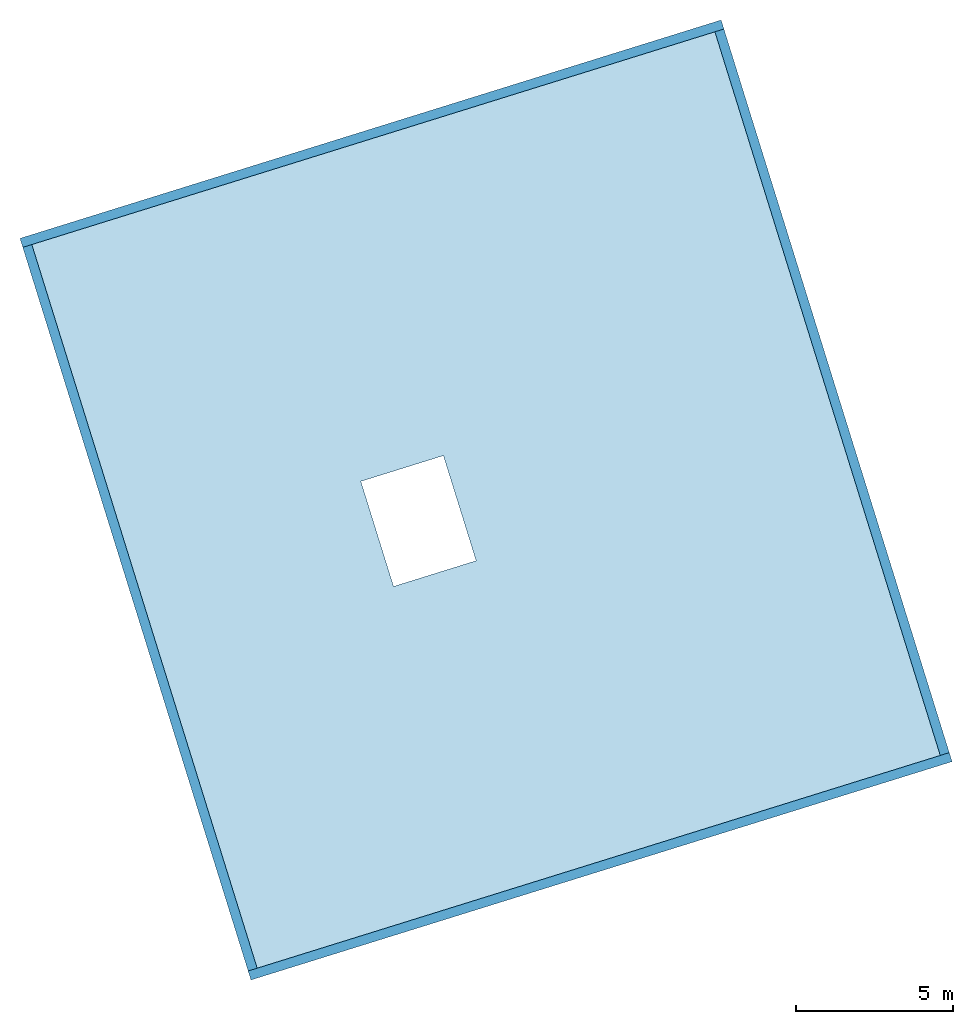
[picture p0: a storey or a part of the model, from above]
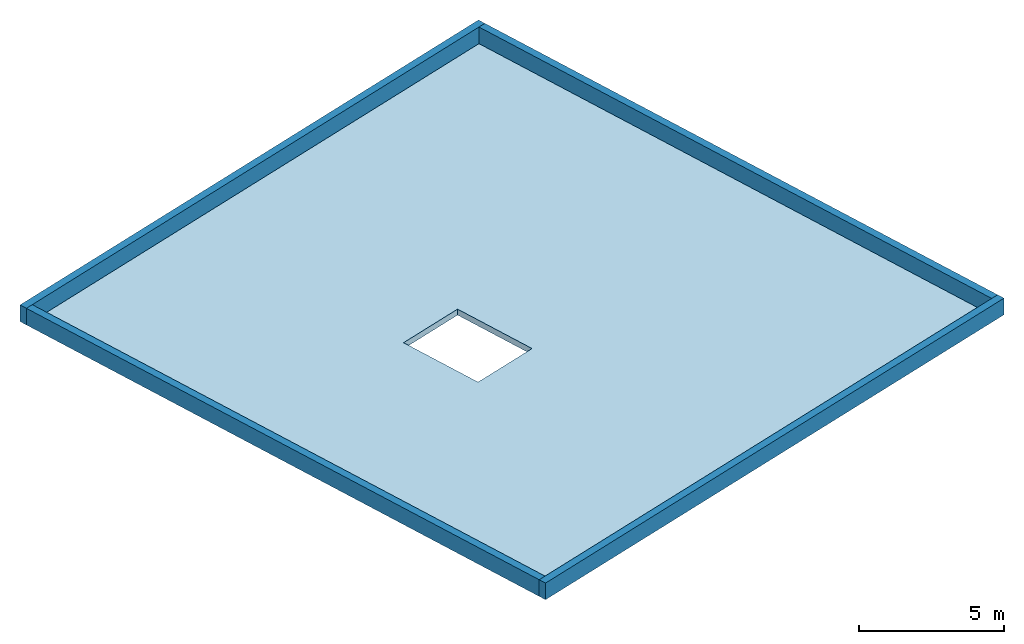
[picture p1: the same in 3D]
Properties of the parts of a building model (IFC4), part 1 of 3

# File
Description: ViewDefinition [ReferenceView_V1.2], RevitIdentifiers [ContentGUID: 7b0fba1c-e461-43e6-a004-74300536da52, VersionGUID: 268f83e5-9db5-464a-ad46-58d0016dc86d, NumberOfSaves: 303], Options [Excluded Entities: IfcGroup;], CoordinateReference [CoordinateBase: Survey Point, ProjectSite: Internal]
File name: MiniBIM 3.1 DO_01_VORM.ifc
Time: 2025-11-07T13:31:51+01:00
Organization: VORM Holding B.V.
Written by: IfcOpenShell 0.8.2
Made in: Bonsai 0.8.2

# IfcProject, 0000
LongName: Voorbeelmodel MiniBIM 3.1 DO-fase; Phase: PROJECTFASE

# IfcSite, Schiehaven
RefLatitude: 51, 54, 13, 78253; RefLongitude: 4, 27, 15, 99642; RefElevation: 3.5 m
Pset_SiteCommon - Reference: Project Information

# IfcBuilding, VORM huis
LongName: VORM huis
Pset_BuildingCommon - Reference: Project Information; NumberOfStoreys: 11; IsLandmarked: no
Pset_BuildingElementProxyCommon - Reference: Project Information; IsExternal: no
Pset_BuildingStoreyCommon - Reference: Project Information; AboveGround: no
Pset_BuildingSystemCommon - Reference: Project Information

# IfcBuildingStorey: Level:Level bouwniveau (PBP) (11)
In: VORM huis
Pset_BuildingStoreyCommon - Reference: Level bouwniveau (PBP)
Name | LongName | Elevation (m) | EntranceLevel | AboveGround
-1 kelder | -1 kelder | -3.2 | no | no
00 begane grond | begane grond | 0 | yes | yes
01 eerste verdieping | 01 eerste verdieping | 3.9 | no | yes
02 tweede verdieping | 02 tweede verdieping | 6.9 | no | yes
03 derde verdieping | 03 derde verdieping | 9.9 | no | yes
04 vierde verdieping | 04 vierde verdieping | 12.9 | no | yes
05 vijfde verdieping | 05 vijfde verdieping | 15.9 | no | yes
06 zesde verdieping | 06 zesde verdieping | 18.9 | no | yes
07 zevende verdieping | 07 zevende verdieping | 21.9 | no | yes
08 achtste verdieping | 08 achtste verdieping | 24.9 | no | yes
09 negende verdieping | 09 negende verdieping | 27.9 | no | yes

# IfcBoiler: NLRS_51_ME_WB_warmtepomp_gen:generiek (45)
Type - Classification: 51.51 (NL-SfB); Material: <Unnamed>
Pset_BoilerTypeCommon - Reference: generiek; sets with these values: 2
Name (NLRS_51_ME_WB_warmtepomp_gen:generiek:...)
1525490
1530097
1530123
1530149
1530175
1530331
1530383
1558899
1559981
1560007
1560033
1560059
1560215
1560267
1570773
1575072
1600094
1600120
1600146
1600172
1600328
1600380
1600641
1600830
1601019
1601208
1601397
1602758
1603185
1605235
1605260
1605285
1605310
1605460
1605510
1606281
1609021
1609049
1609077
1609105
1609273
1609329
1615438
1619511
1668635

# IfcBuildingElementProxy: VORM_coordinatiepunt:CRS-coordinatiepunt, CRS-coordinatiepunt
In: 00 begane grond
Type - Classification: 00.00 (NL-SfB); Material: Blauw, Wit
Pset_BuildingElementProxyCommon - IsExternal: no; Reference: CRS-coordinatiepunt
Pset_EnvironmentalImpactIndicators - Reference: CRS-coordinatiepunt
Qto_BuildingElementProxyQuantities - NetSurfaceArea: 6.92096 m2; NetVolume: 0.458368 m3

# IfcBuildingElementProxy: VORM_coordinatiepunt:Lokaal-coordinatiepunt, Lokaal-coordinatiepunt
In: 00 begane grond
Type - Classification: 00.00 (NL-SfB); Material: Blauw, Wit
Pset_BuildingElementProxyCommon - IsExternal: no; Reference: Lokaal-coordinatiepunt
Pset_EnvironmentalImpactIndicators - Reference: Lokaal-coordinatiepunt
Qto_BuildingElementProxyQuantities - NetSurfaceArea: 7.78088 m2; NetVolume: 1.00022 m3

# IfcDistributionChamberElement: NLRS_61_GM_UN_Jonka meterkast_gen:Jonka_kast (52)
Type - PredefinedType: METERCHAMBER; Classification: 61.51 centrale elektrotechnische voorzieningen; energiedistributie laagspanning ?1kV, voedingsleiding laagspanningshoofdverdeler (NL-SfB); Material: <Unnamed>
Type - Pset_ManufacturerTypeInformation - Manufacturer: Jonka o.g.
Pset_DistributionChamberElementCommon - Reference: Jonka_kast; sets with these values: 2
Qto_DistributionChamberElementBaseQuantities - GrossSurfaceArea: 0.130276 m2; NetSurfaceArea: 15.0923 m2; GrossVolume: 0.000819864 m3; NetVolume: 0.122447 m3
Name (NLRS_61_GM_UN_Jonka meterkast_gen:Jonka_kast:...)
1522652
1530094
1530120
1530146
1530172
1530328
1530380
1555103
1556118
1556176
1558414
1558432
1558450
1558896
1559978
1560004
1560030
1560056
1560212
1560264
1563814
1565700
1565724
1565748
1565772
1565916
1565964
1575132
1600095
1600121
1600147
1600173
1600329
1600381
1603042
1605222
1605247
1605272
1605297
1605447
1605497
1606282
1609022
1609050
1609078
1609106
1609274
1609330
1611610
1618740
1668613
1668718

# IfcDoor: 31_DO_buitendeur dubbel:buitendeur zelfsluitend 30min (2)
In: 00 begane grond
Type - PredefinedType: DOOR; Classification: 31.30 buitenwandopeningen; gevuld met deuren, algemeen (verzamelniveau) (NL-SfB); Material: PD_a_buitenwandopeningen, metaal_aluminium_ntb
Type - Pset_DoorCommon - IsExternal: no; FireRating: 30
OverallHeight: 2.35 m; OverallWidth: 1.965 m
Pset_DoorCommon - Reference: buitendeur zelfsluitend 30min
Pset_EnvironmentalImpactIndicators - Reference: buitendeur zelfsluitend 30min
MiniBIM ILS - BouwwerkNummer: 01
Qto_DoorBaseQuantities - Width: 1.965 m; Height: 2.35 m; Perimeter: 1.965 m; Area: 4.61775 m2
Name | Gebruiksbestemming | Orientatie
Vluchtdeur | Overige gebruiksfunctie | West
Vluchtdeur | Bijeenkomstfunctie | Oost

# IfcDoor: 31_DO_buitendeur enkel:buitendeur zelfsluitend 30min (2)
In: 00 begane grond
Type - PredefinedType: DOOR; Classification: 31.30 buitenwandopeningen; gevuld met deuren, algemeen (verzamelniveau) (NL-SfB); Material: PD_a_buitenwandopeningen, metaal_aluminium_ntb
Type - Pset_DoorCommon - IsExternal: no; FireRating: 30
OverallHeight: 2.35 m; OverallWidth: 1.05 m
Pset_DoorCommon - Reference: buitendeur zelfsluitend 30min
Pset_EnvironmentalImpactIndicators - Reference: buitendeur zelfsluitend 30min
MiniBIM ILS - BouwwerkNummer: 01; Gebruiksbestemming: Overige gebruiksfunctie
Qto_DoorBaseQuantities - Width: 1.05 m; Height: 2.35 m; Perimeter: 2 m; Area: 2.4675 m2
Name | Orientatie
Vluchtdeur | Oost
Vluchtdeur | West

# IfcDoor: 31_DO_buitendeur enkel:woningtoegangsdeur (6)
In: 00 begane grond
Type - PredefinedType: DOOR; OperationType: REVOLVING; Classification: 31.30 buitenwandopeningen; gevuld met deuren, algemeen (verzamelniveau) (NL-SfB); Material: PD_a_buitenwandopeningen, metaal_aluminium_ntb
Type - Woningtoegangsdeur:1 - PanelOperation: REVOLVING
Type - Pset_DoorCommon - IsExternal: no
OverallHeight: 2.35 m; OverallWidth: 1.05 m
Pset_DoorCommon - Reference: woningtoegangsdeur
Pset_EnvironmentalImpactIndicators - Reference: woningtoegangsdeur
MiniBIM ILS - BouwwerkNummer: 01; Gebruiksbestemming: Woonfunctie
Qto_DoorBaseQuantities - Width: 1.05 m; Height: 2.35 m; Perimeter: 2 m; Area: 2.4675 m2
Name | Orientatie
3 x Woningtoegangsdeur | Zuid
3 x Woningtoegangsdeur | Noord

# IfcDoor: 32_DO_binnendeur dubbel:binnendeur zelfsluitend 30min (3)
In: 00 begane grond
Type - PredefinedType: DOOR; Classification: 32.30 binnenwandopeningen; gevuld met deuren, algemeen (verzamelniveau) (NL-SfB); Material: PD_a_binnenwandopeningen, metaal_aluminium_ntb
Type - Pset_DoorCommon - IsExternal: no; FireRating: 30
OverallHeight: 2.35 m; OverallWidth: 1.95 m
Pset_DoorCommon - Reference: binnendeur zelfsluitend 30min
Pset_EnvironmentalImpactIndicators - Reference: binnendeur zelfsluitend 30min
Qto_DoorBaseQuantities - Width: 1.95 m; Height: 2.35 m; Perimeter: 1.95 m; Area: 4.5825 m2

# IfcDoor: 32_DO_binnendeur enkel:binnendeur (357)
Type - PredefinedType: DOOR; OperationType: REVOLVING; Classification: 32.30 binnenwandopeningen; gevuld met deuren, algemeen (verzamelniveau) (NL-SfB); Material: PD_a_binnenwandopeningen, metaal_aluminium_ntb
Type - Binnendeur:1 - PanelOperation: REVOLVING
Type - Pset_DoorCommon - IsExternal: no
OverallHeight: 2.35 m; OverallWidth: 1.05 m
Pset_DoorCommon - Reference: binnendeur
Pset_EnvironmentalImpactIndicators - Reference: binnendeur
Qto_DoorBaseQuantities - Width: 1.05 m; Height: 2.35 m; Perimeter: 2 m; Area: 2.4675 m2
Name | In
41 x Binnendeur | 02 tweede verdieping
41 x Binnendeur | 03 derde verdieping
41 x Binnendeur | 04 vierde verdieping
41 x Binnendeur | 05 vijfde verdieping
41 x Binnendeur | 06 zesde verdieping
41 x Binnendeur | 07 zevende verdieping
41 x Binnendeur | 08 achtste verdieping
52 x Binnendeur | 01 eerste verdieping
18 x Binnendeur | 00 begane grond

# IfcDoor: 32_DO_binnendeur enkel:binnendeur zelfsluitend 30min (45)
Type - PredefinedType: DOOR; Classification: 32.30 binnenwandopeningen; gevuld met deuren, algemeen (verzamelniveau) (NL-SfB); Material: PD_a_binnenwandopeningen, metaal_aluminium_ntb
Type - Pset_DoorCommon - IsExternal: no; FireRating: 30
OverallHeight: 2.35 m; OverallWidth: 1.05 m
Pset_DoorCommon - Reference: binnendeur zelfsluitend 30min
Pset_EnvironmentalImpactIndicators - Reference: binnendeur zelfsluitend 30min
Qto_DoorBaseQuantities - Width: 1.05 m; Height: 2.35 m; Perimeter: 2 m; Area: 2.4675 m2
Name | In | BouwwerkNummer
4 x Vluchtdeur | 01 eerste verdieping | 01
4 x Vluchtdeur | 02 tweede verdieping | 01
4 x Vluchtdeur | 03 derde verdieping | 01
4 x Vluchtdeur | 04 vierde verdieping | 01
4 x Vluchtdeur | 05 vijfde verdieping | 01
4 x Vluchtdeur | 06 zesde verdieping | 01
2 x Vluchtdeur | -1 kelder | 01
4 x Vluchtdeur | 00 begane grond | 01
4 x Vluchtdeur | 07 zevende verdieping | 01
4 x Vluchtdeur | 08 achtste verdieping | 01
4 x Vluchtdeur | -1 kelder
3 x Vluchtdeur | 00 begane grond

# IfcDoor: 32_DO_binnendeur enkel:kastdeur (6)
In: 00 begane grond
Type - PredefinedType: DOOR; OperationType: REVOLVING; Classification: 32.30 binnenwandopeningen; gevuld met deuren, algemeen (verzamelniveau) (NL-SfB); Material: PD_a_binnenwandopeningen, metaal_aluminium_ntb
Type - Binnendeur:1 - PanelOperation: REVOLVING
Type - Pset_DoorCommon - IsExternal: no
OverallHeight: 2.35 m; OverallWidth: 0.95 m
Pset_DoorCommon - Reference: kastdeur
Pset_EnvironmentalImpactIndicators - Reference: kastdeur
Qto_DoorBaseQuantities - Width: 0.95 m; Height: 2.35 m; Perimeter: 1.8 m; Area: 2.2325 m2

# IfcDoor: 32_DO_binnendeur enkel:woningtoegangsdeur (46)
Type - PredefinedType: DOOR; OperationType: REVOLVING; Classification: 32.30 binnenwandopeningen; gevuld met deuren, algemeen (verzamelniveau) (NL-SfB); Material: PD_a_binnenwandopeningen, metaal_aluminium_ntb
Type - Woningtoegangsdeur:1 - PanelOperation: REVOLVING
Type - Pset_DoorCommon - IsExternal: no
OverallHeight: 2.35 m; OverallWidth: 1.05 m
Pset_DoorCommon - Reference: woningtoegangsdeur
Pset_EnvironmentalImpactIndicators - Reference: woningtoegangsdeur
MiniBIM ILS - BouwwerkNummer: 01
Qto_DoorBaseQuantities - Width: 1.05 m; Height: 2.35 m; Perimeter: 2 m; Area: 2.4675 m2
Name | In
6 x Woningtoegangsdeur | 02 tweede verdieping
6 x Woningtoegangsdeur | 03 derde verdieping
6 x Woningtoegangsdeur | 04 vierde verdieping
6 x Woningtoegangsdeur | 05 vijfde verdieping
6 x Woningtoegangsdeur | 06 zesde verdieping
6 x Woningtoegangsdeur | 07 zevende verdieping
6 x Woningtoegangsdeur | 08 achtste verdieping
4 x Woningtoegangsdeur | 01 eerste verdieping

# IfcDoor: 66_WI_liftdeur:brandweerlift - eenzijdig toegankelijk (2)
In: -1 kelder
Type - PredefinedType: DOOR; Classification: 66.10 transport; liftinstallaties, algemeen (verzamelniveau) (NL-SfB); Material: metaal_aluminium_ntb
OverallHeight: 2.4 m; OverallWidth: 1 m
Pset_DoorCommon - IsExternal: no; Reference: brandweerlift - eenzijdig toegankelijk
Pset_EnvironmentalImpactIndicators - Reference: brandweerlift - eenzijdig toegankelijk
MiniBIM ILS - BouwwerkNummer: 01
Qto_DoorBaseQuantities - Width: 1 m; Height: 2.4 m; Perimeter: 1.1 m; Area: 2.4 m2

# IfcDoor: 66_WI_liftdeur:brandweerlift - tweezijdig toegankelijk (18)
Type - PredefinedType: DOOR; Classification: 66.10 transport; liftinstallaties, algemeen (verzamelniveau) (NL-SfB); Material: metaal_aluminium_ntb
OverallHeight: 2.4 m; OverallWidth: 1 m
Pset_DoorCommon - IsExternal: no; Reference: brandweerlift - tweezijdig toegankelijk
Pset_EnvironmentalImpactIndicators - Reference: brandweerlift - tweezijdig toegankelijk
MiniBIM ILS - BouwwerkNummer: 01
Qto_DoorBaseQuantities - Width: 1 m; Height: 2.4 m; Perimeter: 1.1 m; Area: 2.4 m2
Name | In
2 x Brandweerlift | 01 eerste verdieping
2 x Brandweerlift | 02 tweede verdieping
2 x Brandweerlift | 03 derde verdieping
2 x Brandweerlift | 04 vierde verdieping
2 x Brandweerlift | 05 vijfde verdieping
2 x Brandweerlift | 06 zesde verdieping
2 x Brandweerlift | 07 zevende verdieping
2 x Brandweerlift | 08 achtste verdieping
2 x Brandweerlift | 00 begane grond

# IfcElectricAppliance: NLRS_85_SE_UN_opstelplaats wasmachine_gen:wasdroger (46)
Type - PredefinedType: TUMBLEDRYER; Classification: 85.11 losse schoonmaakinventaris; standaard, schoonmaakapparatuur (NL-SfB); Material: <Unnamed>
Pset_ElectricApplianceTypeCommon - Reference: wasdroger; sets with these values: 2
Name (NLRS_85_SE_UN_opstelplaats wasmachine_gen:wasdroger:...)
1528874
1530101
1530127
1530153
1530179
1530335
1530387
1558902
1559984
1560010
1560036
1560062
1560218
1560270
1565124
1565705
1565729
1565753
1565777
1565921
1565969
1575067
1600093
1600119
1600145
1600171
1600327
1600379
1603184
1605234
1605259
1605284
1605309
1605459
1605509
1606280
1609020
1609048
1609076
1609104
1609272
1609328
1611609
1618739
1668612
1668717

# IfcFurniture: NLRS_73_CASE_LB_keukenblok L a_gen:keukenblok hoek 2700x2100 (25)
Type - Classification: 73.11 vaste keukenvoorzieningen; standaard, keukenmeubilering (NL-SfB); Material: <Unnamed>
Pset_EnvironmentalImpactIndicators - Reference: keukenblok hoek 2700x2100; sets with these values: 2
Name (NLRS_73_CASE_LB_keukenblok L a_gen:keukenblok hoek 2700x2100:...)
1528325
1530100
1530126
1530152
1530178
1530334
1530386
1558901
1559983
1560009
1560035
1560061
1560217
1560269
1578744
1600112
1600138
1600164
1600190
1600346
1600398
1616319
1668742
1731784
1731788

# IfcFurniture: NLRS_73_CASE_LB_keukenblok a_gen:keukenblok 3200 (27)
Type - Classification: 73.11 vaste keukenvoorzieningen; standaard, keukenmeubilering (NL-SfB); Material: <Unnamed>
Pset_EnvironmentalImpactIndicators - Reference: keukenblok 3200; sets with these values: 2
Name (NLRS_73_CASE_LB_keukenblok a_gen:keukenblok 3200:...)
1554877
1556104
1556162
1558400
1558418
1558436
1569815
1570051
1570056
1570061
1570066
1570096
1570106
1603050
1605228
1605253
1605278
1605303
1605453
1605503
1606299
1609034
1609062
1609090
1609118
1609286
1609342

# IfcOpeningElement (740)
PredefinedType: OPENING
Name | In | Depth (m) | Height (m) | Width (m)
4 x Constructieve wand | 01 eerste verdieping | 0.25 | 2.4 | 1.25 | Pset_EnvironmentalImpactIndicators - Reference: 28_WA_skelet_wand 250mm_gen; sets with these values: 2
4 x Constructieve wand | 01 eerste verdieping | 0.25 | 2.4 | 2.4 | Pset_EnvironmentalImpactIndicators - Reference: 28_WA_skelet_wand 250mm_gen; sets with these values: 2
Constructieve vloer | 01 eerste verdieping |  | 2.75 | 3.5 | Pset_EnvironmentalImpactIndicators - Reference: 28_FL_skelet_vloer 250mm; sets with these values: 2
Constructieve vloer | 01 eerste verdieping |  | 1.2 | 3.3 | Pset_EnvironmentalImpactIndicators - Reference: 28_FL_skelet_vloer 250mm; sets with these values: 2
3 x Constructieve vloer | 01 eerste verdieping |  | 0.25 | 0.8 | Pset_EnvironmentalImpactIndicators - Reference: 28_FL_skelet_vloer 250mm; sets with these values: 2
2 x Constructieve vloer | 01 eerste verdieping |  | 3.038 | 0.95 | Pset_EnvironmentalImpactIndicators - Reference: 28_FL_skelet_vloer 250mm; sets with these values: 2
3 x Constructieve vloer | 01 eerste verdieping |  | 0.8 | 0.25 | Pset_EnvironmentalImpactIndicators - Reference: 28_FL_skelet_vloer 250mm; sets with these values: 2
3 x Constructieve vloer | 01 eerste verdieping |  | 0.95 | 3.038 | Pset_EnvironmentalImpactIndicators - Reference: 28_FL_skelet_vloer 250mm; sets with these values: 2
3 x Constructieve wand | 02 tweede verdieping | 0.25 | 2.4 | 1.1 | Pset_EnvironmentalImpactIndicators - Reference: 28_WA_skelet_wand 250mm_gen; sets with these values: 2
3 x Constructieve wand | 02 tweede verdieping | 0.25 | 2.4 | 1.2 | Pset_EnvironmentalImpactIndicators - Reference: 28_WA_skelet_wand 250mm_gen; sets with these values: 2
Constructieve vloer | 02 tweede verdieping |  | 2.75 | 3.5 | Pset_EnvironmentalImpactIndicators - Reference: 28_FL_skelet_vloer 250mm; sets with these values: 2
Constructieve vloer | 02 tweede verdieping |  | 1.2 | 3.3 | Pset_EnvironmentalImpactIndicators - Reference: 28_FL_skelet_vloer 250mm; sets with these values: 2
2 x Constructieve vloer | 02 tweede verdieping |  | 0.85 | 0.3 | Pset_EnvironmentalImpactIndicators - Reference: 28_FL_skelet_vloer 250mm; sets with these values: 2
Constructieve vloer | 02 tweede verdieping |  | 1.25 | 0.3 | Pset_EnvironmentalImpactIndicators - Reference: 28_FL_skelet_vloer 250mm; sets with these values: 2
Constructieve vloer | 02 tweede verdieping |  | 0.3 | 1.40216 | Pset_EnvironmentalImpactIndicators - Reference: 28_FL_skelet_vloer 250mm; sets with these values: 2
Constructieve vloer | 02 tweede verdieping |  | 0.275 | 1.25 | Pset_EnvironmentalImpactIndicators - Reference: 28_FL_skelet_vloer 250mm; sets with these values: 2
Constructieve vloer | 02 tweede verdieping |  | 0.3 | 1.25 | Pset_EnvironmentalImpactIndicators - Reference: 28_FL_skelet_vloer 250mm; sets with these values: 2
3 x Constructieve wand | 03 derde verdieping | 0.25 | 2.4 | 1.1 | Pset_EnvironmentalImpactIndicators - Reference: 28_WA_skelet_wand 250mm_gen; sets with these values: 2
3 x Constructieve wand | 03 derde verdieping | 0.25 | 2.4 | 1.2 | Pset_EnvironmentalImpactIndicators - Reference: 28_WA_skelet_wand 250mm_gen; sets with these values: 2
Constructieve vloer | 03 derde verdieping |  | 2.75 | 3.5 | Pset_EnvironmentalImpactIndicators - Reference: 28_FL_skelet_vloer 250mm; sets with these values: 2
Constructieve vloer | 03 derde verdieping |  | 1.2 | 3.3 | Pset_EnvironmentalImpactIndicators - Reference: 28_FL_skelet_vloer 250mm; sets with these values: 2
2 x Constructieve vloer | 03 derde verdieping |  | 0.85 | 0.3 | Pset_EnvironmentalImpactIndicators - Reference: 28_FL_skelet_vloer 250mm; sets with these values: 2
Constructieve vloer | 03 derde verdieping |  | 1.25 | 0.3 | Pset_EnvironmentalImpactIndicators - Reference: 28_FL_skelet_vloer 250mm; sets with these values: 2
Constructieve vloer | 03 derde verdieping |  | 0.3 | 1.40216 | Pset_EnvironmentalImpactIndicators - Reference: 28_FL_skelet_vloer 250mm; sets with these values: 2
Constructieve vloer | 03 derde verdieping |  | 0.275 | 1.25 | Pset_EnvironmentalImpactIndicators - Reference: 28_FL_skelet_vloer 250mm; sets with these values: 2
Constructieve vloer | 03 derde verdieping |  | 0.3 | 1.25 | Pset_EnvironmentalImpactIndicators - Reference: 28_FL_skelet_vloer 250mm; sets with these values: 2
3 x Constructieve wand | 04 vierde verdieping | 0.25 | 2.4 | 1.1 | Pset_EnvironmentalImpactIndicators - Reference: 28_WA_skelet_wand 250mm_gen; sets with these values: 2
3 x Constructieve wand | 04 vierde verdieping | 0.25 | 2.4 | 1.2 | Pset_EnvironmentalImpactIndicators - Reference: 28_WA_skelet_wand 250mm_gen; sets with these values: 2
Constructieve vloer | 04 vierde verdieping |  | 2.75 | 3.5 | Pset_EnvironmentalImpactIndicators - Reference: 28_FL_skelet_vloer 250mm; sets with these values: 2
Constructieve vloer | 04 vierde verdieping |  | 1.2 | 3.3 | Pset_EnvironmentalImpactIndicators - Reference: 28_FL_skelet_vloer 250mm; sets with these values: 2
2 x Constructieve vloer | 04 vierde verdieping |  | 0.85 | 0.3 | Pset_EnvironmentalImpactIndicators - Reference: 28_FL_skelet_vloer 250mm; sets with these values: 2
Constructieve vloer | 04 vierde verdieping |  | 1.25 | 0.3 | Pset_EnvironmentalImpactIndicators - Reference: 28_FL_skelet_vloer 250mm; sets with these values: 2
Constructieve vloer | 04 vierde verdieping |  | 0.3 | 1.40216 | Pset_EnvironmentalImpactIndicators - Reference: 28_FL_skelet_vloer 250mm; sets with these values: 2
Constructieve vloer | 04 vierde verdieping |  | 0.275 | 1.25 | Pset_EnvironmentalImpactIndicators - Reference: 28_FL_skelet_vloer 250mm; sets with these values: 2
Constructieve vloer | 04 vierde verdieping |  | 0.3 | 1.25 | Pset_EnvironmentalImpactIndicators - Reference: 28_FL_skelet_vloer 250mm; sets with these values: 2
3 x Constructieve wand | 05 vijfde verdieping | 0.25 | 2.4 | 1.1 | Pset_EnvironmentalImpactIndicators - Reference: 28_WA_skelet_wand 250mm_gen; sets with these values: 2
3 x Constructieve wand | 05 vijfde verdieping | 0.25 | 2.4 | 1.2 | Pset_EnvironmentalImpactIndicators - Reference: 28_WA_skelet_wand 250mm_gen; sets with these values: 2
Constructieve vloer | 05 vijfde verdieping |  | 2.75 | 3.5 | Pset_EnvironmentalImpactIndicators - Reference: 28_FL_skelet_vloer 250mm; sets with these values: 2
Constructieve vloer | 05 vijfde verdieping |  | 1.2 | 3.3 | Pset_EnvironmentalImpactIndicators - Reference: 28_FL_skelet_vloer 250mm; sets with these values: 2
2 x Constructieve vloer | 05 vijfde verdieping |  | 0.85 | 0.3 | Pset_EnvironmentalImpactIndicators - Reference: 28_FL_skelet_vloer 250mm; sets with these values: 2
Constructieve vloer | 05 vijfde verdieping |  | 1.25 | 0.3 | Pset_EnvironmentalImpactIndicators - Reference: 28_FL_skelet_vloer 250mm; sets with these values: 2
Constructieve vloer | 05 vijfde verdieping |  | 0.3 | 1.40216 | Pset_EnvironmentalImpactIndicators - Reference: 28_FL_skelet_vloer 250mm; sets with these values: 2
Constructieve vloer | 05 vijfde verdieping |  | 0.275 | 1.25 | Pset_EnvironmentalImpactIndicators - Reference: 28_FL_skelet_vloer 250mm; sets with these values: 2
Constructieve vloer | 05 vijfde verdieping |  | 0.3 | 1.25 | Pset_EnvironmentalImpactIndicators - Reference: 28_FL_skelet_vloer 250mm; sets with these values: 2
3 x Constructieve wand | 06 zesde verdieping | 0.25 | 2.4 | 1.1 | Pset_EnvironmentalImpactIndicators - Reference: 28_WA_skelet_wand 250mm_gen; sets with these values: 2
3 x Constructieve wand | 06 zesde verdieping | 0.25 | 2.4 | 1.2 | Pset_EnvironmentalImpactIndicators - Reference: 28_WA_skelet_wand 250mm_gen; sets with these values: 2
Constructieve vloer | 06 zesde verdieping |  | 2.75 | 3.5 | Pset_EnvironmentalImpactIndicators - Reference: 28_FL_skelet_vloer 250mm; sets with these values: 2
Constructieve vloer | 06 zesde verdieping |  | 1.2 | 3.3 | Pset_EnvironmentalImpactIndicators - Reference: 28_FL_skelet_vloer 250mm; sets with these values: 2
2 x Constructieve vloer | 06 zesde verdieping |  | 0.85 | 0.3 | Pset_EnvironmentalImpactIndicators - Reference: 28_FL_skelet_vloer 250mm; sets with these values: 2
Constructieve vloer | 06 zesde verdieping |  | 1.25 | 0.3 | Pset_EnvironmentalImpactIndicators - Reference: 28_FL_skelet_vloer 250mm; sets with these values: 2
Constructieve vloer | 06 zesde verdieping |  | 0.3 | 1.40216 | Pset_EnvironmentalImpactIndicators - Reference: 28_FL_skelet_vloer 250mm; sets with these values: 2
Constructieve vloer | 06 zesde verdieping |  | 0.275 | 1.25 | Pset_EnvironmentalImpactIndicators - Reference: 28_FL_skelet_vloer 250mm; sets with these values: 2
Constructieve vloer | 06 zesde verdieping |  | 0.3 | 1.25 | Pset_EnvironmentalImpactIndicators - Reference: 28_FL_skelet_vloer 250mm; sets with these values: 2
2 x Vluchtdeur | -1 kelder | 1.05 | 2.35 | 0.1 | Pset_EnvironmentalImpactIndicators - Reference: binnendeur zelfsluitend 30min; sets with these values: 2; Classification: 32.30 binnenwandopeningen; gevuld met deuren, algemeen (verzamelniveau) (NL-SfB)
2 x Vluchtdeur | 00 begane grond | 3.048 | 2.35 | 1.05 | Pset_EnvironmentalImpactIndicators - Reference: buitendeur zelfsluitend 30min; sets with these values: 2; Classification: 31.30 buitenwandopeningen; gevuld met deuren, algemeen (verzamelniveau) (NL-SfB)
2 x Vluchtdeur | 00 begane grond | 3.048 | 2.35 | 1.965 | Pset_EnvironmentalImpactIndicators - Reference: buitendeur zelfsluitend 30min; sets with these values: 2; Classification: 31.30 buitenwandopeningen; gevuld met deuren, algemeen (verzamelniveau) (NL-SfB)
Constructieve vloer | 00 begane grond |  | 2.75 | 3.5 | Pset_EnvironmentalImpactIndicators - Reference: 28_FL_skelet_vloer 250mm; sets with these values: 2
Constructieve vloer | 00 begane grond |  | 4.5 | 18.073 | Pset_EnvironmentalImpactIndicators - Reference: 28_FL_skelet_vloer 250mm; sets with these values: 2
Constructieve vloer | 00 begane grond |  | 3.52 | 1.2 | Pset_EnvironmentalImpactIndicators - Reference: 28_FL_skelet_vloer 250mm; sets with these values: 2
2 x Constructieve wand | 00 begane grond | 0.25 | 2.4 | 2.1 | Pset_EnvironmentalImpactIndicators - Reference: 28_WA_skelet_wand 250mm_gen; sets with these values: 2
Constructieve wand | 00 begane grond | 0.25 | 2.2 | 4.625 | Pset_EnvironmentalImpactIndicators - Reference: 28_WA_skelet_wand 250mm_gen; sets with these values: 2
3 x Constructieve wand | 07 zevende verdieping | 0.25 | 2.4 | 1.1 | Pset_EnvironmentalImpactIndicators - Reference: 28_WA_skelet_wand 250mm_gen; sets with these values: 2
3 x Constructieve wand | 07 zevende verdieping | 0.25 | 2.4 | 1.2 | Pset_EnvironmentalImpactIndicators - Reference: 28_WA_skelet_wand 250mm_gen; sets with these values: 2
Constructieve vloer | 07 zevende verdieping |  | 2.75 | 3.5 | Pset_EnvironmentalImpactIndicators - Reference: 28_FL_skelet_vloer 250mm; sets with these values: 2
Constructieve vloer | 07 zevende verdieping |  | 1.2 | 3.3 | Pset_EnvironmentalImpactIndicators - Reference: 28_FL_skelet_vloer 250mm; sets with these values: 2
2 x Constructieve vloer | 07 zevende verdieping |  | 0.85 | 0.3 | Pset_EnvironmentalImpactIndicators - Reference: 28_FL_skelet_vloer 250mm; sets with these values: 2
Constructieve vloer | 07 zevende verdieping |  | 1.25 | 0.3 | Pset_EnvironmentalImpactIndicators - Reference: 28_FL_skelet_vloer 250mm; sets with these values: 2
Constructieve vloer | 07 zevende verdieping |  | 0.3 | 1.40216 | Pset_EnvironmentalImpactIndicators - Reference: 28_FL_skelet_vloer 250mm; sets with these values: 2
Constructieve vloer | 07 zevende verdieping |  | 0.275 | 1.25 | Pset_EnvironmentalImpactIndicators - Reference: 28_FL_skelet_vloer 250mm; sets with these values: 2
Constructieve vloer | 07 zevende verdieping |  | 0.3 | 1.25 | Pset_EnvironmentalImpactIndicators - Reference: 28_FL_skelet_vloer 250mm; sets with these values: 2
Dakvloer | 09 negende verdieping |  | 2.75 | 3.5 | Pset_EnvironmentalImpactIndicators - Reference: 28_FL_skelet_dakvloer 250mm; sets with these values: 2
3 x Constructieve wand | 08 achtste verdieping | 0.25 | 2.4 | 1.1 | Pset_EnvironmentalImpactIndicators - Reference: 28_WA_skelet_wand 250mm_gen; sets with these values: 2
3 x Constructieve wand | 08 achtste verdieping | 0.25 | 2.4 | 1.2 | Pset_EnvironmentalImpactIndicators - Reference: 28_WA_skelet_wand 250mm_gen; sets with these values: 2
Constructieve vloer | 08 achtste verdieping |  | 2.75 | 3.5 | Pset_EnvironmentalImpactIndicators - Reference: 28_FL_skelet_vloer 250mm; sets with these values: 2
Constructieve vloer | 08 achtste verdieping |  | 1.2 | 3.3 | Pset_EnvironmentalImpactIndicators - Reference: 28_FL_skelet_vloer 250mm; sets with these values: 2
2 x Constructieve vloer | 08 achtste verdieping |  | 0.85 | 0.3 | Pset_EnvironmentalImpactIndicators - Reference: 28_FL_skelet_vloer 250mm; sets with these values: 2
Constructieve vloer | 08 achtste verdieping |  | 1.25 | 0.3 | Pset_EnvironmentalImpactIndicators - Reference: 28_FL_skelet_vloer 250mm; sets with these values: 2
Constructieve vloer | 08 achtste verdieping |  | 0.3 | 1.40216 | Pset_EnvironmentalImpactIndicators - Reference: 28_FL_skelet_vloer 250mm; sets with these values: 2
Constructieve vloer | 08 achtste verdieping |  | 0.275 | 1.25 | Pset_EnvironmentalImpactIndicators - Reference: 28_FL_skelet_vloer 250mm; sets with these values: 2
Constructieve vloer | 08 achtste verdieping |  | 0.3 | 1.25 | Pset_EnvironmentalImpactIndicators - Reference: 28_FL_skelet_vloer 250mm; sets with these values: 2
Constructieve wand | 00 begane grond | 0.25 | 2.2 | 4.5 | Pset_EnvironmentalImpactIndicators - Reference: 28_WA_skelet_wand 250mm_gen; sets with these values: 2
Funderingvloer | -1 kelder |  | 2.75 | 3.5 | Pset_EnvironmentalImpactIndicators - Reference: 13_FL_funderingvloer 250mm; sets with these values: 2
6 x Binnendeur | 02 tweede verdieping | 1.05 | 2.35 | 0.1 | Pset_EnvironmentalImpactIndicators - Reference: binnendeur; sets with these values: 2; Classification: 32.30 binnenwandopeningen; gevuld met deuren, algemeen (verzamelniveau) (NL-SfB)
2 x Binnenwand:1 | 02 tweede verdieping |  |  | 0.1 | Pset_EnvironmentalImpactIndicators - Reference: 22_WA_afbouw_binnenwand 100mm_gen; sets with these values: 2; Classification: 22.10 binnenwanden; niet constructief, algemeen (verzamelniveau) (NL-SfB); Qto_OpeningElementBaseQuantities - Area: 6.0575 m2; Volume: 1.98737 m3
6 x Binnendeur | 03 derde verdieping | 1.05 | 2.35 | 0.1 | Pset_EnvironmentalImpactIndicators - Reference: binnendeur; sets with these values: 2; Classification: 32.30 binnenwandopeningen; gevuld met deuren, algemeen (verzamelniveau) (NL-SfB)
2 x Binnenwand:1 | 03 derde verdieping |  |  | 0.1 | Pset_EnvironmentalImpactIndicators - Reference: 22_WA_afbouw_binnenwand 100mm_gen; sets with these values: 2; Classification: 22.10 binnenwanden; niet constructief, algemeen (verzamelniveau) (NL-SfB); Qto_OpeningElementBaseQuantities - Area: 6.0575 m2; Volume: 1.98737 m3
6 x Binnendeur | 04 vierde verdieping | 1.05 | 2.35 | 0.1 | Pset_EnvironmentalImpactIndicators - Reference: binnendeur; sets with these values: 2; Classification: 32.30 binnenwandopeningen; gevuld met deuren, algemeen (verzamelniveau) (NL-SfB)
2 x Binnenwand:1 | 04 vierde verdieping |  |  | 0.1 | Pset_EnvironmentalImpactIndicators - Reference: 22_WA_afbouw_binnenwand 100mm_gen; sets with these values: 2; Classification: 22.10 binnenwanden; niet constructief, algemeen (verzamelniveau) (NL-SfB); Qto_OpeningElementBaseQuantities - Area: 6.0575 m2; Volume: 1.98737 m3
6 x Binnendeur | 05 vijfde verdieping | 1.05 | 2.35 | 0.1 | Pset_EnvironmentalImpactIndicators - Reference: binnendeur; sets with these values: 2; Classification: 32.30 binnenwandopeningen; gevuld met deuren, algemeen (verzamelniveau) (NL-SfB)
2 x Binnenwand:1 | 05 vijfde verdieping |  |  | 0.1 | Pset_EnvironmentalImpactIndicators - Reference: 22_WA_afbouw_binnenwand 100mm_gen; sets with these values: 2; Classification: 22.10 binnenwanden; niet constructief, algemeen (verzamelniveau) (NL-SfB); Qto_OpeningElementBaseQuantities - Area: 6.0575 m2; Volume: 1.98737 m3
6 x Binnendeur | 06 zesde verdieping | 1.05 | 2.35 | 0.1 | Pset_EnvironmentalImpactIndicators - Reference: binnendeur; sets with these values: 2; Classification: 32.30 binnenwandopeningen; gevuld met deuren, algemeen (verzamelniveau) (NL-SfB)
2 x Binnenwand:1 | 06 zesde verdieping |  |  | 0.1 | Pset_EnvironmentalImpactIndicators - Reference: 22_WA_afbouw_binnenwand 100mm_gen; sets with these values: 2; Classification: 22.10 binnenwanden; niet constructief, algemeen (verzamelniveau) (NL-SfB); Qto_OpeningElementBaseQuantities - Area: 6.0575 m2; Volume: 1.98737 m3
6 x Binnendeur | 07 zevende verdieping | 1.05 | 2.35 | 0.1 | Pset_EnvironmentalImpactIndicators - Reference: binnendeur; sets with these values: 2; Classification: 32.30 binnenwandopeningen; gevuld met deuren, algemeen (verzamelniveau) (NL-SfB)
2 x Binnenwand:1 | 07 zevende verdieping |  |  | 0.1 | Pset_EnvironmentalImpactIndicators - Reference: 22_WA_afbouw_binnenwand 100mm_gen; sets with these values: 2; Classification: 22.10 binnenwanden; niet constructief, algemeen (verzamelniveau) (NL-SfB); Qto_OpeningElementBaseQuantities - Area: 6.0575 m2; Volume: 1.98737 m3
6 x Binnendeur | 08 achtste verdieping | 1.05 | 2.35 | 0.1 | Pset_EnvironmentalImpactIndicators - Reference: binnendeur; sets with these values: 2; Classification: 32.30 binnenwandopeningen; gevuld met deuren, algemeen (verzamelniveau) (NL-SfB)
2 x Binnenwand:1 | 08 achtste verdieping |  |  | 0.1 | Pset_EnvironmentalImpactIndicators - Reference: 22_WA_afbouw_binnenwand 100mm_gen; sets with these values: 2; Classification: 22.10 binnenwanden; niet constructief, algemeen (verzamelniveau) (NL-SfB); Qto_OpeningElementBaseQuantities - Area: 6.0575 m2; Volume: 1.98737 m3
10 x Binnendeur | 01 eerste verdieping | 1.05 | 2.35 | 0.1 | Pset_EnvironmentalImpactIndicators - Reference: binnendeur; sets with these values: 2; Classification: 32.30 binnenwandopeningen; gevuld met deuren, algemeen (verzamelniveau) (NL-SfB)
6 x Woningtoegangsdeur | 00 begane grond | 3.048 | 2.35 | 1.05 | Pset_EnvironmentalImpactIndicators - Reference: woningtoegangsdeur; sets with these values: 2; Classification: 31.30 buitenwandopeningen; gevuld met deuren, algemeen (verzamelniveau) (NL-SfB)
6 x Woningtoegangsdeur | 00 begane grond | 1.05 | 2.35 | 0.3 | Pset_EnvironmentalImpactIndicators - Reference: woningtoegangsdeur; sets with these values: 2; Classification: 31.30 buitenwandopeningen; gevuld met deuren, algemeen (verzamelniveau) (NL-SfB)
2 x Brandweerlift | 01 eerste verdieping | 0.75631 | 2.4 | 1
4 x Woningtoegangsdeur | 01 eerste verdieping | 0.25 | 1.05 | 2.35
2 x Vluchtdeur | 01 eerste verdieping | 0.1 | 1.05 | 2.35
2 x Vluchtdeur | 01 eerste verdieping | 0.1 | 2.35 | 1.05
2 x Binnendeur | 02 tweede verdieping | 0.25 | 1.05 | 2.35
2 x Woningtoegangsdeur | 02 tweede verdieping | 0.25 | 2.35 | 1.05
2 x Brandweerlift | 02 tweede verdieping | 0.75631 | 2.4 | 1
4 x Woningtoegangsdeur | 02 tweede verdieping | 0.25 | 1.05 | 2.35
2 x Vluchtdeur | 02 tweede verdieping | 0.1 | 1.05 | 2.35
2 x Vluchtdeur | 02 tweede verdieping | 0.1 | 2.35 | 1.05
2 x Binnendeur | 03 derde verdieping | 0.25 | 1.05 | 2.35
2 x Woningtoegangsdeur | 03 derde verdieping | 0.25 | 2.35 | 1.05
2 x Brandweerlift | 03 derde verdieping | 0.75631 | 2.4 | 1
4 x Woningtoegangsdeur | 03 derde verdieping | 0.25 | 1.05 | 2.35
2 x Vluchtdeur | 03 derde verdieping | 0.1 | 1.05 | 2.35
2 x Vluchtdeur | 03 derde verdieping | 0.1 | 2.35 | 1.05
2 x Binnendeur | 04 vierde verdieping | 0.25 | 1.05 | 2.35
2 x Woningtoegangsdeur | 04 vierde verdieping | 0.25 | 2.35 | 1.05
2 x Brandweerlift | 04 vierde verdieping | 0.75631 | 2.4 | 1
4 x Woningtoegangsdeur | 04 vierde verdieping | 0.25 | 1.05 | 2.35
2 x Vluchtdeur | 04 vierde verdieping | 0.1 | 1.05 | 2.35
2 x Vluchtdeur | 04 vierde verdieping | 0.1 | 2.35 | 1.05
2 x Binnendeur | 05 vijfde verdieping | 0.25 | 1.05 | 2.35
2 x Woningtoegangsdeur | 05 vijfde verdieping | 0.25 | 2.35 | 1.05
2 x Brandweerlift | 05 vijfde verdieping | 0.75631 | 2.4 | 1
4 x Woningtoegangsdeur | 05 vijfde verdieping | 0.25 | 1.05 | 2.35
2 x Vluchtdeur | 05 vijfde verdieping | 0.1 | 1.05 | 2.35
2 x Vluchtdeur | 05 vijfde verdieping | 0.1 | 2.35 | 1.05
2 x Binnendeur | 06 zesde verdieping | 0.25 | 1.05 | 2.35
2 x Woningtoegangsdeur | 06 zesde verdieping | 0.25 | 2.35 | 1.05
2 x Brandweerlift | 06 zesde verdieping | 0.75631 | 2.4 | 1
4 x Woningtoegangsdeur | 06 zesde verdieping | 0.25 | 1.05 | 2.35
2 x Vluchtdeur | 06 zesde verdieping | 0.1 | 1.05 | 2.35
2 x Vluchtdeur | 06 zesde verdieping | 0.1 | 2.35 | 1.05
2 x Brandweerlift | -1 kelder | 0.75631 | 2.4 | 1
2 x Vluchtdeur | -1 kelder | 0.2 | 1.05 | 2.35
4 x Vluchtdeur | -1 kelder | 0.1 | 1.05 | 2.35
4 x Vluchtdeur | 00 begane grond | 0.1 | 2.35 | 1.05
4 x Vluchtdeur | 00 begane grond | 3.048 | 2.35 | 1.05
Vluchtdeur | 00 begane grond | 0.25 | 2.35 | 1.05
2 x Vluchtdeur | 00 begane grond | 0.25 | 1.05 | 2.35
2 x Vluchtdeur | 00 begane grond | 0.25 | 1.95 | 2.35
2 x Binnendeur | 07 zevende verdieping | 0.25 | 1.05 | 2.35
2 x Woningtoegangsdeur | 07 zevende verdieping | 0.25 | 2.35 | 1.05
2 x Brandweerlift | 07 zevende verdieping | 0.75631 | 2.4 | 1
4 x Woningtoegangsdeur | 07 zevende verdieping | 0.25 | 1.05 | 2.35
2 x Vluchtdeur | 07 zevende verdieping | 0.1 | 1.05 | 2.35
2 x Vluchtdeur | 07 zevende verdieping | 0.1 | 2.35 | 1.05
2 x Binnendeur | 08 achtste verdieping | 0.25 | 1.05 | 2.35
2 x Woningtoegangsdeur | 08 achtste verdieping | 0.25 | 2.35 | 1.05
2 x Brandweerlift | 08 achtste verdieping | 0.75631 | 2.4 | 1
4 x Woningtoegangsdeur | 08 achtste verdieping | 0.25 | 1.05 | 2.35
2 x Vluchtdeur | 08 achtste verdieping | 0.1 | 1.05 | 2.35
2 x Vluchtdeur | 08 achtste verdieping | 0.1 | 2.35 | 1.05
2 x Brandweerlift | 00 begane grond | 0.75631 | 2.4 | 1
6 x Woningtoegangsdeur | 00 begane grond | 0.3 | 2.35 | 1.05
2 x Woningtoegangsdeur | 00 begane grond | 3.048 | 2.35 | 1.05
Vluchtdeur | 00 begane grond | 0.1 | 2.35 | 1.95
2 x Vluchtdeur | 00 begane grond | 0.3 | 1.965 | 2.35
2 x Vluchtdeur | 00 begane grond | 0.3 | 1.05 | 2.35
Vluchtdeur | 00 begane grond | 3.048 | 2.35 | 1.965
23 x Binnendeur | 02 tweede verdieping | 0.1 | 2.35 | 1.05
16 x Binnendeur | 02 tweede verdieping | 0.1 | 1.05 | 2.35
23 x Binnendeur | 03 derde verdieping | 0.1 | 2.35 | 1.05
16 x Binnendeur | 03 derde verdieping | 0.1 | 1.05 | 2.35
23 x Binnendeur | 04 vierde verdieping | 0.1 | 2.35 | 1.05
16 x Binnendeur | 04 vierde verdieping | 0.1 | 1.05 | 2.35
23 x Binnendeur | 05 vijfde verdieping | 0.1 | 2.35 | 1.05
16 x Binnendeur | 05 vijfde verdieping | 0.1 | 1.05 | 2.35
23 x Binnendeur | 06 zesde verdieping | 0.1 | 2.35 | 1.05
16 x Binnendeur | 06 zesde verdieping | 0.1 | 1.05 | 2.35
23 x Binnendeur | 07 zevende verdieping | 0.1 | 2.35 | 1.05
16 x Binnendeur | 07 zevende verdieping | 0.1 | 1.05 | 2.35
23 x Binnendeur | 08 achtste verdieping | 0.1 | 2.35 | 1.05
16 x Binnendeur | 08 achtste verdieping | 0.1 | 1.05 | 2.35
26 x Binnendeur | 01 eerste verdieping | 0.1 | 2.35 | 1.05
26 x Binnendeur | 01 eerste verdieping | 0.1 | 1.05 | 2.35
12 x Binnendeur | 01 eerste verdieping | 3.048 | 2.35 | 1.05
6 x Binnendeur | 00 begane grond | 0.1 | 0.95 | 2.35
12 x Binnendeur | 00 begane grond | 0.1 | 2.35 | 1.05
6 x Binnendeur | 00 begane grond | 3.048 | 2.35 | 1.05
6 x Binnendeur | 00 begane grond | 0.1 | 1.05 | 2.35
4 x Binnendeur | 02 tweede verdieping | 3.048 | 2.35 | 1.05
2 x Binnendeur | 03 derde verdieping | 3.048 | 2.35 | 1.05
2 x Binnendeur | 04 vierde verdieping | 3.048 | 2.35 | 1.05
2 x Binnendeur | 05 vijfde verdieping | 3.048 | 2.35 | 1.05
2 x Binnendeur | 06 zesde verdieping | 3.048 | 2.35 | 1.05
2 x Binnendeur | 07 zevende verdieping | 3.048 | 2.35 | 1.05
2 x Binnendeur | 08 achtste verdieping | 3.048 | 2.35 | 1.05

# IfcSanitaryTerminal: NLRS_74_PF_UN_douche_gen:douchebak 900x900mm (52)
Type - Classification: 74.11 vaste sanitaire voorzieningen; standaard, sanitaire toestellen; normaal (NL-SfB); Material: <Unnamed>
Pset_EnvironmentalImpactIndicators - Reference: douchebak 900x900mm; sets with these values: 2
Name (NLRS_74_PF_UN_douche_gen:douchebak 900x900mm:...)
1530099
1530125
1530151
1530177
1530333
1530385
1531931
1540546
1555691
1555715
1558199
1558215
1558231
1558904
1559986
1560012
1560038
1560064
1560220
1560272
1560423
1565689
1565713
1565737
1565761
1565905
1565953
1575057
1600092
1600118
1600144
1600170
1600326
1600378
1603036
1605218
1605243
1605268
1605293
1605443
1605493
1606279
1609019
1609047
1609075
1609103
1609271
1609327
1611608
1618738
1668611
1668716

# IfcSanitaryTerminal: NLRS_74_PF_UN_toilet hangend_gen:toilet hangend (58)
Type - PredefinedType: TOILETPAN; Classification: 74.11 vaste sanitaire voorzieningen; standaard, sanitaire toestellen; normaal (NL-SfB); Material: <Unnamed>
Pset_EnvironmentalImpactIndicators - Reference: toilet hangend; sets with these values: 2
Name (NLRS_74_PF_UN_toilet hangend_gen:toilet hangend:...)
1525048
1530096
1530122
1530148
1530174
1530330
1530382
1540599
1554898
1555692
1555716
1556109
1556167
1558200
1558216
1558232
1558405
1558423
1558441
1558898
1559980
1560006
1560032
1560058
1560214
1560266
1560417
1565687
1565711
1565735
1565759
1565903
1565951
1575056
1600091
1600117
1600143
1600169
1600325
1600377
1603181
1605231
1605256
1605281
1605306
1605456
1605506
1607091
1609040
1609068
1609096
1609124
1609292
1609348
1611627
1618753
1668622
1668731

# IfcSanitaryTerminal: NLRS_74_PF_WB_wastafel_gen:wastafel (52)
Type - PredefinedType: SINK; Classification: 74.11 vaste sanitaire voorzieningen; standaard, sanitaire toestellen; normaal (NL-SfB); Material: <Unnamed>
Pset_EnvironmentalImpactIndicators - Reference: wastafel; sets with these values: 2
Name (NLRS_74_PF_WB_wastafel_gen:wastafel:...)
1526483
1530098
1530124
1530150
1530176
1530332
1530384
1532102
1555680
1555704
1558188
1558204
1558220
1558900
1559982
1560008
1560034
1560060
1560216
1560268
1561637
1565696
1565720
1565744
1565768
1565912
1565960
1576951
1600107
1600133
1600159
1600185
1600341
1600393
1603039
1605219
1605244
1605269
1605294
1605444
1605494
1606294
1609030
1609058
1609086
1609114
1609282
1609338
1611618
1618747
1668620
1668725

# IfcSlab: Floor:13_FL_funderingvloer 250mm, Funderingvloer
In: -1 kelder
Type - PredefinedType: FLOOR; Material: beton_gewapend_ihw
Type - Pset_ReinforcementBarPitchOfSlab - Description: Funderingvloer
Type - Pset_SlabCommon - LoadBearing: yes
Classification: 13.20 vloeren op grondslag; constructief, algemeen (verzamelniveau) (NL-SfB)
Pset_EnvironmentalImpactIndicators - Reference: 13_FL_funderingvloer 250mm; sets with these values: 2
Pset_SlabCommon - IsExternal: no; LoadBearing: no; PitchAngle: 0 deg; Reference: 13_FL_funderingvloer 250mm
Qto_SlabBaseQuantities - Width: 10.3 m; Length: 7.5 m; Depth: 0.25 m; Perimeter: 116.798 m; GrossArea: 77.25 m2; NetArea: 67.625 m2; GrossVolume: 19.3125 m3; NetVolume: 16.9062 m3

# IfcSlab: Floor:23_FL_skelet_balkon 200mm (42)
Type - PredefinedType: FLOOR; Material: beton_gewapend_prefab-element
Type - Pset_ReinforcementBarPitchOfSlab - Description: Balkonvloer
Type - Pset_SlabCommon - LoadBearing: no
Classification: 23.10 vloeren; niet constructief, algemeen (verzamelniveau) (NL-SfB)
Pset_EnvironmentalImpactIndicators - Reference: 23_FL_skelet_balkon 200mm; sets with these values: 2
Pset_SlabCommon - PitchAngle: 0 deg; IsExternal: yes; Reference: 23_FL_skelet_balkon 200mm
Qto_SlabBaseQuantities - Width: 2 m; Length: 3.5 m; Depth: 0.2 m; Perimeter: 36.0892 m; GrossArea: 7 m2; NetArea: 7 m2; GrossVolume: 1.4 m3; NetVolume: 1.4 m3
Name | In
6 x Balkonvloer | 03 derde verdieping
6 x Balkonvloer | 04 vierde verdieping
6 x Balkonvloer | 05 vijfde verdieping
6 x Balkonvloer | 06 zesde verdieping
6 x Balkonvloer | 07 zevende verdieping
6 x Balkonvloer | 08 achtste verdieping
6 x Balkonvloer | 02 tweede verdieping

# IfcSlab: Floor:28_FL_skelet_dakterrasvloer 250mm (6)
Type - PredefinedType: ROOF; Material: beton_gewapend_ihw
Type - Pset_ReinforcementBarPitchOfSlab - Description: Begaanbare dakvloer
Type - Pset_SlabCommon - LoadBearing: yes
Classification: 27.10 daken; niet constructief, algemeen (verzamelniveau) (NL-SfB)
Pset_EnvironmentalImpactIndicators - Reference: 28_FL_skelet_dakterrasvloer 250mm; sets with these values: 2
Pset_SlabCommon - IsExternal: no; LoadBearing: no; PitchAngle: 0 deg; Reference: 28_FL_skelet_dakterrasvloer 250mm
Qto_SlabBaseQuantities - Depth: 0.25 m
Name | In | Width (m) | Length (m) | Perimeter (m) | GrossArea (m2) = NetArea (m2) | GrossVolume (m3) = NetVolume (m3)
2 x Begaanbare dakvloer | 02 tweede verdieping | 22.75 | 4.625 | 179.626 | 105.219 | 26.3047
4 x Begaanbare dakvloer | 01 eerste verdieping | 2 | 2.4 | 28.8714 | 4.8 | 1.2

# IfcSlab: Floor:28_FL_skelet_dakvloer 250mm, Dakvloer
In: 09 negende verdieping
Type - PredefinedType: ROOF; Material: beton_gewapend_ihw
Type - Pset_ReinforcementBarPitchOfSlab - Description: Dakvloer
Type - Pset_SlabCommon - LoadBearing: yes
Classification: 27.10 daken; niet constructief, algemeen (verzamelniveau) (NL-SfB)
Pset_EnvironmentalImpactIndicators - Reference: 28_FL_skelet_dakvloer 250mm; sets with these values: 2
Pset_SlabCommon - IsExternal: no; LoadBearing: no; PitchAngle: 0 deg; Reference: 28_FL_skelet_dakvloer 250mm
Qto_SlabBaseQuantities - Width: 22.75 m; Length: 24.1 m; Depth: 0.25 m; Perimeter: 307.415 m; GrossArea: 548.275 m2; NetArea: 538.65 m2; GrossVolume: 137.069 m3; NetVolume: 134.662 m3

# IfcSlab: Floor:28_FL_skelet_vloer 250mm (9)
Type - PredefinedType: FLOOR; Material: beton_gewapend_ihw
Type - Pset_ReinforcementBarPitchOfSlab - Description: Constructieve vloer
Type - Pset_SlabCommon - LoadBearing: yes
Classification: 28.20 hoofddraagconstructies; wanden en vloeren, algemeen (verzamelniveau) (NL-SfB)
Pset_EnvironmentalImpactIndicators - Reference: 28_FL_skelet_vloer 250mm; sets with these values: 2
Pset_SlabCommon - IsExternal: no; LoadBearing: no; Reference: 28_FL_skelet_vloer 250mm; PitchAngle: 0 deg
Qto_SlabBaseQuantities - Depth: 0.25 m
Name | In | Perimeter (m) | GrossArea (m2) | NetArea (m2) | GrossVolume (m3) | NetVolume (m3) | Width (m) | Length (m)
Constructieve vloer | 01 eerste verdieping | 442.913 | 711.553 | 678.377 | 177.888 | 169.594
Constructieve vloer | 02 tweede verdieping | 307.415 | 548.275 | 528.706 | 137.069 | 132.176 | 22.75 | 24.1
Constructieve vloer | 03 derde verdieping | 307.415 | 548.275 | 528.706 | 137.069 | 132.176 | 22.75 | 24.1
Constructieve vloer | 04 vierde verdieping | 307.415 | 548.275 | 528.706 | 137.069 | 132.176 | 22.75 | 24.1
Constructieve vloer | 05 vijfde verdieping | 307.415 | 548.275 | 528.706 | 137.069 | 132.176 | 22.75 | 24.1
Constructieve vloer | 06 zesde verdieping | 307.415 | 548.275 | 528.706 | 137.069 | 132.176 | 22.75 | 24.1
Constructieve vloer | 00 begane grond | 391.732 | 732.613 | 633.211 | 183.153 | 158.303
Constructieve vloer | 07 zevende verdieping | 307.415 | 548.275 | 528.706 | 137.069 | 132.176 | 22.75 | 24.1
Constructieve vloer | 08 achtste verdieping | 307.415 | 548.275 | 528.706 | 137.069 | 132.176 | 22.75 | 24.1

# IfcStair: Trap (18)
Type - PredefinedType: STRAIGHT_RUN_STAIR
Type - Pset_StairCommon - IsExternal: no; NosingLength: 0 m; NumberOfRiser: 0; NumberOfTreads: 0
Type - Pset_StairFlightCommon - NosingLength: 0 m; NumberOfRiser: 0; NumberOfTreads: 0
Classification: 24.10 trappen en hellingen; trappen, algemeen (verzamelniveau) (NL-SfB)
Pset_EnvironmentalImpactIndicators - Reference: NLRS_24_STR_reguliere trap-woonfunctie-breedte 1200mm_gen
Pset_StairCommon - Reference: NLRS_24_STR_reguliere trap-woonfunctie-breedte 1200mm_gen; TreadLength: 0.22 m; WalkingLineOffset: 1.9685 m; TreadLengthAtOffset: 0.22 m; TreadLengthAtInnerSide: 0.22 m
Pset_StairFlightCommon - Reference: NLRS_24_STR_reguliere trap-woonfunctie-breedte 1200mm_gen; TreadLength: 0.22 m; WalkingLineOffset: 1.9685 m; TreadLengthAtOffset: 0.22 m; TreadLengthAtInnerSide: 0.22 m
Name | In | Pset_StairCommon, NumberOfRiser = Pset_StairCommon, NumberOfTreads = Pset_StairFlightCommon, NumberOfRiser = Pset_StairFlightCommon, NumberOfTreads | Pset_StairCommon, RiserHeight (m) = Pset_StairFlightCommon, RiserHeight (m)
2 x Hoofdtrap | 01 eerste verdieping | 16 | 0.1875
2 x Hoofdtrap | 02 tweede verdieping | 16 | 0.1875
2 x Hoofdtrap | 03 derde verdieping | 16 | 0.1875
2 x Hoofdtrap | 04 vierde verdieping | 16 | 0.1875
2 x Hoofdtrap | 05 vijfde verdieping | 16 | 0.1875
2 x Hoofdtrap | 06 zesde verdieping | 16 | 0.1875
2 x Hoofdtrap | 07 zevende verdieping | 16 | 0.1875
2 x Hoofdtrap | -1 kelder | 17 | 0.188235
2 x Hoofdtrap | 00 begane grond | 21 | 0.185714

# IfcStairFlight: Monolithic Run:NLRS_24_STRR_trap-beton prefab-monolithisch-recht_gen_rsf (18)
Type - PredefinedType: STRAIGHT
Type - Pset_StairFlightCommon - NosingLength: 0 m
Classification: 24.10 trappen en hellingen; trappen, algemeen (verzamelniveau) (NL-SfB); Material: beton_gewapend_prefab-element
Pset_EnvironmentalImpactIndicators - Reference: NLRS_24_STRR_trap-beton prefab-monolithisch-recht_gen_rsf
Pset_StairFlightCommon - Reference: NLRS_24_STRR_trap-beton prefab-monolithisch-recht_gen_rsf; TreadLength: 0.22 m; WalkingLineOffset: 1.9685 m; TreadLengthAtOffset: 0.22 m; TreadLengthAtInnerSide: 0.22 m
Name | In | NumberOfRiser = NumberOfTreads | RiserHeight (m) | Length (m) | NetVolume (m3)
2 x Hoofdtrap Run 1 | 01 eerste verdieping | 16 | 0.1875 | 3.52 | 1.20115
2 x Hoofdtrap Run 1 | 02 tweede verdieping | 16 | 0.1875 | 3.52 | 1.20115
2 x Hoofdtrap Run 1 | 03 derde verdieping | 16 | 0.1875 | 3.52 | 1.20115
2 x Hoofdtrap Run 1 | 04 vierde verdieping | 16 | 0.1875 | 3.52 | 1.20115
2 x Hoofdtrap Run 1 | 05 vijfde verdieping | 16 | 0.1875 | 3.52 | 1.20115
2 x Hoofdtrap Run 1 | 06 zesde verdieping | 16 | 0.1875 | 3.52 | 1.20115
2 x Hoofdtrap Run 1 | 07 zevende verdieping | 16 | 0.1875 | 3.52 | 1.20115
2 x Hoofdtrap Run 1 | -1 kelder | 17 | 0.188235 | 3.74 | 1.28106
2 x Hoofdtrap Run 1 | 00 begane grond | 21 | 0.185714 | 4.62 | 1.5757

# IfcWall: Basic Wall:21_WA_gevel_binnenspouwwand 100mm_gen (54)
Type - PredefinedType: STANDARD
Type - Pset_ReinforcementBarPitchOfWall - Description: Binnenspouwblad
Type - Pset_WallCommon - LoadBearing: no
Classification: 21.12 buitenwanden; niet constructief, spouwwanden (NL-SfB); Material: ntb_ntb_ntb
Qto_WallBaseQuantities - Length: 7.25 m; Width: 0.1 m; GrossFootprintArea: 0.725 m2
Pset_EnvironmentalImpactIndicators - Reference: 21_WA_gevel_binnenspouwwand 100mm_gen; sets with these values: 2
Pset_WallCommon - ExtendToStructure: no; Reference: 21_WA_gevel_binnenspouwwand 100mm_gen; IsExternal: yes
Name | In | Height (m) | GrossVolume (m3) = NetVolume (m3) | GrossSideArea (m2) = NetSideArea (m2)
6 x Binnenspouwblad | 01 eerste verdieping | 2.75 | 1.99375 | 19.9375
6 x Binnenspouwblad | 02 tweede verdieping | 2.75 | 1.99375 | 19.9375
6 x Binnenspouwblad | 03 derde verdieping | 2.75 | 1.99375 | 19.9375
6 x Binnenspouwblad | 04 vierde verdieping | 2.75 | 1.99375 | 19.9375
6 x Binnenspouwblad | 05 vijfde verdieping | 2.75 | 1.99375 | 19.9375
6 x Binnenspouwblad | 06 zesde verdieping | 2.75 | 1.99375 | 19.9375
6 x Binnenspouwblad | 07 zevende verdieping | 2.75 | 1.99375 | 19.9375
6 x Binnenspouwblad | 08 achtste verdieping | 2.75 | 1.99375 | 19.9375
6 x Binnenspouwblad | 00 begane grond | 3.65 | 2.3995 | 23.995

# IfcWall: Basic Wall:21_WA_gevel_buitenwand 100mm_gen (4)
In: 01 eerste verdieping
Type - PredefinedType: STANDARD
Type - Pset_ReinforcementBarPitchOfWall - Description: Gevelwand
Type - Pset_WallCommon - LoadBearing: no
Classification: 21.10 buitenwanden; niet constructief, algemeen (verzamelniveau) (NL-SfB); Material: ntb_ntb_ntb
Qto_WallBaseQuantities - Height: 3 m; Length: 2.4 m; Width: 0.1 m; GrossFootprintArea: 0.24 m2; GrossVolume: 0.72 m3; GrossSideArea: 7.2 m2; NetSideArea: 7.2 m2; NetVolume: 0.72 m3
Pset_EnvironmentalImpactIndicators - Reference: 21_WA_gevel_buitenwand 100mm_gen; sets with these values: 2
Pset_WallCommon - ExtendToStructure: no; IsExternal: yes; Reference: 21_WA_gevel_buitenwand 100mm_gen
MiniBIM ILS - BouwwerkNummer: 01; Gebruiksbestemming: Woonfunctie; Glaspercentage: 40
Name | Orientatie
2 x Gevelwand | West
2 x Gevelwand | Oost

# IfcWall: Basic Wall:21_WA_gevel_buitenwand 150mm_gen (12)
In: 01 eerste verdieping
Type - PredefinedType: STANDARD
Type - Pset_ReinforcementBarPitchOfWall - Description: Gevelwand
Type - Pset_WallCommon - LoadBearing: no
Classification: 21.10 buitenwanden; niet constructief, algemeen (verzamelniveau) (NL-SfB); Material: ntb_ntb_ntb
Qto_WallBaseQuantities - Height: 2.75 m; Width: 0.15 m
Pset_EnvironmentalImpactIndicators - Reference: 21_WA_gevel_buitenwand 150mm_gen; sets with these values: 2
Pset_WallCommon - ExtendToStructure: no; IsExternal: yes; Reference: 21_WA_gevel_buitenwand 150mm_gen
MiniBIM ILS - BouwwerkNummer: 01; Gebruiksbestemming: Woonfunctie; Glaspercentage: 40
Name | Length (m) | GrossFootprintArea (m2) | GrossVolume (m3) | GrossSideArea (m2) = NetSideArea (m2) | NetVolume (m3) | Orientatie
2 x Gevelwand | 1.95 | 0.2925 | 0.804375 | 5.3625 | 0.804375 | Noord
2 x Gevelwand | 2.55 | 0.3825 | 1.05187 | 7.0125 | 1.05187 | West
2 x Gevelwand | 1.8 | 0.27 | 0.7425 | 4.95 | 0.7425 | Zuid
2 x Gevelwand | 1.95 | 0.2925 | 0.804375 | 5.3625 | 0.804375 | Zuid
2 x Gevelwand | 1.8 | 0.27 | 0.7425 | 4.95 | 0.7425 | Noord
Gevelwand | 2.55 | 0.3825 | 1.05187 | 7.0125 | 1.05188 | Oost
Gevelwand | 2.55 | 0.3825 | 1.05187 | 7.0125 | 1.05187 | Oost

# IfcWall: Basic Wall:21_WA_gevel_buitenwand 300mm_gen (106)
Type - PredefinedType: STANDARD
Type - Pset_ReinforcementBarPitchOfWall - Description: Gevelwand
Type - Pset_WallCommon - LoadBearing: no
Classification: 21.10 buitenwanden; niet constructief, algemeen (verzamelniveau) (NL-SfB); Material: ntb_ntb_ntb
Qto_WallBaseQuantities - Width: 0.3 m
Pset_EnvironmentalImpactIndicators - Reference: 21_WA_gevel_buitenwand 300mm_gen; sets with these values: 2
Pset_WallCommon - ExtendToStructure: no; IsExternal: yes; Reference: 21_WA_gevel_buitenwand 300mm_gen
MiniBIM ILS - BouwwerkNummer: 01
Name | In | Height (m) | Length (m) | GrossFootprintArea (m2) | GrossVolume (m3) = NetVolume (m3) | GrossSideArea (m2) = NetSideArea (m2) | Gebruiksbestemming | Glaspercentage | Orientatie
2 x Gevelwand | 01 eerste verdieping | 3 | 10.95 | 3.285 | 9.855 | 32.85 | Woonfunctie | 40 | West
Gevelwand | 02 tweede verdieping | 3 | 24.1 | 7.23 | 21.69 | 72.3 | Woonfunctie | 40 | West
Gevelwand | 02 tweede verdieping | 3 | 23.35 | 7.005 | 21.015 | 70.05 | Woonfunctie | 40 | Zuid
Gevelwand | 02 tweede verdieping | 3 | 24.1 | 7.23 | 21.69 | 72.3 | Woonfunctie | 40 | Oost
Gevelwand | 02 tweede verdieping | 3 | 23.35 | 7.005 | 21.015 | 70.05 | Woonfunctie | 40 | Noord
Gevelwand | 03 derde verdieping | 3 | 24.1 | 7.23 | 21.69 | 72.3 | Woonfunctie | 40 | West
Gevelwand | 03 derde verdieping | 3 | 23.35 | 7.005 | 21.015 | 70.05 | Woonfunctie | 40 | Zuid
Gevelwand | 03 derde verdieping | 3 | 24.1 | 7.23 | 21.69 | 72.3 | Woonfunctie | 40 | Oost
Gevelwand | 03 derde verdieping | 3 | 23.35 | 7.005 | 21.015 | 70.05 | Woonfunctie | 40 | Noord
Gevelwand | 04 vierde verdieping | 3 | 24.1 | 7.23 | 21.69 | 72.3 | Woonfunctie | 40 | West
Gevelwand | 04 vierde verdieping | 3 | 23.35 | 7.005 | 21.015 | 70.05 | Woonfunctie | 40 | Zuid
Gevelwand | 04 vierde verdieping | 3 | 24.1 | 7.23 | 21.69 | 72.3 | Woonfunctie | 40 | Oost
Gevelwand | 04 vierde verdieping | 3 | 23.35 | 7.005 | 21.015 | 70.05 | Woonfunctie | 40 | Noord
Gevelwand | 05 vijfde verdieping | 3 | 24.1 | 7.23 | 21.69 | 72.3 | Woonfunctie | 40 | West
Gevelwand | 05 vijfde verdieping | 3 | 23.35 | 7.005 | 21.015 | 70.05 | Woonfunctie | 40 | Zuid
Gevelwand | 05 vijfde verdieping | 3 | 24.1 | 7.23 | 21.69 | 72.3 | Woonfunctie | 40 | Oost
Gevelwand | 05 vijfde verdieping | 3 | 23.35 | 7.005 | 21.015 | 70.05 | Woonfunctie | 40 | Noord
Gevelwand | 06 zesde verdieping | 3 | 24.1 | 7.23 | 21.69 | 72.3 | Woonfunctie | 40 | West
Gevelwand | 06 zesde verdieping | 3 | 23.35 | 7.005 | 21.015 | 70.05 | Woonfunctie | 40 | Zuid
Gevelwand | 06 zesde verdieping | 3 | 24.1 | 7.23 | 21.69 | 72.3 | Woonfunctie | 40 | Oost
Gevelwand | 06 zesde verdieping | 3 | 23.35 | 7.005 | 21.015 | 70.05 | Woonfunctie | 40 | Noord
2 x Gevelwand | 00 begane grond | 4.4 | 6.775 | 2.0325 | 8.943 | 29.81 | Woonfunctie | 40 | West
2 x Gevelwand | 00 begane grond | 3.9 | 6.775 | 2.0325 | 7.92675 | 26.4225 | Woonfunctie | 40 | Oost
Gevelwand | 07 zevende verdieping | 3 | 24.1 | 7.23 | 21.69 | 72.3 | Woonfunctie | 40 | West
Gevelwand | 07 zevende verdieping | 3 | 23.35 | 7.005 | 21.015 | 70.05 | Woonfunctie | 40 | Zuid
Gevelwand | 07 zevende verdieping | 3 | 24.1 | 7.23 | 21.69 | 72.3 | Woonfunctie | 40 | Oost
Gevelwand | 07 zevende verdieping | 3 | 23.35 | 7.005 | 21.015 | 70.05 | Woonfunctie | 40 | Noord
2 x Gevelwand | 02 tweede verdieping | 0.7 | 4.325 | 1.2975 | 0.90825 | 3.0275 | Woonfunctie | 0 | West
Gevelwand | 02 tweede verdieping | 0.7 | 23.35 | 7.005 | 4.9035 | 16.345 | Woonfunctie | 0 | Zuid
2 x Gevelwand | 02 tweede verdieping | 0.7 | 4.325 | 1.2975 | 0.90825 | 3.0275 | Woonfunctie | 0 | Oost
Gevelwand | 02 tweede verdieping | 0.7 | 23.35 | 7.005 | 4.9035 | 16.345 | Woonfunctie | 0 | Noord
Gevelwand | 08 achtste verdieping | 3 | 24.1 | 7.23 | 21.69 | 72.3 | Woonfunctie | 40 | West
Gevelwand | 08 achtste verdieping | 3 | 23.35 | 7.005 | 21.015 | 70.05 | Woonfunctie | 40 | Zuid
Gevelwand | 08 achtste verdieping | 3 | 24.1 | 7.23 | 21.69 | 72.3 | Woonfunctie | 40 | Oost
Gevelwand | 08 achtste verdieping | 3 | 23.35 | 7.005 | 21.015 | 70.05 | Woonfunctie | 40 | Noord
Gevelwand | 09 negende verdieping | 0.7 | 24.1 | 7.23 | 5.061 | 16.87 | Woonfunctie | 40 | West
Gevelwand | 09 negende verdieping | 0.7 | 23.35 | 7.005 | 4.9035 | 16.345 | Woonfunctie | 40 | Zuid
Gevelwand | 09 negende verdieping | 0.7 | 24.1 | 7.23 | 5.061 | 16.87 | Woonfunctie | 40 | Oost
Gevelwand | 09 negende verdieping | 0.7 | 23.35 | 7.005 | 4.9035 | 16.345 | Woonfunctie | 40 | Noord
Gevelwand | 01 eerste verdieping | 3 | 6.65 | 1.995 | 5.985 | 19.95 | Woonfunctie | 40 | West
2 x Gevelwand | 01 eerste verdieping | 3 | 10.95 | 3.285 | 9.855 | 32.85 | Woonfunctie | 40 | Oost
Gevelwand | 01 eerste verdieping | 3 | 6.65 | 1.995 | 5.985 | 19.95 | Woonfunctie | 40 | Oost
Gevelwand | 00 begane grond | 3.9 | 4.75 |  | 4.7885 | 16.0575 | Overige gebruiksfunctie | 10 | Oost
Gevelwand | 00 begane grond | 4.4 | 6.89 |  | 7.58948 | 25.6983 | Overige gebruiksfunctie | 0 | West
Gevelwand | 00 begane grond | 3.9 | 4.755 |  | 5.53435 | 18.5445 | Overige gebruiksfunctie | 0 | Oost
Gevelwand | 00 begane grond | 3.9 | 10.295 | 3.0885 | 10.6598 | 35.5327 | Bijeenkomstfunctie | 80 | Oost
Gevelwand | 00 begane grond | 4.4 | 8.16 | 2.448 | 10.7712 | 35.904 | Woonfunctie | 80 | West
Gevelwand | 00 begane grond | 4.4 | 4.75 |  | 5.501 | 18.4325 | Overige gebruiksfunctie | 10 | West
4 x Gevelwand | 01 eerste verdieping | 3 | 0.85 | 0.255 | 0.765 | 2.55 | Woonfunctie | 40 | Zuid
6 x Gevelwand | 01 eerste verdieping | 2.75 | 0.6 | 0.18 | 0.495 | 1.65 | Woonfunctie | 40 | Oost
6 x Gevelwand | 01 eerste verdieping | 2.75 | 0.6 | 0.18 | 0.495 | 1.65 | Woonfunctie | 40 | West
3 x Gevelwand | 01 eerste verdieping | 2.75 | 6.65 | 1.995 | 5.48625 | 18.2875 | Woonfunctie | 40 | Zuid
4 x Gevelwand | 01 eerste verdieping | 3 | 0.85 | 0.255 | 0.765 | 2.55 | Woonfunctie | 40 | Noord
3 x Gevelwand | 01 eerste verdieping | 2.75 | 6.65 | 1.995 | 5.48625 | 18.2875 | Woonfunctie | 40 | Noord
4 x Gevelwand | 00 begane grond | 4.4 | 0.85 | 0.255 | 1.122 | 3.74 | Woonfunctie | 40 | Zuid
6 x Gevelwand | 00 begane grond | 4.4 | 0.6 | 0.18 | 0.792 | 2.64 | Woonfunctie | 40 | Oost
6 x Gevelwand | 00 begane grond | 4.4 | 0.6 | 0.18 | 0.792 | 2.64 | Woonfunctie | 40 | West
3 x Gevelwand | 00 begane grond | 4.4 | 6.65 | 1.995 | 8.03775 | 26.7925 | Woonfunctie | 40 | Zuid
4 x Gevelwand | 00 begane grond | 4.4 | 0.85 | 0.255 | 1.122 | 3.74 | Woonfunctie | 40 | Noord
3 x Gevelwand | 00 begane grond | 4.4 | 6.65 | 1.995 | 8.03775 | 26.7925 | Woonfunctie | 40 | Noord

# IfcWall: Basic Wall:22_WA_afbouw_binnenwand 100mm_gen (573)
Type - PredefinedType: STANDARD
Type - Pset_ReinforcementBarPitchOfWall - Description: Binnenwand
Type - Pset_WallCommon - LoadBearing: no
Classification: 22.10 binnenwanden; niet constructief, algemeen (verzamelniveau) (NL-SfB); Material: ntb_ntb_ntb
Qto_WallBaseQuantities - Width: 0.1 m
Pset_EnvironmentalImpactIndicators - Reference: 22_WA_afbouw_binnenwand 100mm_gen; sets with these values: 2
Pset_WallCommon - IsExternal: no; ExtendToStructure: no; Reference: 22_WA_afbouw_binnenwand 100mm_gen
Name | In | Height (m) | Length (m) | GrossFootprintArea (m2) | GrossVolume (m3) | GrossSideArea (m2) = NetSideArea (m2) | NetVolume (m3)
Binnenwand | 01 eerste verdieping | 2.75 | 1.45 | 0.145 | 0.152 | 1.52 | 0.152
Binnenwand | 01 eerste verdieping | 2.75 | 1.2 | 0.12 | 0.08325 | 0.8325 | 0.08325
2 x Binnenwand | 01 eerste verdieping | 2.75 | 1.5 | 0.15 | 0.16575 | 1.6575 | 0.16575
Binnenwand | 02 tweede verdieping | 2.75 | 1.45 | 0.145 | 0.152 | 1.52 | 0.152
3 x Binnenwand | 02 tweede verdieping | 2.75 | 1.2 | 0.12 | 0.08325 | 0.8325 | 0.08325
2 x Binnenwand | 02 tweede verdieping | 2.75 | 1.5 | 0.15 | 0.16575 | 1.6575 | 0.16575
Binnenwand | 03 derde verdieping | 2.75 | 1.45 | 0.145 | 0.152 | 1.52 | 0.152
3 x Binnenwand | 03 derde verdieping | 2.75 | 1.2 | 0.12 | 0.08325 | 0.8325 | 0.08325
2 x Binnenwand | 03 derde verdieping | 2.75 | 1.5 | 0.15 | 0.16575 | 1.6575 | 0.16575
Binnenwand | 04 vierde verdieping | 2.75 | 1.45 | 0.145 | 0.152 | 1.52 | 0.152
3 x Binnenwand | 04 vierde verdieping | 2.75 | 1.2 | 0.12 | 0.08325 | 0.8325 | 0.08325
2 x Binnenwand | 04 vierde verdieping | 2.75 | 1.5 | 0.15 | 0.16575 | 1.6575 | 0.16575
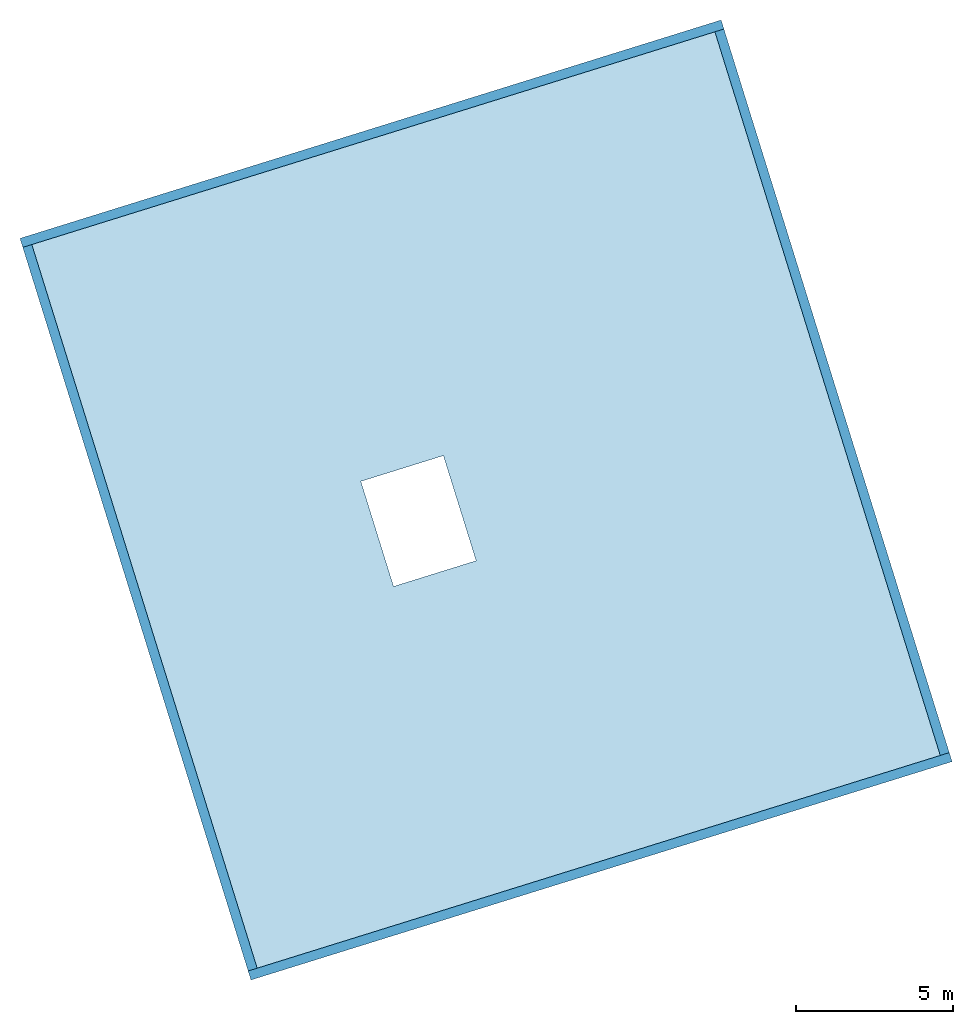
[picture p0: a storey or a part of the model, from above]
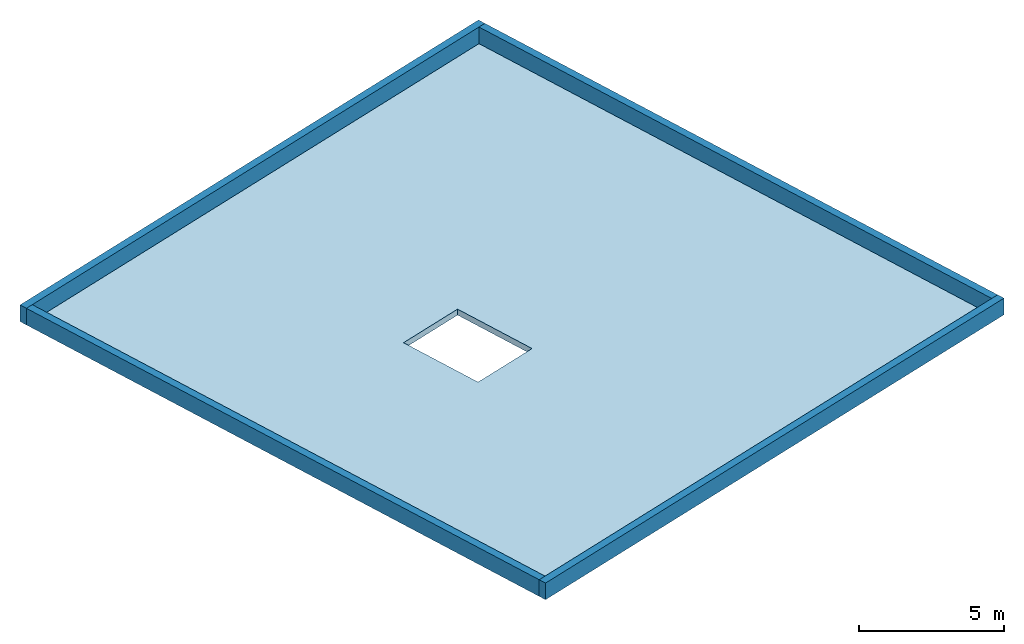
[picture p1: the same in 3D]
Properties of the parts of a building model (IFC4), part 2 of 3

# IfcWall: Basic Wall:22_WA_afbouw_binnenwand 100mm_gen (573)
Name | In | Height (m) | Length (m) | GrossFootprintArea (m2) | GrossVolume (m3) | GrossSideArea (m2) = NetSideArea (m2) | NetVolume (m3)
Binnenwand | 05 vijfde verdieping | 2.75 | 1.45 | 0.145 | 0.152 | 1.52 | 0.152
3 x Binnenwand | 05 vijfde verdieping | 2.75 | 1.2 | 0.12 | 0.08325 | 0.8325 | 0.08325
2 x Binnenwand | 05 vijfde verdieping | 2.75 | 1.5 | 0.15 | 0.16575 | 1.6575 | 0.16575
Binnenwand | 06 zesde verdieping | 2.75 | 1.45 | 0.145 | 0.152 | 1.52 | 0.152
3 x Binnenwand | 06 zesde verdieping | 2.75 | 1.2 | 0.12 | 0.08325 | 0.8325 | 0.08325
2 x Binnenwand | 06 zesde verdieping | 2.75 | 1.5 | 0.15 | 0.16575 | 1.6575 | 0.16575
2 x Binnenwand | -1 kelder | 2.95 | 2.7 | 0.27 | 0.7965 | 7.965 | 0.7965
2 x Binnenwand | -1 kelder | 2.95 | 3.045 | 0.3045 | 0.404775 | 4.04775 | 0.404775
2 x Binnenwand | 00 begane grond | 3.65 | 1.2 | 0.12 | 0.19125 | 1.9125 | 0.19125
Binnenwand | 07 zevende verdieping | 2.75 | 1.45 | 0.145 | 0.152 | 1.52 | 0.152
3 x Binnenwand | 07 zevende verdieping | 2.75 | 1.2 | 0.12 | 0.08325 | 0.8325 | 0.08325
2 x Binnenwand | 07 zevende verdieping | 2.75 | 1.5 | 0.15 | 0.16575 | 1.6575 | 0.16575
Binnenwand | 08 achtste verdieping | 2.75 | 1.45 | 0.145 | 0.152 | 1.52 | 0.152
3 x Binnenwand | 08 achtste verdieping | 2.75 | 1.2 | 0.12 | 0.08325 | 0.8325 | 0.08325
2 x Binnenwand | 08 achtste verdieping | 2.75 | 1.5 | 0.15 | 0.16575 | 1.6575 | 0.16575
Binnenwand | 00 begane grond | 3.65 | 7.25 | 0.725 | 2.188 | 21.88 | 2.188
2 x Binnenwand | 00 begane grond | 3.65 | 1.01 | 0.101 | 0.36865 | 3.6865 | 0.36865
Binnenwand | 00 begane grond | 3.65 | 7.25 | 0.725 | 2.64625 | 26.4625 | 2.64625
2 x Binnenwand | 00 begane grond | 3.65 | 4.45 | 0.445 | 1.3775 | 13.775 | 1.3775
Binnenwand | 02 tweede verdieping | 2.75 | 4.45 | 0.445 | 0.977 | 9.77 | 0.977
Binnenwand | 02 tweede verdieping | 2.75 | 3.1 | 0.31 | 0.60575 | 6.0575 | 0.60575
2 x Binnenwand | 02 tweede verdieping | 2.75 | 1.25 | 0.125 | 0.097 | 0.97 | 0.097
2 x Binnenwand | 02 tweede verdieping | 2.75 | 1.15 | 0.115 | 0.31625 | 3.1625 | 0.31625
5 x Binnenwand | 02 tweede verdieping | 2.75 | 1.25 | 0.125 | 0.34375 | 3.4375 | 0.34375
4 x Binnenwand | 02 tweede verdieping | 2.75 | 0.85 | 0.085 | 0.23375 | 2.3375 | 0.23375
2 x Binnenwand | 02 tweede verdieping | 2.75 | 2.5 | 0.25 | 0.44075 | 4.4075 | 0.44075
Binnenwand | 02 tweede verdieping | 2.75 | 6.675 | 0.6675 | 1.58888 | 15.8887 | 1.58888
2 x Binnenwand | 02 tweede verdieping | 2.75 | 3.2 | 0.32 | 0.60575 | 6.0575 | 0.60575
Binnenwand | 03 derde verdieping | 2.75 | 4.45 | 0.445 | 0.977 | 9.77 | 0.977
Binnenwand | 03 derde verdieping | 2.75 | 3.1 | 0.31 | 0.60575 | 6.0575 | 0.60575
2 x Binnenwand | 03 derde verdieping | 2.75 | 1.25 | 0.125 | 0.097 | 0.97 | 0.097
2 x Binnenwand | 03 derde verdieping | 2.75 | 1.15 | 0.115 | 0.31625 | 3.1625 | 0.31625
5 x Binnenwand | 03 derde verdieping | 2.75 | 1.25 | 0.125 | 0.34375 | 3.4375 | 0.34375
4 x Binnenwand | 03 derde verdieping | 2.75 | 0.85 | 0.085 | 0.23375 | 2.3375 | 0.23375
2 x Binnenwand | 03 derde verdieping | 2.75 | 2.5 | 0.25 | 0.44075 | 4.4075 | 0.44075
Binnenwand | 03 derde verdieping | 2.75 | 6.675 | 0.6675 | 1.58888 | 15.8887 | 1.58888
2 x Binnenwand | 03 derde verdieping | 2.75 | 3.2 | 0.32 | 0.60575 | 6.0575 | 0.60575
Binnenwand | 04 vierde verdieping | 2.75 | 4.45 | 0.445 | 0.977 | 9.77 | 0.977
Binnenwand | 04 vierde verdieping | 2.75 | 3.1 | 0.31 | 0.60575 | 6.0575 | 0.60575
2 x Binnenwand | 04 vierde verdieping | 2.75 | 1.25 | 0.125 | 0.097 | 0.97 | 0.097
2 x Binnenwand | 04 vierde verdieping | 2.75 | 1.15 | 0.115 | 0.31625 | 3.1625 | 0.31625
5 x Binnenwand | 04 vierde verdieping | 2.75 | 1.25 | 0.125 | 0.34375 | 3.4375 | 0.34375
4 x Binnenwand | 04 vierde verdieping | 2.75 | 0.85 | 0.085 | 0.23375 | 2.3375 | 0.23375
2 x Binnenwand | 04 vierde verdieping | 2.75 | 2.5 | 0.25 | 0.44075 | 4.4075 | 0.44075
Binnenwand | 04 vierde verdieping | 2.75 | 6.675 | 0.6675 | 1.58888 | 15.8887 | 1.58888
2 x Binnenwand | 04 vierde verdieping | 2.75 | 3.2 | 0.32 | 0.60575 | 6.0575 | 0.60575
Binnenwand | 05 vijfde verdieping | 2.75 | 4.45 | 0.445 | 0.977 | 9.77 | 0.977
Binnenwand | 05 vijfde verdieping | 2.75 | 3.1 | 0.31 | 0.60575 | 6.0575 | 0.60575
2 x Binnenwand | 05 vijfde verdieping | 2.75 | 1.25 | 0.125 | 0.097 | 0.97 | 0.097
2 x Binnenwand | 05 vijfde verdieping | 2.75 | 1.15 | 0.115 | 0.31625 | 3.1625 | 0.31625
5 x Binnenwand | 05 vijfde verdieping | 2.75 | 1.25 | 0.125 | 0.34375 | 3.4375 | 0.34375
4 x Binnenwand | 05 vijfde verdieping | 2.75 | 0.85 | 0.085 | 0.23375 | 2.3375 | 0.23375
2 x Binnenwand | 05 vijfde verdieping | 2.75 | 2.5 | 0.25 | 0.44075 | 4.4075 | 0.44075
Binnenwand | 05 vijfde verdieping | 2.75 | 6.675 | 0.6675 | 1.58888 | 15.8887 | 1.58888
2 x Binnenwand | 05 vijfde verdieping | 2.75 | 3.2 | 0.32 | 0.60575 | 6.0575 | 0.60575
Binnenwand | 06 zesde verdieping | 2.75 | 4.45 | 0.445 | 0.977 | 9.77 | 0.977
Binnenwand | 06 zesde verdieping | 2.75 | 3.1 | 0.31 | 0.60575 | 6.0575 | 0.60575
2 x Binnenwand | 06 zesde verdieping | 2.75 | 1.25 | 0.125 | 0.097 | 0.97 | 0.097
2 x Binnenwand | 06 zesde verdieping | 2.75 | 1.15 | 0.115 | 0.31625 | 3.1625 | 0.31625
5 x Binnenwand | 06 zesde verdieping | 2.75 | 1.25 | 0.125 | 0.34375 | 3.4375 | 0.34375
4 x Binnenwand | 06 zesde verdieping | 2.75 | 0.85 | 0.085 | 0.23375 | 2.3375 | 0.23375
2 x Binnenwand | 06 zesde verdieping | 2.75 | 2.5 | 0.25 | 0.44075 | 4.4075 | 0.44075
Binnenwand | 06 zesde verdieping | 2.75 | 6.675 | 0.6675 | 1.58888 | 15.8887 | 1.58888
2 x Binnenwand | 06 zesde verdieping | 2.75 | 3.2 | 0.32 | 0.60575 | 6.0575 | 0.60575
Binnenwand | 07 zevende verdieping | 2.75 | 4.45 | 0.445 | 0.977 | 9.77 | 0.977
Binnenwand | 07 zevende verdieping | 2.75 | 3.1 | 0.31 | 0.60575 | 6.0575 | 0.60575
2 x Binnenwand | 07 zevende verdieping | 2.75 | 1.25 | 0.125 | 0.097 | 0.97 | 0.097
2 x Binnenwand | 07 zevende verdieping | 2.75 | 1.15 | 0.115 | 0.31625 | 3.1625 | 0.31625
5 x Binnenwand | 07 zevende verdieping | 2.75 | 1.25 | 0.125 | 0.34375 | 3.4375 | 0.34375
4 x Binnenwand | 07 zevende verdieping | 2.75 | 0.85 | 0.085 | 0.23375 | 2.3375 | 0.23375
2 x Binnenwand | 07 zevende verdieping | 2.75 | 2.5 | 0.25 | 0.44075 | 4.4075 | 0.44075
Binnenwand | 07 zevende verdieping | 2.75 | 6.675 | 0.6675 | 1.58888 | 15.8887 | 1.58888
2 x Binnenwand | 07 zevende verdieping | 2.75 | 3.2 | 0.32 | 0.60575 | 6.0575 | 0.60575
Binnenwand | 08 achtste verdieping | 2.75 | 4.45 | 0.445 | 0.977 | 9.77 | 0.977
Binnenwand | 08 achtste verdieping | 2.75 | 3.1 | 0.31 | 0.60575 | 6.0575 | 0.60575
2 x Binnenwand | 08 achtste verdieping | 2.75 | 1.25 | 0.125 | 0.097 | 0.97 | 0.097
2 x Binnenwand | 08 achtste verdieping | 2.75 | 1.15 | 0.115 | 0.31625 | 3.1625 | 0.31625
5 x Binnenwand | 08 achtste verdieping | 2.75 | 1.25 | 0.125 | 0.34375 | 3.4375 | 0.34375
4 x Binnenwand | 08 achtste verdieping | 2.75 | 0.85 | 0.085 | 0.23375 | 2.3375 | 0.23375
2 x Binnenwand | 08 achtste verdieping | 2.75 | 2.5 | 0.25 | 0.44075 | 4.4075 | 0.44075
Binnenwand | 08 achtste verdieping | 2.75 | 6.675 | 0.6675 | 1.58888 | 15.8887 | 1.58888
2 x Binnenwand | 08 achtste verdieping | 2.75 | 3.2 | 0.32 | 0.60575 | 6.0575 | 0.60575
6 x Binnenwand | 01 eerste verdieping | 2.75 | 2.125 | 0.2125 | 0.337625 | 3.37625 | 0.337625
6 x Binnenwand | 01 eerste verdieping | 2.75 | 3.1 | 0.31 | 0.8525 | 8.525 | 0.8525
6 x Binnenwand | 01 eerste verdieping | 2.75 | 4.9 | 0.49 | 1.10075 | 11.0075 | 1.10075
6 x Binnenwand | 01 eerste verdieping | 2.75 | 3.15 | 0.315 | 0.86625 | 8.6625 | 0.86625
8 x Binnenwand | 01 eerste verdieping | 2.75 | 2.7 | 0.27 | 0.249 | 2.49 | 0.249
6 x Binnenwand | 01 eerste verdieping | 2.75 | 2.95 | 0.295 | 0.81125 | 8.1125 | 0.81125
6 x Binnenwand | 01 eerste verdieping | 2.75 | 0.9 | 0.09 | 0.2475 | 2.475 | 0.2475
6 x Binnenwand | 01 eerste verdieping | 2.75 | 0.25 | 0.025 | 0.06875 | 0.6875 | 0.06875
6 x Binnenwand | 00 begane grond | 3.65 | 1.55 | 0.155 | 0.3425 | 3.425 | 0.3425
6 x Binnenwand | 00 begane grond | 3.65 | 6.15 | 0.615 | 1.998 | 19.98 | 1.998
6 x Binnenwand | 00 begane grond | 3.65 | 0.95 | 0.095 | 0.34675 | 3.4675 | 0.34675
6 x Binnenwand | 00 begane grond | 3.65 | 1.55 | 0.155 | 0.319 | 3.19 | 0.319
6 x Binnenwand | 00 begane grond | 3.65 | 0.7 | 0.07 | 0.2555 | 2.555 | 0.2555
6 x Binnenwand | 00 begane grond | 3.65 | 1.65 | 0.165 | 0.3555 | 3.555 | 0.3555
6 x Binnenwand | 00 begane grond | 3.65 | 1.6 | 0.16 | 0.584 | 5.84 | 0.584
Binnenwand | 02 tweede verdieping | 2.75 | 4.3 | 0.43 | 0.93575 | 9.3575 | 0.93575
Binnenwand | 02 tweede verdieping | 2.75 | 2.941 | 0.2941 | 0.562025 | 5.62025 | 0.562025
Binnenwand | 02 tweede verdieping | 2.75 | 6.675 | 0.6675 | 1.58888 | 15.8887 | 1.58887
Binnenwand | 03 derde verdieping | 2.75 | 4.3 | 0.43 | 0.93575 | 9.3575 | 0.93575
Binnenwand | 03 derde verdieping | 2.75 | 2.941 | 0.2941 | 0.562025 | 5.62025 | 0.562025
Binnenwand | 03 derde verdieping | 2.75 | 6.675 | 0.6675 | 1.58888 | 15.8887 | 1.58887
Binnenwand | 04 vierde verdieping | 2.75 | 4.3 | 0.43 | 0.93575 | 9.3575 | 0.93575
Binnenwand | 04 vierde verdieping | 2.75 | 2.941 | 0.2941 | 0.562025 | 5.62025 | 0.562025
Binnenwand | 04 vierde verdieping | 2.75 | 6.675 | 0.6675 | 1.58888 | 15.8887 | 1.58887
Binnenwand | 05 vijfde verdieping | 2.75 | 4.3 | 0.43 | 0.93575 | 9.3575 | 0.93575
Binnenwand | 05 vijfde verdieping | 2.75 | 2.941 | 0.2941 | 0.562025 | 5.62025 | 0.562025
Binnenwand | 05 vijfde verdieping | 2.75 | 6.675 | 0.6675 | 1.58888 | 15.8887 | 1.58887
Binnenwand | 06 zesde verdieping | 2.75 | 4.3 | 0.43 | 0.93575 | 9.3575 | 0.93575
Binnenwand | 06 zesde verdieping | 2.75 | 2.941 | 0.2941 | 0.562025 | 5.62025 | 0.562025
Binnenwand | 06 zesde verdieping | 2.75 | 6.675 | 0.6675 | 1.58888 | 15.8887 | 1.58887
Binnenwand | 07 zevende verdieping | 2.75 | 4.3 | 0.43 | 0.93575 | 9.3575 | 0.93575
Binnenwand | 07 zevende verdieping | 2.75 | 2.941 | 0.2941 | 0.562025 | 5.62025 | 0.562025
Binnenwand | 07 zevende verdieping | 2.75 | 6.675 | 0.6675 | 1.58888 | 15.8887 | 1.58887
Binnenwand | 08 achtste verdieping | 2.75 | 4.3 | 0.43 | 0.93575 | 9.3575 | 0.93575
Binnenwand | 08 achtste verdieping | 2.75 | 2.941 | 0.2941 | 0.562025 | 5.62025 | 0.562025
Binnenwand | 08 achtste verdieping | 2.75 | 6.675 | 0.6675 | 1.58888 | 15.8887 | 1.58887
2 x Binnenwand | 02 tweede verdieping | 2.75 | 1.35 | 0.135 | 0.37125 | 3.7125 | 0.37125
3 x Binnenwand | 02 tweede verdieping | 2.75 | 2.7 | 0.27 | 0.49575 | 4.9575 | 0.49575
2 x Binnenwand | 02 tweede verdieping | 2.75 | 7.25 | 0.725 | 1.747 | 17.47 | 1.747
2 x Binnenwand | 03 derde verdieping | 2.75 | 1.35 | 0.135 | 0.37125 | 3.7125 | 0.37125
3 x Binnenwand | 03 derde verdieping | 2.75 | 2.7 | 0.27 | 0.49575 | 4.9575 | 0.49575
2 x Binnenwand | 03 derde verdieping | 2.75 | 7.25 | 0.725 | 1.747 | 17.47 | 1.747
2 x Binnenwand | 04 vierde verdieping | 2.75 | 1.35 | 0.135 | 0.37125 | 3.7125 | 0.37125
3 x Binnenwand | 04 vierde verdieping | 2.75 | 2.7 | 0.27 | 0.49575 | 4.9575 | 0.49575
2 x Binnenwand | 04 vierde verdieping | 2.75 | 7.25 | 0.725 | 1.747 | 17.47 | 1.747
2 x Binnenwand | 05 vijfde verdieping | 2.75 | 1.35 | 0.135 | 0.37125 | 3.7125 | 0.37125
3 x Binnenwand | 05 vijfde verdieping | 2.75 | 2.7 | 0.27 | 0.49575 | 4.9575 | 0.49575
2 x Binnenwand | 05 vijfde verdieping | 2.75 | 7.25 | 0.725 | 1.747 | 17.47 | 1.747
2 x Binnenwand | 06 zesde verdieping | 2.75 | 1.35 | 0.135 | 0.37125 | 3.7125 | 0.37125
3 x Binnenwand | 06 zesde verdieping | 2.75 | 2.7 | 0.27 | 0.49575 | 4.9575 | 0.49575
2 x Binnenwand | 06 zesde verdieping | 2.75 | 7.25 | 0.725 | 1.747 | 17.47 | 1.747
2 x Binnenwand | 07 zevende verdieping | 2.75 | 1.35 | 0.135 | 0.37125 | 3.7125 | 0.37125
3 x Binnenwand | 07 zevende verdieping | 2.75 | 2.7 | 0.27 | 0.49575 | 4.9575 | 0.49575
2 x Binnenwand | 07 zevende verdieping | 2.75 | 7.25 | 0.725 | 1.747 | 17.47 | 1.747
2 x Binnenwand | 08 achtste verdieping | 2.75 | 1.35 | 0.135 | 0.37125 | 3.7125 | 0.37125
3 x Binnenwand | 08 achtste verdieping | 2.75 | 2.7 | 0.27 | 0.49575 | 4.9575 | 0.49575
2 x Binnenwand | 08 achtste verdieping | 2.75 | 7.25 | 0.725 | 1.747 | 17.47 | 1.747
2 x Binnenwand | 02 tweede verdieping | 2.75 | 1.6 | 0.16 | 0.44 | 4.4 | 0.44
2 x Binnenwand | 03 derde verdieping | 2.75 | 1.6 | 0.16 | 0.44 | 4.4 | 0.44
2 x Binnenwand | 04 vierde verdieping | 2.75 | 1.6 | 0.16 | 0.44 | 4.4 | 0.44
2 x Binnenwand | 05 vijfde verdieping | 2.75 | 1.6 | 0.16 | 0.44 | 4.4 | 0.44
2 x Binnenwand | 06 zesde verdieping | 2.75 | 1.6 | 0.16 | 0.44 | 4.4 | 0.44
2 x Binnenwand | 07 zevende verdieping | 2.75 | 1.6 | 0.16 | 0.44 | 4.4 | 0.44
2 x Binnenwand | 08 achtste verdieping | 2.75 | 1.6 | 0.16 | 0.44 | 4.4 | 0.44
Binnenwand | 02 tweede verdieping | 2.75 | 2.55 | 0.255 | 0.4545 | 4.545 | 0.4545
Binnenwand | 02 tweede verdieping | 2.75 | 2.9 | 0.29 | 0.304 | 3.04 | 0.304
Binnenwand | 03 derde verdieping | 2.75 | 2.55 | 0.255 | 0.4545 | 4.545 | 0.4545
Binnenwand | 03 derde verdieping | 2.75 | 2.9 | 0.29 | 0.304 | 3.04 | 0.304
Binnenwand | 04 vierde verdieping | 2.75 | 2.55 | 0.255 | 0.4545 | 4.545 | 0.4545
Binnenwand | 04 vierde verdieping | 2.75 | 2.9 | 0.29 | 0.304 | 3.04 | 0.304
Binnenwand | 05 vijfde verdieping | 2.75 | 2.55 | 0.255 | 0.4545 | 4.545 | 0.4545
Binnenwand | 05 vijfde verdieping | 2.75 | 2.9 | 0.29 | 0.304 | 3.04 | 0.304
Binnenwand | 06 zesde verdieping | 2.75 | 2.55 | 0.255 | 0.4545 | 4.545 | 0.4545
Binnenwand | 06 zesde verdieping | 2.75 | 2.9 | 0.29 | 0.304 | 3.04 | 0.304
Binnenwand | 07 zevende verdieping | 2.75 | 2.55 | 0.255 | 0.4545 | 4.545 | 0.4545
Binnenwand | 07 zevende verdieping | 2.75 | 2.9 | 0.29 | 0.304 | 3.04 | 0.304
Binnenwand | 08 achtste verdieping | 2.75 | 2.55 | 0.255 | 0.4545 | 4.545 | 0.4545
Binnenwand | 08 achtste verdieping | 2.75 | 2.9 | 0.29 | 0.304 | 3.04 | 0.304
Binnenwand | 02 tweede verdieping | 2.75 | 7.25216 | 0.725216 | 1.7476 | 17.476 | 1.7476
Binnenwand | 02 tweede verdieping | 2.75 | 1.35 | 0.135 | 0.1245 | 1.245 | 0.1245
Binnenwand | 02 tweede verdieping | 2.75 | 0.95 | 0.095 | 0.26125 | 2.6125 | 0.26125
2 x Binnenwand | 02 tweede verdieping | 2.75 | 1.40216 | 0.140216 | 0.385595 | 3.85595 | 0.385595
Binnenwand | 02 tweede verdieping | 2.75 | 2.45 | 0.245 | 0.427 | 4.27 | 0.427
Binnenwand | 02 tweede verdieping | 2.75 | 3 | 0.3 | 0.57825 | 5.7825 | 0.57825
Binnenwand | 02 tweede verdieping | 2.75 | 4.65 | 0.465 | 1.27875 | 12.7875 | 1.27875
2 x Binnenwand | 02 tweede verdieping | 2.75 | 2.6 | 0.26 | 0.46825 | 4.6825 | 0.46825
2 x Binnenwand | 02 tweede verdieping | 2.75 | 3.85 | 0.385 | 0.812 | 8.12 | 0.812
Binnenwand | 03 derde verdieping | 2.75 | 7.25216 | 0.725216 | 1.7476 | 17.476 | 1.7476
Binnenwand | 03 derde verdieping | 2.75 | 1.35 | 0.135 | 0.1245 | 1.245 | 0.1245
Binnenwand | 03 derde verdieping | 2.75 | 0.95 | 0.095 | 0.26125 | 2.6125 | 0.26125
2 x Binnenwand | 03 derde verdieping | 2.75 | 1.40216 | 0.140216 | 0.385595 | 3.85595 | 0.385595
Binnenwand | 03 derde verdieping | 2.75 | 2.45 | 0.245 | 0.427 | 4.27 | 0.427
Binnenwand | 03 derde verdieping | 2.75 | 3 | 0.3 | 0.57825 | 5.7825 | 0.57825
Binnenwand | 03 derde verdieping | 2.75 | 4.65 | 0.465 | 1.27875 | 12.7875 | 1.27875
2 x Binnenwand | 03 derde verdieping | 2.75 | 2.6 | 0.26 | 0.46825 | 4.6825 | 0.46825
2 x Binnenwand | 03 derde verdieping | 2.75 | 3.85 | 0.385 | 0.812 | 8.12 | 0.812
Binnenwand | 04 vierde verdieping | 2.75 | 7.25216 | 0.725216 | 1.7476 | 17.476 | 1.7476
Binnenwand | 04 vierde verdieping | 2.75 | 1.35 | 0.135 | 0.1245 | 1.245 | 0.1245
Binnenwand | 04 vierde verdieping | 2.75 | 0.95 | 0.095 | 0.26125 | 2.6125 | 0.26125
2 x Binnenwand | 04 vierde verdieping | 2.75 | 1.40216 | 0.140216 | 0.385595 | 3.85595 | 0.385595
Binnenwand | 04 vierde verdieping | 2.75 | 2.45 | 0.245 | 0.427 | 4.27 | 0.427
Binnenwand | 04 vierde verdieping | 2.75 | 3 | 0.3 | 0.57825 | 5.7825 | 0.57825
Binnenwand | 04 vierde verdieping | 2.75 | 4.65 | 0.465 | 1.27875 | 12.7875 | 1.27875
2 x Binnenwand | 04 vierde verdieping | 2.75 | 2.6 | 0.26 | 0.46825 | 4.6825 | 0.46825
2 x Binnenwand | 04 vierde verdieping | 2.75 | 3.85 | 0.385 | 0.812 | 8.12 | 0.812
Binnenwand | 05 vijfde verdieping | 2.75 | 7.25216 | 0.725216 | 1.7476 | 17.476 | 1.7476
Binnenwand | 05 vijfde verdieping | 2.75 | 1.35 | 0.135 | 0.1245 | 1.245 | 0.1245
Binnenwand | 05 vijfde verdieping | 2.75 | 0.95 | 0.095 | 0.26125 | 2.6125 | 0.26125
2 x Binnenwand | 05 vijfde verdieping | 2.75 | 1.40216 | 0.140216 | 0.385595 | 3.85595 | 0.385595
Binnenwand | 05 vijfde verdieping | 2.75 | 2.45 | 0.245 | 0.427 | 4.27 | 0.427
Binnenwand | 05 vijfde verdieping | 2.75 | 3 | 0.3 | 0.57825 | 5.7825 | 0.57825
Binnenwand | 05 vijfde verdieping | 2.75 | 4.65 | 0.465 | 1.27875 | 12.7875 | 1.27875
2 x Binnenwand | 05 vijfde verdieping | 2.75 | 2.6 | 0.26 | 0.46825 | 4.6825 | 0.46825
2 x Binnenwand | 05 vijfde verdieping | 2.75 | 3.85 | 0.385 | 0.812 | 8.12 | 0.812
Binnenwand | 06 zesde verdieping | 2.75 | 7.25216 | 0.725216 | 1.7476 | 17.476 | 1.7476
Binnenwand | 06 zesde verdieping | 2.75 | 1.35 | 0.135 | 0.1245 | 1.245 | 0.1245
Binnenwand | 06 zesde verdieping | 2.75 | 0.95 | 0.095 | 0.26125 | 2.6125 | 0.26125
2 x Binnenwand | 06 zesde verdieping | 2.75 | 1.40216 | 0.140216 | 0.385595 | 3.85595 | 0.385595
Binnenwand | 06 zesde verdieping | 2.75 | 2.45 | 0.245 | 0.427 | 4.27 | 0.427
Binnenwand | 06 zesde verdieping | 2.75 | 3 | 0.3 | 0.57825 | 5.7825 | 0.57825
Binnenwand | 06 zesde verdieping | 2.75 | 4.65 | 0.465 | 1.27875 | 12.7875 | 1.27875
2 x Binnenwand | 06 zesde verdieping | 2.75 | 2.6 | 0.26 | 0.46825 | 4.6825 | 0.46825
2 x Binnenwand | 06 zesde verdieping | 2.75 | 3.85 | 0.385 | 0.812 | 8.12 | 0.812
Binnenwand | 07 zevende verdieping | 2.75 | 7.25216 | 0.725216 | 1.7476 | 17.476 | 1.7476
Binnenwand | 07 zevende verdieping | 2.75 | 1.35 | 0.135 | 0.1245 | 1.245 | 0.1245
Binnenwand | 07 zevende verdieping | 2.75 | 0.95 | 0.095 | 0.26125 | 2.6125 | 0.26125
2 x Binnenwand | 07 zevende verdieping | 2.75 | 1.40216 | 0.140216 | 0.385595 | 3.85595 | 0.385595
Binnenwand | 07 zevende verdieping | 2.75 | 2.45 | 0.245 | 0.427 | 4.27 | 0.427
Binnenwand | 07 zevende verdieping | 2.75 | 3 | 0.3 | 0.57825 | 5.7825 | 0.57825
Binnenwand | 07 zevende verdieping | 2.75 | 4.65 | 0.465 | 1.27875 | 12.7875 | 1.27875
2 x Binnenwand | 07 zevende verdieping | 2.75 | 2.6 | 0.26 | 0.46825 | 4.6825 | 0.46825
2 x Binnenwand | 07 zevende verdieping | 2.75 | 3.85 | 0.385 | 0.812 | 8.12 | 0.812
Binnenwand | 08 achtste verdieping | 2.75 | 7.25216 | 0.725216 | 1.7476 | 17.476 | 1.7476
Binnenwand | 08 achtste verdieping | 2.75 | 1.35 | 0.135 | 0.1245 | 1.245 | 0.1245
Binnenwand | 08 achtste verdieping | 2.75 | 0.95 | 0.095 | 0.26125 | 2.6125 | 0.26125
2 x Binnenwand | 08 achtste verdieping | 2.75 | 1.40216 | 0.140216 | 0.385595 | 3.85595 | 0.385595
Binnenwand | 08 achtste verdieping | 2.75 | 2.45 | 0.245 | 0.427 | 4.27 | 0.427
Binnenwand | 08 achtste verdieping | 2.75 | 3 | 0.3 | 0.57825 | 5.7825 | 0.57825
Binnenwand | 08 achtste verdieping | 2.75 | 4.65 | 0.465 | 1.27875 | 12.7875 | 1.27875
2 x Binnenwand | 08 achtste verdieping | 2.75 | 2.6 | 0.26 | 0.46825 | 4.6825 | 0.46825
2 x Binnenwand | 08 achtste verdieping | 2.75 | 3.85 | 0.385 | 0.812 | 8.12 | 0.812
2 x Binnenwand | 02 tweede verdieping | 2.75 | 2.7 | 0.27 | 0.249 | 2.49 | 0.249
Binnenwand | 02 tweede verdieping | 2.75 | 2.9 | 0.29 | 0.55075 | 5.5075 | 0.55075
2 x Binnenwand | 03 derde verdieping | 2.75 | 2.7 | 0.27 | 0.249 | 2.49 | 0.249
Binnenwand | 03 derde verdieping | 2.75 | 2.9 | 0.29 | 0.55075 | 5.5075 | 0.55075
2 x Binnenwand | 04 vierde verdieping | 2.75 | 2.7 | 0.27 | 0.249 | 2.49 | 0.249
Binnenwand | 04 vierde verdieping | 2.75 | 2.9 | 0.29 | 0.55075 | 5.5075 | 0.55075
2 x Binnenwand | 05 vijfde verdieping | 2.75 | 2.7 | 0.27 | 0.249 | 2.49 | 0.249
Binnenwand | 05 vijfde verdieping | 2.75 | 2.9 | 0.29 | 0.55075 | 5.5075 | 0.55075
2 x Binnenwand | 06 zesde verdieping | 2.75 | 2.7 | 0.27 | 0.249 | 2.49 | 0.249
Binnenwand | 06 zesde verdieping | 2.75 | 2.9 | 0.29 | 0.55075 | 5.5075 | 0.55075
2 x Binnenwand | 07 zevende verdieping | 2.75 | 2.7 | 0.27 | 0.249 | 2.49 | 0.249
Binnenwand | 07 zevende verdieping | 2.75 | 2.9 | 0.29 | 0.55075 | 5.5075 | 0.55075
2 x Binnenwand | 08 achtste verdieping | 2.75 | 2.7 | 0.27 | 0.249 | 2.49 | 0.249
Binnenwand | 08 achtste verdieping | 2.75 | 2.9 | 0.29 | 0.55075 | 5.5075 | 0.55075
Binnenwand | 02 tweede verdieping | 2.75 | 7.25216 | 0.725216 | 1.50085 | 15.0085 | 1.50085
Binnenwand | 02 tweede verdieping | 2.75 | 5.55 | 0.555 | 1.03275 | 10.3275 | 1.03275
Binnenwand | 02 tweede verdieping | 2.75 | 4.55 | 0.455 | 1.25125 | 12.5125 | 1.25125
Binnenwand | 02 tweede verdieping | 2.75 | 1.325 | 0.1325 | 0.364375 | 3.64375 | 0.364375
Binnenwand | 03 derde verdieping | 2.75 | 7.25216 | 0.725216 | 1.50085 | 15.0085 | 1.50085
Binnenwand | 03 derde verdieping | 2.75 | 5.55 | 0.555 | 1.03275 | 10.3275 | 1.03275
Binnenwand | 03 derde verdieping | 2.75 | 4.55 | 0.455 | 1.25125 | 12.5125 | 1.25125
Binnenwand | 03 derde verdieping | 2.75 | 1.325 | 0.1325 | 0.364375 | 3.64375 | 0.364375
Binnenwand | 04 vierde verdieping | 2.75 | 7.25216 | 0.725216 | 1.50085 | 15.0085 | 1.50085
Binnenwand | 04 vierde verdieping | 2.75 | 5.55 | 0.555 | 1.03275 | 10.3275 | 1.03275
Binnenwand | 04 vierde verdieping | 2.75 | 4.55 | 0.455 | 1.25125 | 12.5125 | 1.25125
Binnenwand | 04 vierde verdieping | 2.75 | 1.325 | 0.1325 | 0.364375 | 3.64375 | 0.364375
Binnenwand | 05 vijfde verdieping | 2.75 | 7.25216 | 0.725216 | 1.50085 | 15.0085 | 1.50085
Binnenwand | 05 vijfde verdieping | 2.75 | 5.55 | 0.555 | 1.03275 | 10.3275 | 1.03275
Binnenwand | 05 vijfde verdieping | 2.75 | 4.55 | 0.455 | 1.25125 | 12.5125 | 1.25125
Binnenwand | 05 vijfde verdieping | 2.75 | 1.325 | 0.1325 | 0.364375 | 3.64375 | 0.364375
Binnenwand | 06 zesde verdieping | 2.75 | 7.25216 | 0.725216 | 1.50085 | 15.0085 | 1.50085
Binnenwand | 06 zesde verdieping | 2.75 | 5.55 | 0.555 | 1.03275 | 10.3275 | 1.03275
Binnenwand | 06 zesde verdieping | 2.75 | 4.55 | 0.455 | 1.25125 | 12.5125 | 1.25125
Binnenwand | 06 zesde verdieping | 2.75 | 1.325 | 0.1325 | 0.364375 | 3.64375 | 0.364375
Binnenwand | 07 zevende verdieping | 2.75 | 7.25216 | 0.725216 | 1.50085 | 15.0085 | 1.50085
Binnenwand | 07 zevende verdieping | 2.75 | 5.55 | 0.555 | 1.03275 | 10.3275 | 1.03275
Binnenwand | 07 zevende verdieping | 2.75 | 4.55 | 0.455 | 1.25125 | 12.5125 | 1.25125
Binnenwand | 07 zevende verdieping | 2.75 | 1.325 | 0.1325 | 0.364375 | 3.64375 | 0.364375
Binnenwand | 08 achtste verdieping | 2.75 | 7.25216 | 0.725216 | 1.50085 | 15.0085 | 1.50085
Binnenwand | 08 achtste verdieping | 2.75 | 5.55 | 0.555 | 1.03275 | 10.3275 | 1.03275
Binnenwand | 08 achtste verdieping | 2.75 | 4.55 | 0.455 | 1.25125 | 12.5125 | 1.25125
Binnenwand | 08 achtste verdieping | 2.75 | 1.325 | 0.1325 | 0.364375 | 3.64375 | 0.364375
8 x Binnenwand | 01 eerste verdieping | 2.75 | 2.85 | 0.285 | 0.78375 | 7.8375 | 0.78375
4 x Binnenwand | 01 eerste verdieping | 2.75 | 5.75 | 0.575 | 1.08775 | 10.8775 | 1.08775
8 x Binnenwand | 01 eerste verdieping | 2.75 | 2.6 | 0.26 | 0.46825 | 4.6825 | 0.46825
2 x Binnenwand | 01 eerste verdieping | 2.75 | 1.45 | 0.145 | 0.39875 | 3.9875 | 0.39875
2 x Binnenwand | 01 eerste verdieping | 2.75 | 1.25 | 0.125 | 0.34375 | 3.4375 | 0.34375
2 x Binnenwand | 01 eerste verdieping | 2.75 | 1.325 | 0.1325 | 0.364375 | 3.64375 | 0.364375
4 x Binnenwand | 01 eerste verdieping | 2.75 | 1.50216 | 0.150216 | 0.166345 | 1.66345 | 0.166345
4 x Binnenwand | 01 eerste verdieping | 2.75 | 3.5 | 0.35 | 0.71575 | 7.1575 | 0.71575
8 x Binnenwand | 01 eerste verdieping | 2.75 | 0.35 | 0.035 | 0.09625 | 0.9625 | 0.09625
4 x Binnenwand | 01 eerste verdieping | 2.75 | 0.5 | 0.05 | 0.1375 | 1.375 | 0.1375
2 x Binnenwand | 01 eerste verdieping | 2.75 | 1.35 | 0.135 | 0.37125 | 3.7125 | 0.37125
2 x Binnenwand | 01 eerste verdieping | 2.75 | 1.4 | 0.14 | 0.385 | 3.85 | 0.385
Binnenwand | 01 eerste verdieping | 2.75 | 0.902164 | 0.0902164 | 0.248095 | 2.48095 | 0.248095
Binnenwand | 01 eerste verdieping | 2.75 | 0.4 | 0.04 | 0.11 | 1.1 | 0.11

# IfcWall: Basic Wall:22_WA_afbouw_binnenwand 200mm_gen (2)
In: 08 achtste verdieping
Type - PredefinedType: STANDARD
Type - Pset_ReinforcementBarPitchOfWall - Description: Binnenwand
Type - Pset_WallCommon - LoadBearing: no
Classification: 22.10 binnenwanden; niet constructief, algemeen (verzamelniveau) (NL-SfB); Material: ntb_ntb_ntb
Qto_WallBaseQuantities - Height: 2.75 m; Length: 1.2 m; Width: 0.2 m; GrossFootprintArea: 0.24 m2; GrossVolume: 0.66 m3; GrossSideArea: 3.3 m2; NetSideArea: 3.3 m2; NetVolume: 0.66 m3
Pset_EnvironmentalImpactIndicators - Reference: 22_WA_afbouw_binnenwand 200mm_gen; sets with these values: 2
Pset_WallCommon - IsExternal: no; ExtendToStructure: no; Reference: 22_WA_afbouw_binnenwand 200mm_gen

# IfcWall: Basic Wall:22_WA_afbouw_binnenwand 250mm_gen (110)
Type - PredefinedType: STANDARD
Type - Pset_ReinforcementBarPitchOfWall - Description: Binnenwand
Type - Pset_WallCommon - LoadBearing: no
Classification: 22.10 binnenwanden; niet constructief, algemeen (verzamelniveau) (NL-SfB); Material: ntb_ntb_ntb
Qto_WallBaseQuantities - Width: 0.25 m
Pset_EnvironmentalImpactIndicators - Reference: 22_WA_afbouw_binnenwand 250mm_gen; sets with these values: 2
Pset_WallCommon - IsExternal: no; ExtendToStructure: no; Reference: 22_WA_afbouw_binnenwand 250mm_gen
Name | In | Height (m) | Length (m) | GrossFootprintArea (m2) | GrossVolume (m3) | GrossSideArea (m2) = NetSideArea (m2) | NetVolume (m3)
Binnenwand | 01 eerste verdieping | 2.75 | 2.8 | 0.7 | 1.925 | 7.7 | 1.925
2 x Binnenwand | 01 eerste verdieping | 2.75 | 1.815 | 0.45375 | 0.630938 | 2.52375 | 0.630938
2 x Binnenwand | 01 eerste verdieping | 2.75 | 3.075 | 0.76875 | 1.49719 | 5.98875 | 1.49719
8 x Binnenwand | 01 eerste verdieping | 2.75 | 7.25 | 1.8125 | 4.98437 | 19.9375 | 4.98437
Binnenwand | 02 tweede verdieping | 2.75 | 2.8 | 0.7 | 1.925 | 7.7 | 1.925
2 x Binnenwand | 02 tweede verdieping | 2.75 | 1.815 | 0.45375 | 0.630938 | 2.52375 | 0.630938
2 x Binnenwand | 02 tweede verdieping | 2.75 | 3.075 | 0.76875 | 1.49719 | 5.98875 | 1.49719
4 x Binnenwand | 02 tweede verdieping | 2.75 | 7.25 | 1.8125 | 4.98437 | 19.9375 | 4.98437
Binnenwand | 03 derde verdieping | 2.75 | 2.8 | 0.7 | 1.925 | 7.7 | 1.925
2 x Binnenwand | 03 derde verdieping | 2.75 | 1.815 | 0.45375 | 0.630938 | 2.52375 | 0.630938
2 x Binnenwand | 03 derde verdieping | 2.75 | 3.075 | 0.76875 | 1.49719 | 5.98875 | 1.49719
4 x Binnenwand | 03 derde verdieping | 2.75 | 7.25 | 1.8125 | 4.98437 | 19.9375 | 4.98437
Binnenwand | 04 vierde verdieping | 2.75 | 2.8 | 0.7 | 1.925 | 7.7 | 1.925
2 x Binnenwand | 04 vierde verdieping | 2.75 | 1.815 | 0.45375 | 0.630938 | 2.52375 | 0.630938
2 x Binnenwand | 04 vierde verdieping | 2.75 | 3.075 | 0.76875 | 1.49719 | 5.98875 | 1.49719
4 x Binnenwand | 04 vierde verdieping | 2.75 | 7.25 | 1.8125 | 4.98437 | 19.9375 | 4.98437
Binnenwand | 05 vijfde verdieping | 2.75 | 2.8 | 0.7 | 1.925 | 7.7 | 1.925
2 x Binnenwand | 05 vijfde verdieping | 2.75 | 1.815 | 0.45375 | 0.630938 | 2.52375 | 0.630938
2 x Binnenwand | 05 vijfde verdieping | 2.75 | 3.075 | 0.76875 | 1.49719 | 5.98875 | 1.49719
4 x Binnenwand | 05 vijfde verdieping | 2.75 | 7.25 | 1.8125 | 4.98437 | 19.9375 | 4.98437
Binnenwand | 06 zesde verdieping | 2.75 | 2.8 | 0.7 | 1.925 | 7.7 | 1.925
Binnenwand | 06 zesde verdieping | 2.75 | 1.815 | 0.45375 | 0.630938 | 2.52375 | 0.630938
2 x Binnenwand | 06 zesde verdieping | 2.75 | 3.075 | 0.76875 | 1.49719 | 5.98875 | 1.49719
4 x Binnenwand | 06 zesde verdieping | 2.75 | 7.25 | 1.8125 | 4.98437 | 19.9375 | 4.98437
2 x Binnenwand | 01 eerste verdieping | 2.75 | 4.5 | 1.125 | 3.09375 | 12.375 | 3.09375
Binnenwand | 01 eerste verdieping | 2.75 | 2.7 | 0.675 | 1.85625 | 7.425 | 1.85625
2 x Binnenwand | 02 tweede verdieping | 2.75 | 6.675 | 1.66875 | 4.58906 | 18.3562 | 4.58906
Binnenwand | 02 tweede verdieping | 2.75 | 2.7 | 0.675 | 1.85625 | 7.425 | 1.85625
2 x Binnenwand | 03 derde verdieping | 2.75 | 6.675 | 1.66875 | 4.58906 | 18.3562 | 4.58906
Binnenwand | 03 derde verdieping | 2.75 | 2.7 | 0.675 | 1.85625 | 7.425 | 1.85625
2 x Binnenwand | 04 vierde verdieping | 2.75 | 6.675 | 1.66875 | 4.58906 | 18.3562 | 4.58906
Binnenwand | 04 vierde verdieping | 2.75 | 2.7 | 0.675 | 1.85625 | 7.425 | 1.85625
2 x Binnenwand | 05 vijfde verdieping | 2.75 | 6.675 | 1.66875 | 4.58906 | 18.3562 | 4.58906
Binnenwand | 05 vijfde verdieping | 2.75 | 2.7 | 0.675 | 1.85625 | 7.425 | 1.85625
2 x Binnenwand | 06 zesde verdieping | 2.75 | 6.675 | 1.66875 | 4.58906 | 18.3562 | 4.58906
Binnenwand | 06 zesde verdieping | 2.75 | 1.815 | 0.45375 | 0.630938 | 2.52375 | 0.630937
Binnenwand | 06 zesde verdieping | 2.75 | 2.7 | 0.675 | 1.85625 | 7.425 | 1.85625
Binnenwand | 00 begane grond | 3.65 | 7.25 | 1.8125 | 5.99875 | 23.995 | 5.99875
9 x Binnenwand | 00 begane grond | 3.65 | 7.25 | 1.8125 | 6.61562 | 26.4625 | 6.61562
Binnenwand | 07 zevende verdieping | 2.75 | 2.8 | 0.7 | 1.925 | 7.7 | 1.925
Binnenwand | 07 zevende verdieping | 2.75 | 1.815 | 0.45375 | 0.630938 | 2.52375 | 0.630938
2 x Binnenwand | 07 zevende verdieping | 2.75 | 3.075 | 0.76875 | 1.49719 | 5.98875 | 1.49719
4 x Binnenwand | 07 zevende verdieping | 2.75 | 7.25 | 1.8125 | 4.98437 | 19.9375 | 4.98437
2 x Binnenwand | 07 zevende verdieping | 2.75 | 6.675 | 1.66875 | 4.58906 | 18.3562 | 4.58906
Binnenwand | 07 zevende verdieping | 2.75 | 1.815 | 0.45375 | 0.630938 | 2.52375 | 0.630937
Binnenwand | 07 zevende verdieping | 2.75 | 2.7 | 0.675 | 1.85625 | 7.425 | 1.85625
Binnenwand | 08 achtste verdieping | 2.75 | 2.8 | 0.7 | 1.925 | 7.7 | 1.925
Binnenwand | 08 achtste verdieping | 2.75 | 1.815 | 0.45375 | 0.630938 | 2.52375 | 0.630938
2 x Binnenwand | 08 achtste verdieping | 2.75 | 3.075 | 0.76875 | 1.49719 | 5.98875 | 1.49719
4 x Binnenwand | 08 achtste verdieping | 2.75 | 7.25 | 1.8125 | 4.98437 | 19.9375 | 4.98437
2 x Binnenwand | 08 achtste verdieping | 2.75 | 6.675 | 1.66875 | 4.58906 | 18.3562 | 4.58906
Binnenwand | 08 achtste verdieping | 2.75 | 1.815 | 0.45375 | 0.630938 | 2.52375 | 0.630937
Binnenwand | 08 achtste verdieping | 2.75 | 2.7 | 0.675 | 1.85625 | 7.425 | 1.85625

# IfcWall: Basic Wall:28_WA_skelet_wand 200mm_gen (50)
Type - PredefinedType: STANDARD
Type - Pset_ReinforcementBarPitchOfWall - Description: Constructieve wand
Type - Pset_WallCommon - LoadBearing: yes
Classification: 28.20 hoofddraagconstructies; wanden en vloeren, algemeen (verzamelniveau) (NL-SfB); Material: beton_gewapend_prefab-element
Qto_WallBaseQuantities - Width: 0.2 m
Pset_EnvironmentalImpactIndicators - Reference: 28_WA_skelet_wand 200mm_gen; sets with these values: 2
Pset_WallCommon - IsExternal: no; LoadBearing: no; ExtendToStructure: no; Reference: 28_WA_skelet_wand 200mm_gen
Name | In | Height (m) | Length (m) | GrossFootprintArea (m2) | GrossVolume (m3) = NetVolume (m3) | GrossSideArea (m2) = NetSideArea (m2)
Constructieve wand | 01 eerste verdieping | 2.75 | 2.95 | 0.59 | 1.6225 | 8.1125
Constructieve wand | 01 eerste verdieping | 2.75 | 3.7 | 0.74 | 1.075 | 5.375
Constructieve wand | 01 eerste verdieping | 2.75 | 2.75 | 0.55 | 1.5125 | 7.5625
2 x Constructieve wand | 01 eerste verdieping | 2.75 | 3.52 | 0.704 | 1.936 | 9.68
Constructieve wand | 02 tweede verdieping | 2.75 | 2.95 | 0.59 | 1.6225 | 8.1125
Constructieve wand | 02 tweede verdieping | 2.75 | 3.7 | 0.74 | 1.075 | 5.375
Constructieve wand | 02 tweede verdieping | 2.75 | 2.75 | 0.55 | 1.5125 | 7.5625
2 x Constructieve wand | 02 tweede verdieping | 2.75 | 3.52 | 0.704 | 1.936 | 9.68
Constructieve wand | 03 derde verdieping | 2.75 | 2.95 | 0.59 | 1.6225 | 8.1125
Constructieve wand | 03 derde verdieping | 2.75 | 3.7 | 0.74 | 1.075 | 5.375
Constructieve wand | 03 derde verdieping | 2.75 | 2.75 | 0.55 | 1.5125 | 7.5625
2 x Constructieve wand | 03 derde verdieping | 2.75 | 3.52 | 0.704 | 1.936 | 9.68
Constructieve wand | 04 vierde verdieping | 2.75 | 2.95 | 0.59 | 1.6225 | 8.1125
Constructieve wand | 04 vierde verdieping | 2.75 | 3.7 | 0.74 | 1.075 | 5.375
Constructieve wand | 04 vierde verdieping | 2.75 | 2.75 | 0.55 | 1.5125 | 7.5625
2 x Constructieve wand | 04 vierde verdieping | 2.75 | 3.52 | 0.704 | 1.936 | 9.68
Constructieve wand | 05 vijfde verdieping | 2.75 | 2.95 | 0.59 | 1.6225 | 8.1125
Constructieve wand | 05 vijfde verdieping | 2.75 | 3.7 | 0.74 | 1.075 | 5.375
Constructieve wand | 05 vijfde verdieping | 2.75 | 2.75 | 0.55 | 1.5125 | 7.5625
2 x Constructieve wand | 05 vijfde verdieping | 2.75 | 3.52 | 0.704 | 1.936 | 9.68
Constructieve wand | 06 zesde verdieping | 2.75 | 2.95 | 0.59 | 1.6225 | 8.1125
Constructieve wand | 06 zesde verdieping | 2.75 | 3.7 | 0.74 | 1.075 | 5.375
Constructieve wand | 06 zesde verdieping | 2.75 | 2.75 | 0.55 | 1.5125 | 7.5625
2 x Constructieve wand | 06 zesde verdieping | 2.75 | 3.52 | 0.704 | 1.936 | 9.68
2 x Constructieve wand | -1 kelder | 2.95 | 2.75 | 0.55 | 1.6225 | 8.1125
Constructieve wand | -1 kelder | 2.95 | 10.05 | 2.01 | 3.9825 | 19.9125
2 x Constructieve wand | -1 kelder | 2.95 | 3.96 | 0.792 | 2.3364 | 11.682
Constructieve wand | 00 begane grond | 3.65 | 2.95 | 0.59 | 2.1535 | 10.7675
Constructieve wand | 00 begane grond | 3.65 | 3.7 | 0.74 | 2.701 | 13.505
Constructieve wand | 00 begane grond | 3.65 | 2.75 | 0.55 | 2.0075 | 10.0375
2 x Constructieve wand | 00 begane grond | 3.65 | 6.12 | 1.224 | 4.4676 | 22.338
Constructieve wand | 07 zevende verdieping | 2.75 | 2.95 | 0.59 | 1.6225 | 8.1125
Constructieve wand | 07 zevende verdieping | 2.75 | 3.7 | 0.74 | 1.075 | 5.375
Constructieve wand | 07 zevende verdieping | 2.75 | 2.75 | 0.55 | 1.5125 | 7.5625
2 x Constructieve wand | 07 zevende verdieping | 2.75 | 3.52 | 0.704 | 1.936 | 9.68
Constructieve wand | 08 achtste verdieping | 2.75 | 2.95 | 0.59 | 1.6225 | 8.1125
Constructieve wand | 08 achtste verdieping | 2.75 | 3.7 | 0.74 | 1.075 | 5.375
Constructieve wand | 08 achtste verdieping | 2.75 | 2.75 | 0.55 | 1.5125 | 7.5625
2 x Constructieve wand | 08 achtste verdieping | 2.75 | 3.52 | 0.704 | 1.936 | 9.68

# IfcWall: Basic Wall:28_WA_skelet_wand 250mm_gen (63)
Type - PredefinedType: STANDARD
Type - Pset_ReinforcementBarPitchOfWall - Description: Constructieve wand
Type - Pset_WallCommon - LoadBearing: yes
Classification: 28.20 hoofddraagconstructies; wanden en vloeren, algemeen (verzamelniveau) (NL-SfB); Material: beton_gewapend_ihw
Qto_WallBaseQuantities - Width: 0.25 m
Pset_EnvironmentalImpactIndicators - Reference: 28_WA_skelet_wand 250mm_gen; sets with these values: 2
Pset_WallCommon - IsExternal: no; Reference: 28_WA_skelet_wand 250mm_gen; LoadBearing: no; ExtendToStructure: no
Name | In | Height (m) | Length (m) | GrossFootprintArea (m2) | GrossVolume (m3) | GrossSideArea (m2) = NetSideArea (m2) | NetVolume (m3)
2 x Constructieve wand | 01 eerste verdieping | 2.75 | 33.35 | 8.3375 | 18.5481 | 74.1925 | 18.5481
4 x Constructieve wand | 01 eerste verdieping | 2.75 | 10.8 | 2.7 | 7.425 | 29.7 | 7.425
2 x Constructieve wand | 01 eerste verdieping | 2.75 | 7.25 | 1.8125 | 4.98438 | 19.9375 | 4.98438
2 x Constructieve wand | 02 tweede verdieping | 2.75 | 24.1 | 6.025 | 16.5688 | 66.275 | 16.5688
2 x Constructieve wand | 02 tweede verdieping | 2.75 | 24.1 | 6.025 | 14.5719 | 58.2875 | 14.5719
Constructieve wand | 02 tweede verdieping | 2.75 | 7.25 | 1.8125 | 3.6475 | 14.59 | 3.6475
2 x Constructieve wand | 03 derde verdieping | 2.75 | 24.1 | 6.025 | 16.5688 | 66.275 | 16.5688
2 x Constructieve wand | 03 derde verdieping | 2.75 | 24.1 | 6.025 | 14.5719 | 58.2875 | 14.5719
Constructieve wand | 03 derde verdieping | 2.75 | 7.25 | 1.8125 | 3.6475 | 14.59 | 3.6475
2 x Constructieve wand | 04 vierde verdieping | 2.75 | 24.1 | 6.025 | 16.5688 | 66.275 | 16.5688
2 x Constructieve wand | 04 vierde verdieping | 2.75 | 24.1 | 6.025 | 14.5719 | 58.2875 | 14.5719
Constructieve wand | 04 vierde verdieping | 2.75 | 7.25 | 1.8125 | 3.6475 | 14.59 | 3.6475
2 x Constructieve wand | 05 vijfde verdieping | 2.75 | 24.1 | 6.025 | 16.5688 | 66.275 | 16.5688
2 x Constructieve wand | 05 vijfde verdieping | 2.75 | 24.1 | 6.025 | 14.5719 | 58.2875 | 14.5719
Constructieve wand | 05 vijfde verdieping | 2.75 | 7.25 | 1.8125 | 3.6475 | 14.59 | 3.6475
2 x Constructieve wand | 06 zesde verdieping | 2.75 | 24.1 | 6.025 | 16.5688 | 66.275 | 16.5688
2 x Constructieve wand | 06 zesde verdieping | 2.75 | 24.1 | 6.025 | 14.5719 | 58.2875 | 14.5719
Constructieve wand | 06 zesde verdieping | 2.75 | 7.25 | 1.8125 | 3.6475 | 14.59 | 3.6475
Constructieve wand | 02 tweede verdieping | 2.75 | 7.25 | 1.8125 | 3.7075 | 14.83 | 3.7075
Constructieve wand | 03 derde verdieping | 2.75 | 7.25 | 1.8125 | 3.7075 | 14.83 | 3.7075
Constructieve wand | 04 vierde verdieping | 2.75 | 7.25 | 1.8125 | 3.7075 | 14.83 | 3.7075
Constructieve wand | 05 vijfde verdieping | 2.75 | 7.25 | 1.8125 | 3.7075 | 14.83 | 3.7075
Constructieve wand | 06 zesde verdieping | 2.75 | 7.25 | 1.8125 | 3.7075 | 14.83 | 3.7075
Constructieve wand | -1 kelder | 2.95 | 3.05 | 0.7625 | 2.24938 | 8.9975 | 2.24938
Constructieve wand | -1 kelder | 2.95 | 7.75 | 1.9375 | 5.71562 | 22.8625 | 5.71562
2 x Constructieve wand | 00 begane grond | 3.65 | 33.35 | 8.3375 | 28.6606 | 114.642 | 28.6606
2 x Constructieve wand | 00 begane grond | 3.65 | 7.25 | 1.8125 | 6.61562 | 26.4625 | 6.61562
Constructieve wand | 00 begane grond | 3.65 | 33.35 | 8.3375 | 24.9344 | 99.7375 | 24.9344
2 x Constructieve wand | 07 zevende verdieping | 2.75 | 24.1 | 6.025 | 16.5688 | 66.275 | 16.5688
2 x Constructieve wand | 07 zevende verdieping | 2.75 | 24.1 | 6.025 | 14.5719 | 58.2875 | 14.5719
Constructieve wand | 07 zevende verdieping | 2.75 | 7.25 | 1.8125 | 3.6475 | 14.59 | 3.6475
Constructieve wand | 07 zevende verdieping | 2.75 | 7.25 | 1.8125 | 3.7075 | 14.83 | 3.7075
2 x Constructieve wand | 08 achtste verdieping | 2.75 | 24.1 | 6.025 | 16.5688 | 66.275 | 16.5688
2 x Constructieve wand | 08 achtste verdieping | 2.75 | 24.1 | 6.025 | 14.5719 | 58.2875 | 14.5719
Constructieve wand | 08 achtste verdieping | 2.75 | 7.25 | 1.8125 | 3.6475 | 14.59 | 3.6475
Constructieve wand | 08 achtste verdieping | 2.75 | 7.25 | 1.8125 | 3.7075 | 14.83 | 3.7075
Constructieve wand | -1 kelder | 2.95 | 3.2 | 0.8 | 2.36 | 9.44 | 2.36
Constructieve wand | 00 begane grond | 3.65 | 33.35 | 8.3375 | 23.7344 | 94.9375 | 23.7344
Constructieve wand | -1 kelder | 2.95 | 10.05 | 2.5125 | 7.41187 | 29.6475 | 7.41187
2 x Constructieve wand | 01 eerste verdieping | 2.75 | 6.35 | 1.5875 | 4.36562 | 17.4625 | 4.36562
Constructieve wand | -1 kelder | 2.95 | 10.05 | 2.5125 | 7.41188 | 29.6475 | 7.41187

# IfcSpaceType, no part of this type: 01.00.01
PredefinedType: USERDEFINED

# IfcSpaceType, no part of this type: 01.00.01
PredefinedType: USERDEFINED

# IfcSpaceType, no part of this type: 01.00.01
PredefinedType: USERDEFINED

# IfcSpaceType, no part of this type: 01.00.02
PredefinedType: USERDEFINED

# IfcSpaceType, no part of this type: 01.00.02
PredefinedType: USERDEFINED

# IfcSpaceType, no part of this type: 01.00.02
PredefinedType: USERDEFINED

# IfcSpaceType, no part of this type: 01.00.03
PredefinedType: USERDEFINED

# IfcSpaceType, no part of this type: 01.00.03
PredefinedType: USERDEFINED

# IfcSpaceType, no part of this type: 01.00.03
PredefinedType: USERDEFINED

# IfcSpaceType, no part of this type: 01.00.04
PredefinedType: USERDEFINED

# IfcSpaceType, no part of this type: 01.00.04
PredefinedType: USERDEFINED

# IfcSpaceType, no part of this type: 01.00.04
PredefinedType: USERDEFINED

# IfcSpaceType, no part of this type: 01.00.05
PredefinedType: USERDEFINED

# IfcSpaceType, no part of this type: 01.00.05
PredefinedType: USERDEFINED

# IfcSpaceType, no part of this type: 01.00.05
PredefinedType: USERDEFINED

# IfcSpaceType, no part of this type: 01.00.06
PredefinedType: USERDEFINED

# IfcSpaceType, no part of this type: 01.00.06
PredefinedType: USERDEFINED

# IfcSpaceType, no part of this type: 01.00.06
PredefinedType: USERDEFINED

# IfcSpaceType, no part of this type: 01.01.01
PredefinedType: USERDEFINED

# IfcSpaceType, no part of this type: 01.01.01
PredefinedType: USERDEFINED

# IfcSpaceType, no part of this type: 01.01.02
PredefinedType: USERDEFINED

# IfcSpaceType, no part of this type: 01.01.02
PredefinedType: USERDEFINED

# IfcSpaceType, no part of this type: 01.01.03
PredefinedType: USERDEFINED

# IfcSpaceType, no part of this type: 01.01.03
PredefinedType: USERDEFINED

# IfcSpaceType, no part of this type: 01.01.04
PredefinedType: USERDEFINED

# IfcSpaceType, no part of this type: 01.01.04
PredefinedType: USERDEFINED

# IfcSpaceType, no part of this type: 01.02.01
PredefinedType: USERDEFINED

# IfcSpaceType, no part of this type: 01.02.01
PredefinedType: USERDEFINED

# IfcSpaceType, no part of this type: 01.02.01
PredefinedType: USERDEFINED

# IfcSpaceType, no part of this type: 01.02.02
PredefinedType: USERDEFINED

# IfcSpaceType, no part of this type: 01.02.02
PredefinedType: USERDEFINED

# IfcSpaceType, no part of this type: 01.02.02
PredefinedType: USERDEFINED

# IfcSpaceType, no part of this type: 01.02.03
PredefinedType: USERDEFINED

# IfcSpaceType, no part of this type: 01.02.03
PredefinedType: USERDEFINED

# IfcSpaceType, no part of this type: 01.02.04
PredefinedType: USERDEFINED

# IfcSpaceType, no part of this type: 01.02.04
PredefinedType: USERDEFINED

# IfcSpaceType, no part of this type: 01.02.04
PredefinedType: USERDEFINED

# IfcSpaceType, no part of this type: 01.02.05
PredefinedType: USERDEFINED

# IfcSpaceType, no part of this type: 01.02.05
PredefinedType: USERDEFINED

# IfcSpaceType, no part of this type: 01.02.05
PredefinedType: USERDEFINED

# IfcSpaceType, no part of this type: 01.02.06
PredefinedType: USERDEFINED

# IfcSpaceType, no part of this type: 01.02.06
PredefinedType: USERDEFINED

# IfcSpaceType, no part of this type: 01.03.01
PredefinedType: USERDEFINED

# IfcSpaceType, no part of this type: 01.03.01
PredefinedType: USERDEFINED

# IfcSpaceType, no part of this type: 01.03.02
PredefinedType: USERDEFINED

# IfcSpaceType, no part of this type: 01.03.02
PredefinedType: USERDEFINED

# IfcSpaceType, no part of this type: 01.03.03
PredefinedType: USERDEFINED

# IfcSpaceType, no part of this type: 01.03.03
PredefinedType: USERDEFINED

# IfcSpaceType, no part of this type: 01.03.04
PredefinedType: USERDEFINED

# IfcSpaceType, no part of this type: 01.03.04
PredefinedType: USERDEFINED

# IfcSpaceType, no part of this type: 01.03.05
PredefinedType: USERDEFINED

# IfcSpaceType, no part of this type: 01.03.05
PredefinedType: USERDEFINED

# IfcSpaceType, no part of this type: 01.03.06
PredefinedType: USERDEFINED

# IfcSpaceType, no part of this type: 01.03.06
PredefinedType: USERDEFINED

# IfcSpaceType, no part of this type: 01.04.01
PredefinedType: USERDEFINED

# IfcSpaceType, no part of this type: 01.04.01
PredefinedType: USERDEFINED

# IfcSpaceType, no part of this type: 01.04.02
PredefinedType: USERDEFINED

# IfcSpaceType, no part of this type: 01.04.02
PredefinedType: USERDEFINED

# IfcSpaceType, no part of this type: 01.04.03
PredefinedType: USERDEFINED

# IfcSpaceType, no part of this type: 01.04.03
PredefinedType: USERDEFINED

# IfcSpaceType, no part of this type: 01.04.04
PredefinedType: USERDEFINED

# IfcSpaceType, no part of this type: 01.04.04
PredefinedType: USERDEFINED

# IfcSpaceType, no part of this type: 01.04.05
PredefinedType: USERDEFINED

# IfcSpaceType, no part of this type: 01.04.05
PredefinedType: USERDEFINED

# IfcSpaceType, no part of this type: 01.04.06
PredefinedType: USERDEFINED

# IfcSpaceType, no part of this type: 01.04.06
PredefinedType: USERDEFINED

# IfcSpaceType, no part of this type: 01.05.01
PredefinedType: USERDEFINED

# IfcSpaceType, no part of this type: 01.05.01
PredefinedType: USERDEFINED

# IfcSpaceType, no part of this type: 01.05.02
PredefinedType: USERDEFINED

# IfcSpaceType, no part of this type: 01.05.02
PredefinedType: USERDEFINED

# IfcSpaceType, no part of this type: 01.05.03
PredefinedType: USERDEFINED

# IfcSpaceType, no part of this type: 01.05.03
PredefinedType: USERDEFINED

# IfcSpaceType, no part of this type: 01.05.04
PredefinedType: USERDEFINED

# IfcSpaceType, no part of this type: 01.05.04
PredefinedType: USERDEFINED

# IfcSpaceType, no part of this type: 01.05.05
PredefinedType: USERDEFINED

# IfcSpaceType, no part of this type: 01.05.05
PredefinedType: USERDEFINED

# IfcSpaceType, no part of this type: 01.05.06
PredefinedType: USERDEFINED

# IfcSpaceType, no part of this type: 01.05.06
PredefinedType: USERDEFINED

# IfcSpaceType, no part of this type: 01.06.01
PredefinedType: USERDEFINED

# IfcSpaceType, no part of this type: 01.06.01
PredefinedType: USERDEFINED

# IfcSpaceType, no part of this type: 01.06.02
PredefinedType: USERDEFINED

# IfcSpaceType, no part of this type: 01.06.02
PredefinedType: USERDEFINED

# IfcSpaceType, no part of this type: 01.06.03
PredefinedType: USERDEFINED

# IfcSpaceType, no part of this type: 01.06.03
PredefinedType: USERDEFINED

# IfcSpaceType, no part of this type: 01.06.04
PredefinedType: USERDEFINED

# IfcSpaceType, no part of this type: 01.06.04
PredefinedType: USERDEFINED

# IfcSpaceType, no part of this type: 01.06.05
PredefinedType: USERDEFINED

# IfcSpaceType, no part of this type: 01.06.05
PredefinedType: USERDEFINED

# IfcSpaceType, no part of this type: 01.06.06
PredefinedType: USERDEFINED

# IfcSpaceType, no part of this type: 01.06.06
PredefinedType: USERDEFINED

# IfcSpaceType, no part of this type: 01.07.01
PredefinedType: USERDEFINED

# IfcSpaceType, no part of this type: 01.07.01
PredefinedType: USERDEFINED

# IfcSpaceType, no part of this type: 01.07.02
PredefinedType: USERDEFINED

# IfcSpaceType, no part of this type: 01.07.02
PredefinedType: USERDEFINED

# IfcSpaceType, no part of this type: 01.07.03
PredefinedType: USERDEFINED

# IfcSpaceType, no part of this type: 01.07.03
PredefinedType: USERDEFINED

# IfcSpaceType, no part of this type: 01.07.04
PredefinedType: USERDEFINED

# IfcSpaceType, no part of this type: 01.07.04
PredefinedType: USERDEFINED

# IfcSpaceType, no part of this type: 01.07.05
PredefinedType: USERDEFINED

# IfcSpaceType, no part of this type: 01.07.05
PredefinedType: USERDEFINED

# IfcSpaceType, no part of this type: 01.07.06
PredefinedType: USERDEFINED

# IfcSpaceType, no part of this type: 01.07.06
PredefinedType: USERDEFINED

# IfcSpaceType, no part of this type: 01.08.01
PredefinedType: USERDEFINED

# IfcSpaceType, no part of this type: 01.08.01
PredefinedType: USERDEFINED

# IfcSpaceType, no part of this type: 01.08.02
PredefinedType: USERDEFINED

# IfcSpaceType, no part of this type: 01.08.02
PredefinedType: USERDEFINED

# IfcSpaceType, no part of this type: 01.08.03
PredefinedType: USERDEFINED

# IfcSpaceType, no part of this type: 01.08.03
PredefinedType: USERDEFINED

# IfcSpaceType, no part of this type: 01.08.04
PredefinedType: USERDEFINED

# IfcSpaceType, no part of this type: 01.08.04
PredefinedType: USERDEFINED

# IfcSpaceType, no part of this type: 01.08.05
PredefinedType: USERDEFINED

# IfcSpaceType, no part of this type: 01.08.05
PredefinedType: USERDEFINED

# IfcSpaceType, no part of this type: 01.08.06
PredefinedType: USERDEFINED

# IfcSpaceType, no part of this type: 01.08.06
PredefinedType: USERDEFINED

# IfcSpaceType, no part of this type: 02.00.01
PredefinedType: USERDEFINED

# IfcSpaceType, no part of this type: 02.00.01
PredefinedType: USERDEFINED

# IfcSpaceType, no part of this type: 02.00.01
PredefinedType: USERDEFINED

# IfcSpaceType, no part of this type: 02.00.02
PredefinedType: USERDEFINED

# IfcSpaceType, no part of this type: 02.00.02
PredefinedType: USERDEFINED

# IfcSpaceType, no part of this type: 02.00.02
PredefinedType: USERDEFINED

# IfcSpaceType, no part of this type: 02.00.03
PredefinedType: USERDEFINED

# IfcSpaceType, no part of this type: 02.00.03
PredefinedType: USERDEFINED

# IfcSpaceType, no part of this type: 02.00.03
PredefinedType: USERDEFINED

# IfcSpaceType, no part of this type: 02.00.04
PredefinedType: USERDEFINED

# IfcSpaceType, no part of this type: 02.00.04
PredefinedType: USERDEFINED

# IfcSpaceType, no part of this type: 02.00.04
PredefinedType: USERDEFINED

# IfcSpaceType, no part of this type: 02.00.04
PredefinedType: USERDEFINED

# IfcSpaceType, no part of this type: 02.00.04
PredefinedType: USERDEFINED

# IfcSpaceType, no part of this type: 02.00.04
PredefinedType: USERDEFINED

# IfcSpaceType, no part of this type: 02.01.01
PredefinedType: USERDEFINED

# IfcSpaceType, no part of this type: 02.01.01
PredefinedType: USERDEFINED

# IfcSpaceType, no part of this type: 02.01.02
PredefinedType: USERDEFINED

# IfcSpaceType, no part of this type: 02.01.02
PredefinedType: USERDEFINED

# IfcSpaceType, no part of this type: 02.01.03
PredefinedType: USERDEFINED

# IfcSpaceType, no part of this type: 02.01.03
PredefinedType: USERDEFINED

# IfcSpaceType, no part of this type: 02.01.04
PredefinedType: USERDEFINED

# IfcSpaceType, no part of this type: 02.01.04
PredefinedType: USERDEFINED

# IfcSpaceType, no part of this type: 02.02.01
PredefinedType: USERDEFINED

# IfcSpaceType, no part of this type: 02.02.01
PredefinedType: USERDEFINED

# IfcSpaceType, no part of this type: 02.02.02
PredefinedType: USERDEFINED

# IfcSpaceType, no part of this type: 02.02.02
PredefinedType: USERDEFINED

# IfcSpaceType, no part of this type: 02.02.02
PredefinedType: USERDEFINED

# IfcSpaceType, no part of this type: 02.02.03
PredefinedType: USERDEFINED

# IfcSpaceType, no part of this type: 02.02.03
PredefinedType: USERDEFINED

# IfcSpaceType, no part of this type: 02.02.03
PredefinedType: USERDEFINED

# IfcSpaceType, no part of this type: 02.02.04
PredefinedType: USERDEFINED

# IfcSpaceType, no part of this type: 02.02.04
PredefinedType: USERDEFINED

# IfcSpaceType, no part of this type: 02.02.05
PredefinedType: USERDEFINED

# IfcSpaceType, no part of this type: 02.02.05
PredefinedType: USERDEFINED

# IfcSpaceType, no part of this type: 02.02.05
PredefinedType: USERDEFINED

# IfcSpaceType, no part of this type: 02.02.06
PredefinedType: USERDEFINED

# IfcSpaceType, no part of this type: 02.02.06
PredefinedType: USERDEFINED

# IfcSpaceType, no part of this type: 02.02.06
PredefinedType: USERDEFINED

# IfcSpaceType, no part of this type: 02.03.01
PredefinedType: USERDEFINED

# IfcSpaceType, no part of this type: 02.03.01
PredefinedType: USERDEFINED

# IfcSpaceType, no part of this type: 02.03.02
PredefinedType: USERDEFINED

# IfcSpaceType, no part of this type: 02.03.02
PredefinedType: USERDEFINED

# IfcSpaceType, no part of this type: 02.03.03
PredefinedType: USERDEFINED

# IfcSpaceType, no part of this type: 02.03.03
PredefinedType: USERDEFINED

# IfcSpaceType, no part of this type: 02.03.04
PredefinedType: USERDEFINED

# IfcSpaceType, no part of this type: 02.03.04
PredefinedType: USERDEFINED

# IfcSpaceType, no part of this type: 02.03.05
PredefinedType: USERDEFINED

# IfcSpaceType, no part of this type: 02.03.05
PredefinedType: USERDEFINED

# IfcSpaceType, no part of this type: 02.03.06
PredefinedType: USERDEFINED

# IfcSpaceType, no part of this type: 02.03.06
PredefinedType: USERDEFINED

# IfcSpaceType, no part of this type: 02.04.01
PredefinedType: USERDEFINED

# IfcSpaceType, no part of this type: 02.04.01
PredefinedType: USERDEFINED

# IfcSpaceType, no part of this type: 02.04.02
PredefinedType: USERDEFINED

# IfcSpaceType, no part of this type: 02.04.02
PredefinedType: USERDEFINED

# IfcSpaceType, no part of this type: 02.04.03
PredefinedType: USERDEFINED

# IfcSpaceType, no part of this type: 02.04.03
PredefinedType: USERDEFINED

# IfcSpaceType, no part of this type: 02.04.04
PredefinedType: USERDEFINED

# IfcSpaceType, no part of this type: 02.04.04
PredefinedType: USERDEFINED

# IfcSpaceType, no part of this type: 02.04.05
PredefinedType: USERDEFINED

# IfcSpaceType, no part of this type: 02.04.05
PredefinedType: USERDEFINED

# IfcSpaceType, no part of this type: 02.04.06
PredefinedType: USERDEFINED

# IfcSpaceType, no part of this type: 02.04.06
PredefinedType: USERDEFINED

# IfcSpaceType, no part of this type: 02.05.01
PredefinedType: USERDEFINED

# IfcSpaceType, no part of this type: 02.05.01
PredefinedType: USERDEFINED

# IfcSpaceType, no part of this type: 02.05.02
PredefinedType: USERDEFINED

# IfcSpaceType, no part of this type: 02.05.02
PredefinedType: USERDEFINED

# IfcSpaceType, no part of this type: 02.05.03
PredefinedType: USERDEFINED

# IfcSpaceType, no part of this type: 02.05.03
PredefinedType: USERDEFINED

# IfcSpaceType, no part of this type: 02.05.04
PredefinedType: USERDEFINED

# IfcSpaceType, no part of this type: 02.05.04
PredefinedType: USERDEFINED

# IfcSpaceType, no part of this type: 02.05.05
PredefinedType: USERDEFINED

# IfcSpaceType, no part of this type: 02.05.05
PredefinedType: USERDEFINED

# IfcSpaceType, no part of this type: 02.05.06
PredefinedType: USERDEFINED

# IfcSpaceType, no part of this type: 02.05.06
PredefinedType: USERDEFINED

# IfcSpaceType, no part of this type: 02.06.01
PredefinedType: USERDEFINED

# IfcSpaceType, no part of this type: 02.06.01
PredefinedType: USERDEFINED

# IfcSpaceType, no part of this type: 02.06.02
PredefinedType: USERDEFINED

# IfcSpaceType, no part of this type: 02.06.02
PredefinedType: USERDEFINED

# IfcSpaceType, no part of this type: 02.06.03
PredefinedType: USERDEFINED

# IfcSpaceType, no part of this type: 02.06.03
PredefinedType: USERDEFINED

# IfcSpaceType, no part of this type: 02.06.04
PredefinedType: USERDEFINED

# IfcSpaceType, no part of this type: 02.06.04
PredefinedType: USERDEFINED

# IfcSpaceType, no part of this type: 02.06.05
PredefinedType: USERDEFINED

# IfcSpaceType, no part of this type: 02.06.05
PredefinedType: USERDEFINED

# IfcSpaceType, no part of this type: 02.06.06
PredefinedType: USERDEFINED

# IfcSpaceType, no part of this type: 02.06.06
PredefinedType: USERDEFINED

# IfcSpaceType, no part of this type: 02.07.01
PredefinedType: USERDEFINED

# IfcSpaceType, no part of this type: 02.07.01
PredefinedType: USERDEFINED

# IfcSpaceType, no part of this type: 02.07.02
PredefinedType: USERDEFINED

# IfcSpaceType, no part of this type: 02.07.02
PredefinedType: USERDEFINED

# IfcSpaceType, no part of this type: 02.07.03
PredefinedType: USERDEFINED

# IfcSpaceType, no part of this type: 02.07.03
PredefinedType: USERDEFINED

# IfcSpaceType, no part of this type: 02.07.04
PredefinedType: USERDEFINED

# IfcSpaceType, no part of this type: 02.07.04
PredefinedType: USERDEFINED

# IfcSpaceType, no part of this type: 02.07.05
PredefinedType: USERDEFINED

# IfcSpaceType, no part of this type: 02.07.05
PredefinedType: USERDEFINED

# IfcSpaceType, no part of this type: 02.07.06
PredefinedType: USERDEFINED

# IfcSpaceType, no part of this type: 02.07.06
PredefinedType: USERDEFINED

# IfcSpaceType, no part of this type: 02.08.01
PredefinedType: USERDEFINED

# IfcSpaceType, no part of this type: 02.08.01
PredefinedType: USERDEFINED

# IfcSpaceType, no part of this type: 02.08.02
PredefinedType: USERDEFINED

# IfcSpaceType, no part of this type: 02.08.02
PredefinedType: USERDEFINED

# IfcSpaceType, no part of this type: 02.08.03
PredefinedType: USERDEFINED

# IfcSpaceType, no part of this type: 02.08.03
PredefinedType: USERDEFINED

# IfcSpaceType, no part of this type: 02.08.04
PredefinedType: USERDEFINED

# IfcSpaceType, no part of this type: 02.08.04
PredefinedType: USERDEFINED

# IfcSpaceType, no part of this type: 02.08.05
PredefinedType: USERDEFINED

# IfcSpaceType, no part of this type: 02.08.05
PredefinedType: USERDEFINED

# IfcSpaceType, no part of this type: 02.08.06
PredefinedType: USERDEFINED

# IfcSpaceType, no part of this type: 02.08.06
PredefinedType: USERDEFINED

# IfcSpaceType, no part of this type: Area:1709311
PredefinedType: USERDEFINED

# IfcSpaceType, no part of this type: Area:1709314
PredefinedType: USERDEFINED

# IfcSpaceType, no part of this type: Area:1709317
PredefinedType: USERDEFINED

# IfcSpaceType, no part of this type: Area:1709320
PredefinedType: USERDEFINED

# IfcSpaceType, no part of this type: Area:1709323
PredefinedType: USERDEFINED

# IfcSpaceType, no part of this type: Area:1709326
PredefinedType: USERDEFINED

# IfcSpaceType, no part of this type: Area:1709329
PredefinedType: USERDEFINED

# IfcSpaceType, no part of this type: Area:1709332
PredefinedType: USERDEFINED

# IfcSpaceType, no part of this type: Area:1709335
PredefinedType: USERDEFINED

# IfcSpaceType, no part of this type: Area:1709338
PredefinedType: USERDEFINED

# IfcSpaceType, no part of this type: Area:1709341
PredefinedType: USERDEFINED

# IfcSpaceType, no part of this type: Area:1709344
PredefinedType: USERDEFINED

# IfcSpaceType, no part of this type: Area:1709410
PredefinedType: USERDEFINED

# IfcSpaceType, no part of this type: Area:1709412
PredefinedType: USERDEFINED

# IfcSpaceType, no part of this type: Area:1709414
PredefinedType: USERDEFINED

# IfcSpaceType, no part of this type: Area:1709416
PredefinedType: USERDEFINED

# IfcSpaceType, no part of this type: Area:1709418
PredefinedType: USERDEFINED

# IfcSpaceType, no part of this type: Area:1709420
PredefinedType: USERDEFINED

# IfcSpaceType, no part of this type: Area:1709422
PredefinedType: USERDEFINED

# IfcSpaceType, no part of this type: Area:1709424
PredefinedType: USERDEFINED

# IfcSpaceType, no part of this type: Area:1709426
PredefinedType: USERDEFINED

# IfcSpaceType, no part of this type: Area:1709428
PredefinedType: USERDEFINED

# IfcSpaceType, no part of this type: Area:1709430
PredefinedType: USERDEFINED

# IfcSpaceType, no part of this type: Area:1709432
PredefinedType: USERDEFINED

# IfcSpaceType, no part of this type: Area:1710063
PredefinedType: USERDEFINED

# IfcSpaceType, no part of this type: Area:1710065
PredefinedType: USERDEFINED

# IfcSpaceType, no part of this type: Area:1710067
PredefinedType: USERDEFINED

# IfcSpaceType, no part of this type: Area:1710069
PredefinedType: USERDEFINED

# IfcSpaceType, no part of this type: Area:1710071
PredefinedType: USERDEFINED

# IfcSpaceType, no part of this type: Area:1710073
PredefinedType: USERDEFINED

# IfcSpaceType, no part of this type: Area:1710075
PredefinedType: USERDEFINED

# IfcSpaceType, no part of this type: Area:1710077
PredefinedType: USERDEFINED

# IfcSpaceType, no part of this type: Area:1710079
PredefinedType: USERDEFINED

# IfcSpaceType, no part of this type: Area:1710081
PredefinedType: USERDEFINED

# IfcSpaceType, no part of this type: Area:1710083
PredefinedType: USERDEFINED

# IfcSpaceType, no part of this type: Area:1710085
PredefinedType: USERDEFINED

# IfcSpaceType, no part of this type: Area:1710087
PredefinedType: USERDEFINED

# IfcSpaceType, no part of this type: Area:1710089
PredefinedType: USERDEFINED

# IfcSpaceType, no part of this type: Area:1710091
PredefinedType: USERDEFINED

# IfcSpaceType, no part of this type: Area:1710093
PredefinedType: USERDEFINED

# IfcSpaceType, no part of this type: Area:1710095
PredefinedType: USERDEFINED

# IfcSpaceType, no part of this type: Area:1710097
PredefinedType: USERDEFINED

# IfcSpaceType, no part of this type: Area:1710099
PredefinedType: USERDEFINED

# IfcSpaceType, no part of this type: Area:1710101
PredefinedType: USERDEFINED

# IfcSpaceType, no part of this type: Area:1710103
PredefinedType: USERDEFINED

# IfcSpaceType, no part of this type: Area:1710105
PredefinedType: USERDEFINED

# IfcSpaceType, no part of this type: Area:1710107
PredefinedType: USERDEFINED

# IfcSpaceType, no part of this type: Area:1710109
PredefinedType: USERDEFINED

# IfcSpaceType, no part of this type: Area:1710114
PredefinedType: USERDEFINED

# IfcSpaceType, no part of this type: Area:1710116
PredefinedType: USERDEFINED

# IfcSpaceType, no part of this type: Area:1710118
PredefinedType: USERDEFINED

# IfcSpaceType, no part of this type: Area:1710120
PredefinedType: USERDEFINED

# IfcSpaceType, no part of this type: Area:1710122
PredefinedType: USERDEFINED

# IfcSpaceType, no part of this type: Area:1710124
PredefinedType: USERDEFINED

# IfcSpaceType, no part of this type: Area:1710126
PredefinedType: USERDEFINED
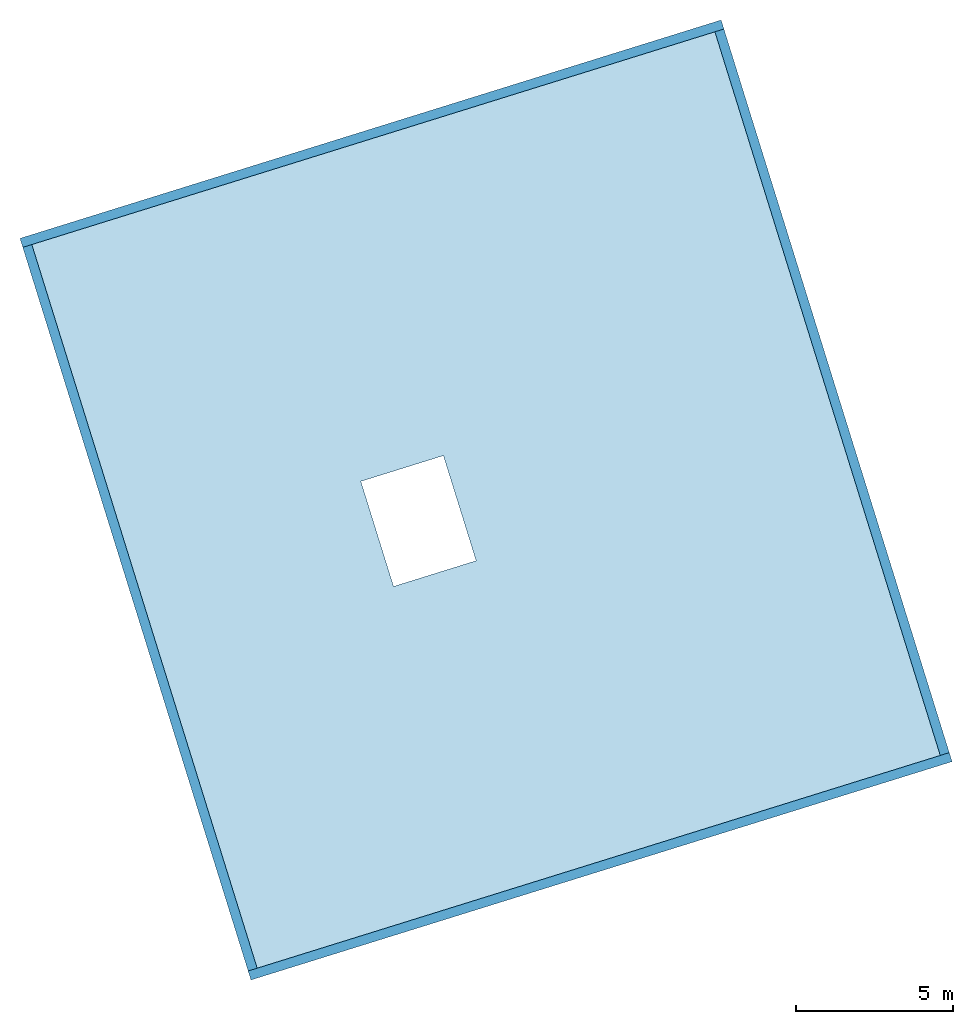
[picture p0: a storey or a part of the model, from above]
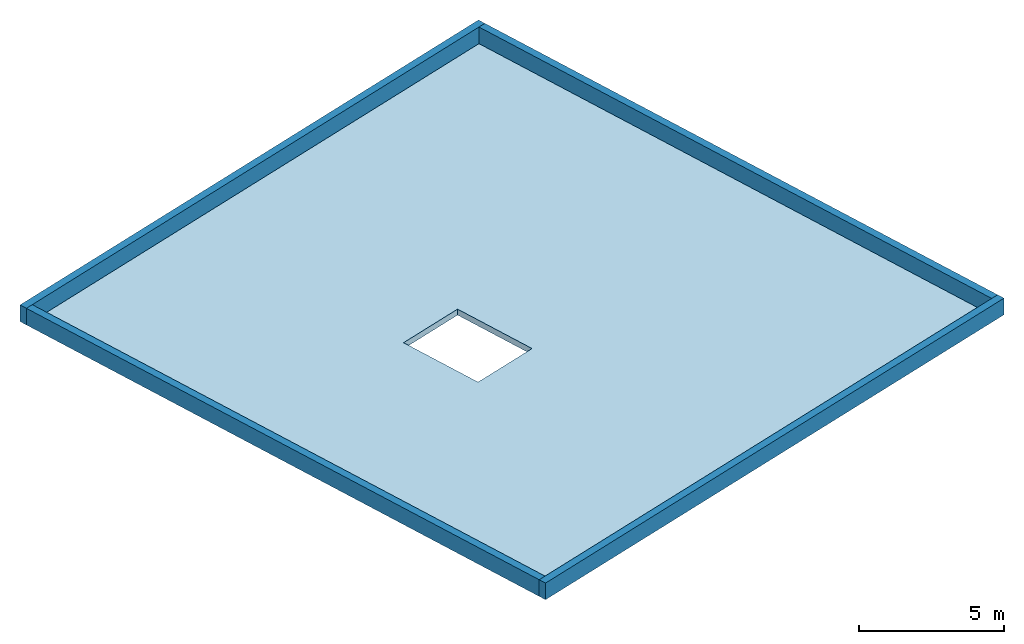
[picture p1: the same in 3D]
Properties of the parts of a building model (IFC4), part 3 of 3

# IfcSpaceType, no part of this type: Area:1710128
PredefinedType: USERDEFINED

# IfcSpaceType, no part of this type: Area:1710130
PredefinedType: USERDEFINED

# IfcSpaceType, no part of this type: Area:1710132
PredefinedType: USERDEFINED

# IfcSpaceType, no part of this type: Area:1710134
PredefinedType: USERDEFINED

# IfcSpaceType, no part of this type: Area:1710136
PredefinedType: USERDEFINED

# IfcSpaceType, no part of this type: Area:1710138
PredefinedType: USERDEFINED

# IfcSpaceType, no part of this type: Area:1710140
PredefinedType: USERDEFINED

# IfcSpaceType, no part of this type: Area:1710142
PredefinedType: USERDEFINED

# IfcSpaceType, no part of this type: Area:1710144
PredefinedType: USERDEFINED

# IfcSpaceType, no part of this type: Area:1710146
PredefinedType: USERDEFINED

# IfcSpaceType, no part of this type: Area:1710148
PredefinedType: USERDEFINED

# IfcSpaceType, no part of this type: Area:1710150
PredefinedType: USERDEFINED

# IfcSpaceType, no part of this type: Area:1710152
PredefinedType: USERDEFINED

# IfcSpaceType, no part of this type: Area:1710154
PredefinedType: USERDEFINED

# IfcSpaceType, no part of this type: Area:1710156
PredefinedType: USERDEFINED

# IfcSpaceType, no part of this type: Area:1710158
PredefinedType: USERDEFINED

# IfcSpaceType, no part of this type: Area:1710160
PredefinedType: USERDEFINED

# IfcSpaceType, no part of this type: Area:1710165
PredefinedType: USERDEFINED

# IfcSpaceType, no part of this type: Area:1710167
PredefinedType: USERDEFINED

# IfcSpaceType, no part of this type: Area:1710169
PredefinedType: USERDEFINED

# IfcSpaceType, no part of this type: Area:1710171
PredefinedType: USERDEFINED

# IfcSpaceType, no part of this type: Area:1710173
PredefinedType: USERDEFINED

# IfcSpaceType, no part of this type: Area:1710175
PredefinedType: USERDEFINED

# IfcSpaceType, no part of this type: Area:1710177
PredefinedType: USERDEFINED

# IfcSpaceType, no part of this type: Area:1710179
PredefinedType: USERDEFINED

# IfcSpaceType, no part of this type: Area:1710181
PredefinedType: USERDEFINED

# IfcSpaceType, no part of this type: Area:1710183
PredefinedType: USERDEFINED

# IfcSpaceType, no part of this type: Area:1710185
PredefinedType: USERDEFINED

# IfcSpaceType, no part of this type: Area:1710187
PredefinedType: USERDEFINED

# IfcSpaceType, no part of this type: Area:1710189
PredefinedType: USERDEFINED

# IfcSpaceType, no part of this type: Area:1710191
PredefinedType: USERDEFINED

# IfcSpaceType, no part of this type: Area:1710193
PredefinedType: USERDEFINED

# IfcSpaceType, no part of this type: Area:1710195
PredefinedType: USERDEFINED

# IfcSpaceType, no part of this type: Area:1710197
PredefinedType: USERDEFINED

# IfcSpaceType, no part of this type: Area:1710199
PredefinedType: USERDEFINED

# IfcSpaceType, no part of this type: Area:1710201
PredefinedType: USERDEFINED

# IfcSpaceType, no part of this type: Area:1710203
PredefinedType: USERDEFINED

# IfcSpaceType, no part of this type: Area:1710205
PredefinedType: USERDEFINED

# IfcSpaceType, no part of this type: Area:1710207
PredefinedType: USERDEFINED

# IfcSpaceType, no part of this type: Area:1710209
PredefinedType: USERDEFINED

# IfcSpaceType, no part of this type: Area:1710211
PredefinedType: USERDEFINED

# IfcSpaceType, no part of this type: Area:1710216
PredefinedType: USERDEFINED

# IfcSpaceType, no part of this type: Area:1710218
PredefinedType: USERDEFINED

# IfcSpaceType, no part of this type: Area:1710220
PredefinedType: USERDEFINED

# IfcSpaceType, no part of this type: Area:1710222
PredefinedType: USERDEFINED

# IfcSpaceType, no part of this type: Area:1710224
PredefinedType: USERDEFINED

# IfcSpaceType, no part of this type: Area:1710226
PredefinedType: USERDEFINED

# IfcSpaceType, no part of this type: Area:1710228
PredefinedType: USERDEFINED

# IfcSpaceType, no part of this type: Area:1710230
PredefinedType: USERDEFINED

# IfcSpaceType, no part of this type: Area:1710232
PredefinedType: USERDEFINED

# IfcSpaceType, no part of this type: Area:1710234
PredefinedType: USERDEFINED

# IfcSpaceType, no part of this type: Area:1710236
PredefinedType: USERDEFINED

# IfcSpaceType, no part of this type: Area:1710238
PredefinedType: USERDEFINED

# IfcSpaceType, no part of this type: Area:1710240
PredefinedType: USERDEFINED

# IfcSpaceType, no part of this type: Area:1710242
PredefinedType: USERDEFINED

# IfcSpaceType, no part of this type: Area:1710244
PredefinedType: USERDEFINED

# IfcSpaceType, no part of this type: Area:1710246
PredefinedType: USERDEFINED

# IfcSpaceType, no part of this type: Area:1710248
PredefinedType: USERDEFINED

# IfcSpaceType, no part of this type: Area:1710250
PredefinedType: USERDEFINED

# IfcSpaceType, no part of this type: Area:1710252
PredefinedType: USERDEFINED

# IfcSpaceType, no part of this type: Area:1710254
PredefinedType: USERDEFINED

# IfcSpaceType, no part of this type: Area:1710256
PredefinedType: USERDEFINED

# IfcSpaceType, no part of this type: Area:1710258
PredefinedType: USERDEFINED

# IfcSpaceType, no part of this type: Area:1710260
PredefinedType: USERDEFINED

# IfcSpaceType, no part of this type: Area:1710262
PredefinedType: USERDEFINED

# IfcSpaceType, no part of this type: Area:1710267
PredefinedType: USERDEFINED

# IfcSpaceType, no part of this type: Area:1710269
PredefinedType: USERDEFINED

# IfcSpaceType, no part of this type: Area:1710271
PredefinedType: USERDEFINED

# IfcSpaceType, no part of this type: Area:1710273
PredefinedType: USERDEFINED

# IfcSpaceType, no part of this type: Area:1710275
PredefinedType: USERDEFINED

# IfcSpaceType, no part of this type: Area:1710277
PredefinedType: USERDEFINED

# IfcSpaceType, no part of this type: Area:1710279
PredefinedType: USERDEFINED

# IfcSpaceType, no part of this type: Area:1710281
PredefinedType: USERDEFINED

# IfcSpaceType, no part of this type: Area:1710283
PredefinedType: USERDEFINED

# IfcSpaceType, no part of this type: Area:1710285
PredefinedType: USERDEFINED

# IfcSpaceType, no part of this type: Area:1710287
PredefinedType: USERDEFINED

# IfcSpaceType, no part of this type: Area:1710289
PredefinedType: USERDEFINED

# IfcSpaceType, no part of this type: Area:1710291
PredefinedType: USERDEFINED

# IfcSpaceType, no part of this type: Area:1710293
PredefinedType: USERDEFINED

# IfcSpaceType, no part of this type: Area:1710295
PredefinedType: USERDEFINED

# IfcSpaceType, no part of this type: Area:1710297
PredefinedType: USERDEFINED

# IfcSpaceType, no part of this type: Area:1710299
PredefinedType: USERDEFINED

# IfcSpaceType, no part of this type: Area:1710301
PredefinedType: USERDEFINED

# IfcSpaceType, no part of this type: Area:1710303
PredefinedType: USERDEFINED

# IfcSpaceType, no part of this type: Area:1710305
PredefinedType: USERDEFINED

# IfcSpaceType, no part of this type: Area:1710307
PredefinedType: USERDEFINED

# IfcSpaceType, no part of this type: Area:1710309
PredefinedType: USERDEFINED

# IfcSpaceType, no part of this type: Area:1710311
PredefinedType: USERDEFINED

# IfcSpaceType, no part of this type: Area:1710313
PredefinedType: USERDEFINED

# IfcSpaceType, no part of this type: Area:1710318
PredefinedType: USERDEFINED

# IfcSpaceType, no part of this type: Area:1710320
PredefinedType: USERDEFINED

# IfcSpaceType, no part of this type: Area:1710322
PredefinedType: USERDEFINED

# IfcSpaceType, no part of this type: Area:1710324
PredefinedType: USERDEFINED

# IfcSpaceType, no part of this type: Area:1710326
PredefinedType: USERDEFINED

# IfcSpaceType, no part of this type: Area:1710328
PredefinedType: USERDEFINED

# IfcSpaceType, no part of this type: Area:1710330
PredefinedType: USERDEFINED

# IfcSpaceType, no part of this type: Area:1710332
PredefinedType: USERDEFINED

# IfcSpaceType, no part of this type: Area:1710334
PredefinedType: USERDEFINED

# IfcSpaceType, no part of this type: Area:1710336
PredefinedType: USERDEFINED

# IfcSpaceType, no part of this type: Area:1710338
PredefinedType: USERDEFINED

# IfcSpaceType, no part of this type: Area:1710340
PredefinedType: USERDEFINED

# IfcSpaceType, no part of this type: Area:1710342
PredefinedType: USERDEFINED

# IfcSpaceType, no part of this type: Area:1710344
PredefinedType: USERDEFINED

# IfcSpaceType, no part of this type: Area:1710346
PredefinedType: USERDEFINED

# IfcSpaceType, no part of this type: Area:1710348
PredefinedType: USERDEFINED

# IfcSpaceType, no part of this type: Area:1710350
PredefinedType: USERDEFINED

# IfcSpaceType, no part of this type: Area:1710352
PredefinedType: USERDEFINED

# IfcSpaceType, no part of this type: Area:1710354
PredefinedType: USERDEFINED

# IfcSpaceType, no part of this type: Area:1710356
PredefinedType: USERDEFINED

# IfcSpaceType, no part of this type: Area:1710358
PredefinedType: USERDEFINED

# IfcSpaceType, no part of this type: Area:1710360
PredefinedType: USERDEFINED

# IfcSpaceType, no part of this type: Area:1710362
PredefinedType: USERDEFINED

# IfcSpaceType, no part of this type: Area:1710364
PredefinedType: USERDEFINED

# IfcSpaceType, no part of this type: Area:1711246
PredefinedType: USERDEFINED

# IfcSpaceType, no part of this type: Area:1711248
PredefinedType: USERDEFINED

# IfcSpaceType, no part of this type: Area:1711271
PredefinedType: USERDEFINED

# IfcSpaceType, no part of this type: Area:1711273
PredefinedType: USERDEFINED

# IfcSpaceType, no part of this type: Area:1711277
PredefinedType: USERDEFINED

# IfcSpaceType, no part of this type: Area:1711279
PredefinedType: USERDEFINED

# IfcSpaceType, no part of this type: Area:1711283
PredefinedType: USERDEFINED

# IfcSpaceType, no part of this type: Area:1711285
PredefinedType: USERDEFINED

# IfcSpaceType, no part of this type: Area:1711289
PredefinedType: USERDEFINED

# IfcSpaceType, no part of this type: Area:1711291
PredefinedType: USERDEFINED

# IfcSpaceType, no part of this type: Area:1711293
PredefinedType: USERDEFINED

# IfcSpaceType, no part of this type: Area:1711295
PredefinedType: USERDEFINED

# IfcSpaceType, no part of this type: Area:1711297
PredefinedType: USERDEFINED

# IfcSpaceType, no part of this type: Area:1711299
PredefinedType: USERDEFINED

# IfcSpaceType, no part of this type: Area:1711301
PredefinedType: USERDEFINED

# IfcSpaceType, no part of this type: Area:1711303
PredefinedType: USERDEFINED

# IfcSpaceType, no part of this type: Area:1711815
PredefinedType: USERDEFINED

# IfcSpaceType, no part of this type: Area:1711818
PredefinedType: USERDEFINED

# IfcSpaceType, no part of this type: Area:1711872
PredefinedType: USERDEFINED

# IfcSpaceType, no part of this type: Area:1711874
PredefinedType: USERDEFINED

# IfcSpaceType, no part of this type: Area:1711894
PredefinedType: USERDEFINED

# IfcSpaceType, no part of this type: Area:1711896
PredefinedType: USERDEFINED

# IfcSpaceType, no part of this type: Area:1711916
PredefinedType: USERDEFINED

# IfcSpaceType, no part of this type: Area:1711918
PredefinedType: USERDEFINED

# IfcSpaceType, no part of this type: Area:1711929
PredefinedType: USERDEFINED

# IfcSpaceType, no part of this type: Area:1711931
PredefinedType: USERDEFINED

# IfcSpaceType, no part of this type: Area:1711942
PredefinedType: USERDEFINED

# IfcSpaceType, no part of this type: Area:1711944
PredefinedType: USERDEFINED

# IfcSpaceType, no part of this type: Area:1711977
PredefinedType: USERDEFINED

# IfcSpaceType, no part of this type: Area:1711979
PredefinedType: USERDEFINED

# IfcSpaceType, no part of this type: Area:1711990
PredefinedType: USERDEFINED

# IfcSpaceType, no part of this type: Area:1711992
PredefinedType: USERDEFINED

# IfcSpaceType, no part of this type: Area:1712003
PredefinedType: USERDEFINED

# IfcSpaceType, no part of this type: Area:1712005
PredefinedType: USERDEFINED

# IfcSpaceType, no part of this type: Area:1721684
PredefinedType: USERDEFINED

# IfcSpaceType, no part of this type: Area:1721687
PredefinedType: USERDEFINED

# IfcSpaceType, no part of this type: Area:1721690
PredefinedType: USERDEFINED

# IfcSpaceType, no part of this type: Area:1721693
PredefinedType: USERDEFINED

# IfcSpaceType, no part of this type: Area:1721696
PredefinedType: USERDEFINED

# IfcSpaceType, no part of this type: Area:1721699
PredefinedType: USERDEFINED

# IfcSpaceType, no part of this type: Area:1721702
PredefinedType: USERDEFINED

# IfcSpaceType, no part of this type: Area:1721705
PredefinedType: USERDEFINED

# IfcSpaceType, no part of this type: Area:1721708
PredefinedType: USERDEFINED

# IfcSpaceType, no part of this type: Area:1721711
PredefinedType: USERDEFINED

# IfcSpaceType, no part of this type: Area:1721714
PredefinedType: USERDEFINED

# IfcSpaceType, no part of this type: Area:1721717
PredefinedType: USERDEFINED

# IfcSpaceType, no part of this type: Area:1721720
PredefinedType: USERDEFINED

# IfcSpaceType, no part of this type: Area:1721723
PredefinedType: USERDEFINED

# IfcSpaceType, no part of this type: Area:1721726
PredefinedType: USERDEFINED

# IfcSpaceType, no part of this type: Area:1721729
PredefinedType: USERDEFINED

# IfcSpaceType, no part of this type: Area:1721732
PredefinedType: USERDEFINED

# IfcSpaceType, no part of this type: Area:1721735
PredefinedType: USERDEFINED

# IfcSpaceType, no part of this type: Area:1721738
PredefinedType: USERDEFINED

# IfcSpaceType, no part of this type: Area:1721744
PredefinedType: USERDEFINED

# IfcSpaceType, no part of this type: Area:1721746
PredefinedType: USERDEFINED

# IfcSpaceType, no part of this type: Area:1721748
PredefinedType: USERDEFINED

# IfcSpaceType, no part of this type: Area:1721750
PredefinedType: USERDEFINED

# IfcSpaceType, no part of this type: Area:1721752
PredefinedType: USERDEFINED

# IfcSpaceType, no part of this type: Area:1721754
PredefinedType: USERDEFINED

# IfcSpaceType, no part of this type: Area:1721756
PredefinedType: USERDEFINED

# IfcSpaceType, no part of this type: Area:1721758
PredefinedType: USERDEFINED

# IfcSpaceType, no part of this type: Area:1721760
PredefinedType: USERDEFINED

# IfcSpaceType, no part of this type: Area:1721762
PredefinedType: USERDEFINED

# IfcSpaceType, no part of this type: Area:1721764
PredefinedType: USERDEFINED

# IfcSpaceType, no part of this type: Area:1721766
PredefinedType: USERDEFINED

# IfcSpaceType, no part of this type: Area:1721768
PredefinedType: USERDEFINED

# IfcSpaceType, no part of this type: Area:1721770
PredefinedType: USERDEFINED

# IfcSpaceType, no part of this type: Area:1721772
PredefinedType: USERDEFINED

# IfcSpaceType, no part of this type: Area:1721774
PredefinedType: USERDEFINED

# IfcSpaceType, no part of this type: Area:1721776
PredefinedType: USERDEFINED

# IfcSpaceType, no part of this type: Area:1721778
PredefinedType: USERDEFINED

# IfcSpaceType, no part of this type: Area:1721780
PredefinedType: USERDEFINED

# IfcSpaceType, no part of this type: Area:1721787
PredefinedType: USERDEFINED

# IfcSpaceType, no part of this type: Area:1721789
PredefinedType: USERDEFINED

# IfcSpaceType, no part of this type: Area:1721791
PredefinedType: USERDEFINED

# IfcSpaceType, no part of this type: Area:1721793
PredefinedType: USERDEFINED

# IfcSpaceType, no part of this type: Area:1721795
PredefinedType: USERDEFINED

# IfcSpaceType, no part of this type: Area:1721797
PredefinedType: USERDEFINED

# IfcSpaceType, no part of this type: Area:1721799
PredefinedType: USERDEFINED

# IfcSpaceType, no part of this type: Area:1721801
PredefinedType: USERDEFINED

# IfcSpaceType, no part of this type: Area:1721803
PredefinedType: USERDEFINED

# IfcSpaceType, no part of this type: Area:1721805
PredefinedType: USERDEFINED

# IfcSpaceType, no part of this type: Area:1721807
PredefinedType: USERDEFINED

# IfcSpaceType, no part of this type: Area:1721809
PredefinedType: USERDEFINED

# IfcSpaceType, no part of this type: Area:1721811
PredefinedType: USERDEFINED

# IfcSpaceType, no part of this type: Area:1721813
PredefinedType: USERDEFINED

# IfcSpaceType, no part of this type: Area:1721815
PredefinedType: USERDEFINED

# IfcSpaceType, no part of this type: Area:1721817
PredefinedType: USERDEFINED

# IfcSpaceType, no part of this type: Area:1721819
PredefinedType: USERDEFINED

# IfcSpaceType, no part of this type: Area:1721821
PredefinedType: USERDEFINED

# IfcSpaceType, no part of this type: Area:1721823
PredefinedType: USERDEFINED

# IfcSpaceType, no part of this type: Area:1721825
PredefinedType: USERDEFINED

# IfcSpaceType, no part of this type: Area:1721827
PredefinedType: USERDEFINED

# IfcSpaceType, no part of this type: Area:1721829
PredefinedType: USERDEFINED

# IfcSpaceType, no part of this type: Area:1721831
PredefinedType: USERDEFINED

# IfcSpaceType, no part of this type: Area:1721833
PredefinedType: USERDEFINED

# IfcSpaceType, no part of this type: Area:1721835
PredefinedType: USERDEFINED

# IfcSpaceType, no part of this type: Area:1721837
PredefinedType: USERDEFINED

# IfcSpaceType, no part of this type: Area:1721839
PredefinedType: USERDEFINED

# IfcSpaceType, no part of this type: Area:1721841
PredefinedType: USERDEFINED

# IfcSpaceType, no part of this type: Area:1721843
PredefinedType: USERDEFINED

# IfcSpaceType, no part of this type: Area:1721845
PredefinedType: USERDEFINED

# IfcSpaceType, no part of this type: Area:1721847
PredefinedType: USERDEFINED

# IfcSpaceType, no part of this type: Area:1721849
PredefinedType: USERDEFINED

# IfcSpaceType, no part of this type: Area:1721851
PredefinedType: USERDEFINED

# IfcSpaceType, no part of this type: Area:1721853
PredefinedType: USERDEFINED

# IfcSpaceType, no part of this type: Area:1721855
PredefinedType: USERDEFINED

# IfcSpaceType, no part of this type: Area:1721857
PredefinedType: USERDEFINED

# IfcSpaceType, no part of this type: Area:1721859
PredefinedType: USERDEFINED

# IfcSpaceType, no part of this type: Area:1721861
PredefinedType: USERDEFINED

# IfcSpaceType, no part of this type: Area:1721866
PredefinedType: USERDEFINED

# IfcSpaceType, no part of this type: Area:1721868
PredefinedType: USERDEFINED

# IfcSpaceType, no part of this type: Area:1721870
PredefinedType: USERDEFINED

# IfcSpaceType, no part of this type: Area:1721872
PredefinedType: USERDEFINED

# IfcSpaceType, no part of this type: Area:1721874
PredefinedType: USERDEFINED

# IfcSpaceType, no part of this type: Area:1721876
PredefinedType: USERDEFINED

# IfcSpaceType, no part of this type: Area:1721878
PredefinedType: USERDEFINED

# IfcSpaceType, no part of this type: Area:1721880
PredefinedType: USERDEFINED

# IfcSpaceType, no part of this type: Area:1721882
PredefinedType: USERDEFINED

# IfcSpaceType, no part of this type: Area:1721884
PredefinedType: USERDEFINED

# IfcSpaceType, no part of this type: Area:1721886
PredefinedType: USERDEFINED

# IfcSpaceType, no part of this type: Area:1721888
PredefinedType: USERDEFINED

# IfcSpaceType, no part of this type: Area:1721890
PredefinedType: USERDEFINED

# IfcSpaceType, no part of this type: Area:1721892
PredefinedType: USERDEFINED

# IfcSpaceType, no part of this type: Area:1721894
PredefinedType: USERDEFINED

# IfcSpaceType, no part of this type: Area:1721896
PredefinedType: USERDEFINED

# IfcSpaceType, no part of this type: Area:1721898
PredefinedType: USERDEFINED

# IfcSpaceType, no part of this type: Area:1721900
PredefinedType: USERDEFINED

# IfcSpaceType, no part of this type: Area:1721902
PredefinedType: USERDEFINED

# IfcSpaceType, no part of this type: Area:1721904
PredefinedType: USERDEFINED

# IfcSpaceType, no part of this type: Area:1721906
PredefinedType: USERDEFINED

# IfcSpaceType, no part of this type: Area:1721908
PredefinedType: USERDEFINED

# IfcSpaceType, no part of this type: Area:1721910
PredefinedType: USERDEFINED

# IfcSpaceType, no part of this type: Area:1721912
PredefinedType: USERDEFINED

# IfcSpaceType, no part of this type: Area:1721914
PredefinedType: USERDEFINED

# IfcSpaceType, no part of this type: Area:1721916
PredefinedType: USERDEFINED

# IfcSpaceType, no part of this type: Area:1721918
PredefinedType: USERDEFINED

# IfcSpaceType, no part of this type: Area:1721920
PredefinedType: USERDEFINED

# IfcSpaceType, no part of this type: Area:1721922
PredefinedType: USERDEFINED

# IfcSpaceType, no part of this type: Area:1721924
PredefinedType: USERDEFINED

# IfcSpaceType, no part of this type: Area:1721926
PredefinedType: USERDEFINED

# IfcSpaceType, no part of this type: Area:1721928
PredefinedType: USERDEFINED

# IfcSpaceType, no part of this type: Area:1721930
PredefinedType: USERDEFINED

# IfcSpaceType, no part of this type: Area:1721932
PredefinedType: USERDEFINED

# IfcSpaceType, no part of this type: Area:1721934
PredefinedType: USERDEFINED

# IfcSpaceType, no part of this type: Area:1721936
PredefinedType: USERDEFINED

# IfcSpaceType, no part of this type: Area:1721938
PredefinedType: USERDEFINED

# IfcSpaceType, no part of this type: Area:1721940
PredefinedType: USERDEFINED

# IfcSpaceType, no part of this type: Area:1721945
PredefinedType: USERDEFINED

# IfcSpaceType, no part of this type: Area:1721947
PredefinedType: USERDEFINED

# IfcSpaceType, no part of this type: Area:1721949
PredefinedType: USERDEFINED

# IfcSpaceType, no part of this type: Area:1721951
PredefinedType: USERDEFINED

# IfcSpaceType, no part of this type: Area:1721953
PredefinedType: USERDEFINED

# IfcSpaceType, no part of this type: Area:1721955
PredefinedType: USERDEFINED

# IfcSpaceType, no part of this type: Area:1721957
PredefinedType: USERDEFINED

# IfcSpaceType, no part of this type: Area:1721959
PredefinedType: USERDEFINED

# IfcSpaceType, no part of this type: Area:1721961
PredefinedType: USERDEFINED

# IfcSpaceType, no part of this type: Area:1721963
PredefinedType: USERDEFINED

# IfcSpaceType, no part of this type: Area:1721965
PredefinedType: USERDEFINED

# IfcSpaceType, no part of this type: Area:1721967
PredefinedType: USERDEFINED

# IfcSpaceType, no part of this type: Area:1721969
PredefinedType: USERDEFINED

# IfcSpaceType, no part of this type: Area:1721971
PredefinedType: USERDEFINED

# IfcSpaceType, no part of this type: Area:1721973
PredefinedType: USERDEFINED

# IfcSpaceType, no part of this type: Area:1721975
PredefinedType: USERDEFINED

# IfcSpaceType, no part of this type: Area:1721977
PredefinedType: USERDEFINED

# IfcSpaceType, no part of this type: Area:1721979
PredefinedType: USERDEFINED

# IfcSpaceType, no part of this type: Area:1721981
PredefinedType: USERDEFINED

# IfcSpaceType, no part of this type: Area:1721983
PredefinedType: USERDEFINED

# IfcSpaceType, no part of this type: Area:1721985
PredefinedType: USERDEFINED

# IfcSpaceType, no part of this type: Area:1721987
PredefinedType: USERDEFINED

# IfcSpaceType, no part of this type: Area:1721989
PredefinedType: USERDEFINED

# IfcSpaceType, no part of this type: Area:1721991
PredefinedType: USERDEFINED

# IfcSpaceType, no part of this type: Area:1721993
PredefinedType: USERDEFINED

# IfcSpaceType, no part of this type: Area:1721995
PredefinedType: USERDEFINED

# IfcSpaceType, no part of this type: Area:1721997
PredefinedType: USERDEFINED

# IfcSpaceType, no part of this type: Area:1721999
PredefinedType: USERDEFINED

# IfcSpaceType, no part of this type: Area:1722001
PredefinedType: USERDEFINED

# IfcSpaceType, no part of this type: Area:1722003
PredefinedType: USERDEFINED

# IfcSpaceType, no part of this type: Area:1722005
PredefinedType: USERDEFINED

# IfcSpaceType, no part of this type: Area:1722007
PredefinedType: USERDEFINED

# IfcSpaceType, no part of this type: Area:1722009
PredefinedType: USERDEFINED

# IfcSpaceType, no part of this type: Area:1722011
PredefinedType: USERDEFINED

# IfcSpaceType, no part of this type: Area:1722013
PredefinedType: USERDEFINED

# IfcSpaceType, no part of this type: Area:1722015
PredefinedType: USERDEFINED

# IfcSpaceType, no part of this type: Area:1722017
PredefinedType: USERDEFINED

# IfcSpaceType, no part of this type: Area:1722019
PredefinedType: USERDEFINED

# IfcSpaceType, no part of this type: Area:1722024
PredefinedType: USERDEFINED

# IfcSpaceType, no part of this type: Area:1722026
PredefinedType: USERDEFINED

# IfcSpaceType, no part of this type: Area:1722028
PredefinedType: USERDEFINED

# IfcSpaceType, no part of this type: Area:1722030
PredefinedType: USERDEFINED

# IfcSpaceType, no part of this type: Area:1722032
PredefinedType: USERDEFINED

# IfcSpaceType, no part of this type: Area:1722034
PredefinedType: USERDEFINED

# IfcSpaceType, no part of this type: Area:1722036
PredefinedType: USERDEFINED

# IfcSpaceType, no part of this type: Area:1722038
PredefinedType: USERDEFINED

# IfcSpaceType, no part of this type: Area:1722040
PredefinedType: USERDEFINED

# IfcSpaceType, no part of this type: Area:1722042
PredefinedType: USERDEFINED

# IfcSpaceType, no part of this type: Area:1722044
PredefinedType: USERDEFINED

# IfcSpaceType, no part of this type: Area:1722046
PredefinedType: USERDEFINED

# IfcSpaceType, no part of this type: Area:1722048
PredefinedType: USERDEFINED

# IfcSpaceType, no part of this type: Area:1722050
PredefinedType: USERDEFINED

# IfcSpaceType, no part of this type: Area:1722052
PredefinedType: USERDEFINED

# IfcSpaceType, no part of this type: Area:1722054
PredefinedType: USERDEFINED

# IfcSpaceType, no part of this type: Area:1722056
PredefinedType: USERDEFINED

# IfcSpaceType, no part of this type: Area:1722058
PredefinedType: USERDEFINED

# IfcSpaceType, no part of this type: Area:1722060
PredefinedType: USERDEFINED

# IfcSpaceType, no part of this type: Area:1722062
PredefinedType: USERDEFINED

# IfcSpaceType, no part of this type: Area:1722064
PredefinedType: USERDEFINED

# IfcSpaceType, no part of this type: Area:1722066
PredefinedType: USERDEFINED

# IfcSpaceType, no part of this type: Area:1722068
PredefinedType: USERDEFINED

# IfcSpaceType, no part of this type: Area:1722070
PredefinedType: USERDEFINED

# IfcSpaceType, no part of this type: Area:1722072
PredefinedType: USERDEFINED

# IfcSpaceType, no part of this type: Area:1722074
PredefinedType: USERDEFINED

# IfcSpaceType, no part of this type: Area:1722076
PredefinedType: USERDEFINED

# IfcSpaceType, no part of this type: Area:1722078
PredefinedType: USERDEFINED

# IfcSpaceType, no part of this type: Area:1722080
PredefinedType: USERDEFINED

# IfcSpaceType, no part of this type: Area:1722082
PredefinedType: USERDEFINED

# IfcSpaceType, no part of this type: Area:1722084
PredefinedType: USERDEFINED

# IfcSpaceType, no part of this type: Area:1722086
PredefinedType: USERDEFINED

# IfcSpaceType, no part of this type: Area:1722088
PredefinedType: USERDEFINED

# IfcSpaceType, no part of this type: Area:1722090
PredefinedType: USERDEFINED

# IfcSpaceType, no part of this type: Area:1722092
PredefinedType: USERDEFINED

# IfcSpaceType, no part of this type: Area:1722094
PredefinedType: USERDEFINED

# IfcSpaceType, no part of this type: Area:1722096
PredefinedType: USERDEFINED

# IfcSpaceType, no part of this type: Area:1722098
PredefinedType: USERDEFINED

# IfcSpaceType, no part of this type: Area:1722103
PredefinedType: USERDEFINED

# IfcSpaceType, no part of this type: Area:1722105
PredefinedType: USERDEFINED

# IfcSpaceType, no part of this type: Area:1722107
PredefinedType: USERDEFINED

# IfcSpaceType, no part of this type: Area:1722109
PredefinedType: USERDEFINED

# IfcSpaceType, no part of this type: Area:1722111
PredefinedType: USERDEFINED

# IfcSpaceType, no part of this type: Area:1722113
PredefinedType: USERDEFINED

# IfcSpaceType, no part of this type: Area:1722115
PredefinedType: USERDEFINED

# IfcSpaceType, no part of this type: Area:1722117
PredefinedType: USERDEFINED

# IfcSpaceType, no part of this type: Area:1722119
PredefinedType: USERDEFINED

# IfcSpaceType, no part of this type: Area:1722121
PredefinedType: USERDEFINED

# IfcSpaceType, no part of this type: Area:1722123
PredefinedType: USERDEFINED

# IfcSpaceType, no part of this type: Area:1722125
PredefinedType: USERDEFINED

# IfcSpaceType, no part of this type: Area:1722127
PredefinedType: USERDEFINED

# IfcSpaceType, no part of this type: Area:1722129
PredefinedType: USERDEFINED

# IfcSpaceType, no part of this type: Area:1722131
PredefinedType: USERDEFINED

# IfcSpaceType, no part of this type: Area:1722133
PredefinedType: USERDEFINED

# IfcSpaceType, no part of this type: Area:1722135
PredefinedType: USERDEFINED

# IfcSpaceType, no part of this type: Area:1722137
PredefinedType: USERDEFINED

# IfcSpaceType, no part of this type: Area:1722139
PredefinedType: USERDEFINED

# IfcSpaceType, no part of this type: Area:1722141
PredefinedType: USERDEFINED

# IfcSpaceType, no part of this type: Area:1722143
PredefinedType: USERDEFINED

# IfcSpaceType, no part of this type: Area:1722145
PredefinedType: USERDEFINED

# IfcSpaceType, no part of this type: Area:1722147
PredefinedType: USERDEFINED

# IfcSpaceType, no part of this type: Area:1722149
PredefinedType: USERDEFINED

# IfcSpaceType, no part of this type: Area:1722151
PredefinedType: USERDEFINED

# IfcSpaceType, no part of this type: Area:1722153
PredefinedType: USERDEFINED

# IfcSpaceType, no part of this type: Area:1722155
PredefinedType: USERDEFINED

# IfcSpaceType, no part of this type: Area:1722157
PredefinedType: USERDEFINED

# IfcSpaceType, no part of this type: Area:1722159
PredefinedType: USERDEFINED

# IfcSpaceType, no part of this type: Area:1722161
PredefinedType: USERDEFINED

# IfcSpaceType, no part of this type: Area:1722163
PredefinedType: USERDEFINED

# IfcSpaceType, no part of this type: Area:1722165
PredefinedType: USERDEFINED

# IfcSpaceType, no part of this type: Area:1722167
PredefinedType: USERDEFINED

# IfcSpaceType, no part of this type: Area:1722169
PredefinedType: USERDEFINED

# IfcSpaceType, no part of this type: Area:1722171
PredefinedType: USERDEFINED

# IfcSpaceType, no part of this type: Area:1722173
PredefinedType: USERDEFINED

# IfcSpaceType, no part of this type: Area:1722175
PredefinedType: USERDEFINED

# IfcSpaceType, no part of this type: Area:1722177
PredefinedType: USERDEFINED

# IfcSpaceType, no part of this type: Area:1722182
PredefinedType: USERDEFINED

# IfcSpaceType, no part of this type: Area:1722184
PredefinedType: USERDEFINED

# IfcSpaceType, no part of this type: Area:1722186
PredefinedType: USERDEFINED

# IfcSpaceType, no part of this type: Area:1722188
PredefinedType: USERDEFINED

# IfcSpaceType, no part of this type: Area:1722190
PredefinedType: USERDEFINED

# IfcSpaceType, no part of this type: Area:1722192
PredefinedType: USERDEFINED

# IfcSpaceType, no part of this type: Area:1722194
PredefinedType: USERDEFINED

# IfcSpaceType, no part of this type: Area:1722196
PredefinedType: USERDEFINED

# IfcSpaceType, no part of this type: Area:1722198
PredefinedType: USERDEFINED

# IfcSpaceType, no part of this type: Area:1722200
PredefinedType: USERDEFINED

# IfcSpaceType, no part of this type: Area:1722202
PredefinedType: USERDEFINED

# IfcSpaceType, no part of this type: Area:1722204
PredefinedType: USERDEFINED

# IfcSpaceType, no part of this type: Area:1722206
PredefinedType: USERDEFINED

# IfcSpaceType, no part of this type: Area:1722208
PredefinedType: USERDEFINED

# IfcSpaceType, no part of this type: Area:1722210
PredefinedType: USERDEFINED

# IfcSpaceType, no part of this type: Area:1722212
PredefinedType: USERDEFINED

# IfcSpaceType, no part of this type: Area:1722214
PredefinedType: USERDEFINED

# IfcSpaceType, no part of this type: Area:1722216
PredefinedType: USERDEFINED

# IfcSpaceType, no part of this type: Area:1722218
PredefinedType: USERDEFINED

# IfcSpaceType, no part of this type: Area:1722220
PredefinedType: USERDEFINED

# IfcSpaceType, no part of this type: Area:1722222
PredefinedType: USERDEFINED

# IfcSpaceType, no part of this type: Area:1722224
PredefinedType: USERDEFINED

# IfcSpaceType, no part of this type: Area:1722226
PredefinedType: USERDEFINED

# IfcSpaceType, no part of this type: Area:1722228
PredefinedType: USERDEFINED

# IfcSpaceType, no part of this type: Area:1722230
PredefinedType: USERDEFINED

# IfcSpaceType, no part of this type: Area:1722232
PredefinedType: USERDEFINED

# IfcSpaceType, no part of this type: Area:1722234
PredefinedType: USERDEFINED

# IfcSpaceType, no part of this type: Area:1722236
PredefinedType: USERDEFINED

# IfcSpaceType, no part of this type: Area:1722238
PredefinedType: USERDEFINED

# IfcSpaceType, no part of this type: Area:1722240
PredefinedType: USERDEFINED

# IfcSpaceType, no part of this type: Area:1722242
PredefinedType: USERDEFINED

# IfcSpaceType, no part of this type: Area:1722244
PredefinedType: USERDEFINED

# IfcSpaceType, no part of this type: Area:1722246
PredefinedType: USERDEFINED

# IfcSpaceType, no part of this type: Area:1722248
PredefinedType: USERDEFINED

# IfcSpaceType, no part of this type: Area:1722250
PredefinedType: USERDEFINED

# IfcSpaceType, no part of this type: Area:1722252
PredefinedType: USERDEFINED

# IfcSpaceType, no part of this type: Area:1722254
PredefinedType: USERDEFINED

# IfcSpaceType, no part of this type: Area:1722256
PredefinedType: USERDEFINED

# IfcSpaceType, no part of this type: Area:1746594
PredefinedType: USERDEFINED

# IfcSpaceType, no part of this type: Area:1746615
PredefinedType: USERDEFINED

# IfcSpaceType, no part of this type: Area:1746631
PredefinedType: USERDEFINED

# IfcSpaceType, no part of this type: Area:1746647
PredefinedType: USERDEFINED

# IfcSpaceType, no part of this type: Area:1746658
PredefinedType: USERDEFINED

# IfcSpaceType, no part of this type: Area:1746660
PredefinedType: USERDEFINED

# IfcSpaceType, no part of this type: Area:1746662
PredefinedType: USERDEFINED

# IfcSpaceType, no part of this type: Area:1747504
PredefinedType: USERDEFINED

# IfcSpaceType, no part of this type: Area:1747507
PredefinedType: USERDEFINED

# IfcSpaceType, no part of this type: Area:1747510
PredefinedType: USERDEFINED

# IfcSpaceType, no part of this type: Area:1747588
PredefinedType: USERDEFINED

# IfcSpaceType, no part of this type: Area:1747590
PredefinedType: USERDEFINED

# IfcSpaceType, no part of this type: Area:1747592
PredefinedType: USERDEFINED

# IfcSpaceType, no part of this type: Area:1747599
PredefinedType: USERDEFINED

# IfcSpaceType, no part of this type: Area:1747601
PredefinedType: USERDEFINED

# IfcSpaceType, no part of this type: Area:1747603
PredefinedType: USERDEFINED

# IfcSpaceType, no part of this type: Area:1747623
PredefinedType: USERDEFINED

# IfcSpaceType, no part of this type: Area:1747625
PredefinedType: USERDEFINED

# IfcSpaceType, no part of this type: Area:1747627
PredefinedType: USERDEFINED

# IfcSpaceType, no part of this type: Area:1747629
PredefinedType: USERDEFINED

# IfcSpaceType, no part of this type: Area:1747631
PredefinedType: USERDEFINED

# IfcSpaceType, no part of this type: Area:1747633
PredefinedType: USERDEFINED

# IfcSpaceType, no part of this type: Area:1747634
PredefinedType: USERDEFINED

# IfcSpaceType, no part of this type: Area:1747636
PredefinedType: USERDEFINED

# IfcSpaceType, no part of this type: Area:1747638
PredefinedType: USERDEFINED

# IfcSpaceType, no part of this type: Area:1747641
PredefinedType: USERDEFINED

# IfcSpaceType, no part of this type: Area:1747643
PredefinedType: USERDEFINED

# IfcSpaceType, no part of this type: Area:1747645
PredefinedType: USERDEFINED

# IfcSpaceType, no part of this type: Area:1747647
PredefinedType: USERDEFINED

# IfcSpaceType, no part of this type: Area:1747649
PredefinedType: USERDEFINED

# IfcSpaceType, no part of this type: Area:1747651
PredefinedType: USERDEFINED

# IfcSpaceType, no part of this type: Area:1747652
PredefinedType: USERDEFINED

# IfcSpaceType, no part of this type: Area:1747654
PredefinedType: USERDEFINED

# IfcSpaceType, no part of this type: Area:1747656
PredefinedType: USERDEFINED

# IfcSpaceType, no part of this type: Area:1747659
PredefinedType: USERDEFINED

# IfcSpaceType, no part of this type: Area:1747660
PredefinedType: USERDEFINED

# IfcSpaceType, no part of this type: Area:1747661
PredefinedType: USERDEFINED

# IfcSpaceType, no part of this type: Area:1747662
PredefinedType: USERDEFINED

# IfcSpaceType, no part of this type: Area:1747663
PredefinedType: USERDEFINED

# IfcSpaceType, no part of this type: Area:1747664
PredefinedType: USERDEFINED

# IfcSpaceType, no part of this type: Area:1747665
PredefinedType: USERDEFINED

# IfcSpaceType, no part of this type: Area:1747666
PredefinedType: USERDEFINED

# IfcSpaceType, no part of this type: Area:1747667
PredefinedType: USERDEFINED

# IfcSpaceType, no part of this type: Area:1747668
PredefinedType: USERDEFINED

# IfcSpaceType, no part of this type: Area:1747669
PredefinedType: USERDEFINED

# IfcSpaceType, no part of this type: Area:1747670
PredefinedType: USERDEFINED

# IfcSpaceType, no part of this type: Area:1747671
PredefinedType: USERDEFINED

# IfcSpaceType, no part of this type: Area:1747672
PredefinedType: USERDEFINED

# IfcSpaceType, no part of this type: Area:1747673
PredefinedType: USERDEFINED

# IfcSpaceType, no part of this type: Area:1747674
PredefinedType: USERDEFINED

# IfcSpaceType, no part of this type: Area:1747675
PredefinedType: USERDEFINED

# IfcSpaceType, no part of this type: Area:1747676
PredefinedType: USERDEFINED

# IfcSpaceType, no part of this type: Area:1747707
PredefinedType: USERDEFINED

# IfcSpaceType, no part of this type: Area:1747717
PredefinedType: USERDEFINED

# IfcSpaceType, no part of this type: Area:1747745
PredefinedType: USERDEFINED

# IfcSpaceType, no part of this type: Area:1747757
PredefinedType: USERDEFINED

# IfcSpaceType, no part of this type: Area:1747759
PredefinedType: USERDEFINED

# IfcSpaceType, no part of this type: Area:1747761
PredefinedType: USERDEFINED

# IfcSpaceType, no part of this type: Area:1747765
PredefinedType: USERDEFINED

# IfcSpaceType, no part of this type: Area:1747767
PredefinedType: USERDEFINED

# IfcSpaceType, no part of this type: Area:1747769
PredefinedType: USERDEFINED

# IfcSpaceType, no part of this type: Area:1747777
PredefinedType: USERDEFINED

# IfcSpaceType, no part of this type: Area:1747779
PredefinedType: USERDEFINED

# IfcSpaceType, no part of this type: Area:1747781
PredefinedType: USERDEFINED

# IfcSpaceType, no part of this type: Area:1747786
PredefinedType: USERDEFINED

# IfcSpaceType, no part of this type: Area:1747790
PredefinedType: USERDEFINED

# IfcSpaceType, no part of this type: Area:1747792
PredefinedType: USERDEFINED

# IfcSpaceType, no part of this type: Area:1747794
PredefinedType: USERDEFINED

# IfcSpaceType, no part of this type: Area:1747796
PredefinedType: USERDEFINED

# IfcSpaceType, no part of this type: Area:1747798
PredefinedType: USERDEFINED

# IfcSpaceType, no part of this type: Area:1747800
PredefinedType: USERDEFINED

# IfcSpaceType, no part of this type: Area:1747802
PredefinedType: USERDEFINED

# IfcSpaceType, no part of this type: Area:1747804
PredefinedType: USERDEFINED

# IfcSpaceType, no part of this type: Area:1747806
PredefinedType: USERDEFINED

# IfcSpaceType, no part of this type: Area:1747808
PredefinedType: USERDEFINED

# IfcSpaceType, no part of this type: Area:1747810
PredefinedType: USERDEFINED

# IfcSpaceType, no part of this type: Area:1747812
PredefinedType: USERDEFINED

# IfcSpaceType, no part of this type: Area:1747814
PredefinedType: USERDEFINED

# IfcSpaceType, no part of this type: Area:1748313
PredefinedType: USERDEFINED

# IfcSpaceType, no part of this type: Area:1748340
PredefinedType: USERDEFINED

# IfcSpaceType, no part of this type: Area:1748362
PredefinedType: USERDEFINED

# IfcSpaceType, no part of this type: Area:1748378
PredefinedType: USERDEFINED

# IfcSpaceType, no part of this type: Area:1748389
PredefinedType: USERDEFINED

# IfcSpaceType, no part of this type: Area:1748391
PredefinedType: USERDEFINED

# IfcSpaceType, no part of this type: Area:1748393
PredefinedType: USERDEFINED

# IfcSpaceType, no part of this type: Area:1748518
PredefinedType: USERDEFINED

# IfcSpaceType, no part of this type: Area:1759840
PredefinedType: USERDEFINED

# IfcSpaceType, no part of this type: Area:1759847
PredefinedType: USERDEFINED

# IfcSpaceType, no part of this type: Area:1759850
PredefinedType: USERDEFINED

# IfcSpaceType, no part of this type: Area:1759851
PredefinedType: USERDEFINED

# IfcSpaceType, no part of this type: Area:1759854
PredefinedType: USERDEFINED

# IfcSpaceType, no part of this type: Area:1759855
PredefinedType: USERDEFINED

# IfcSpaceType, no part of this type: Area:1759858
PredefinedType: USERDEFINED

# IfcSpaceType, no part of this type: Area:1759859
PredefinedType: USERDEFINED

# IfcSpaceType, no part of this type: Area:1759862
PredefinedType: USERDEFINED

# IfcSpaceType, no part of this type: Area:1759863
PredefinedType: USERDEFINED

# IfcSpaceType, no part of this type: Area:1759866
PredefinedType: USERDEFINED

# IfcSpaceType, no part of this type: Area:1759867
PredefinedType: USERDEFINED

# IfcSpaceType, no part of this type: Area:1759870
PredefinedType: USERDEFINED

# IfcSpaceType, no part of this type: Area:1759871
PredefinedType: USERDEFINED

# IfcSpaceType, no part of this type: Area:1760089
PredefinedType: USERDEFINED

# IfcSpaceType, no part of this type: Area:1760090
PredefinedType: USERDEFINED

# IfcSpaceType, no part of this type: Area:1762312
PredefinedType: USERDEFINED

# IfcSpaceType, no part of this type: Area:1762315
PredefinedType: USERDEFINED

# IfcSpaceType, no part of this type: Area:1762318
PredefinedType: USERDEFINED

# IfcSpaceType, no part of this type: Area:1762321
PredefinedType: USERDEFINED

# IfcSpaceType, no part of this type: Area:1762327
PredefinedType: USERDEFINED

# IfcSpaceType, no part of this type: Area:1762329
PredefinedType: USERDEFINED

# IfcSpaceType, no part of this type: Area:1762331
PredefinedType: USERDEFINED

# IfcSpaceType, no part of this type: Area:1762346
PredefinedType: USERDEFINED

# IfcSpaceType, no part of this type: Area:1767419
PredefinedType: USERDEFINED

# IfcSpaceType, no part of this type: Area:1767422
PredefinedType: USERDEFINED

# IfcSpaceType, no part of this type: Area:1767425
PredefinedType: USERDEFINED

# IfcSpaceType, no part of this type: Area:1767428
PredefinedType: USERDEFINED

# IfcSpaceType, no part of this type: Area:1767431
PredefinedType: USERDEFINED

# IfcSpaceType, no part of this type: Area:1767434
PredefinedType: USERDEFINED

# IfcSpaceType, no part of this type: Area:1767437
PredefinedType: USERDEFINED

# IfcSpaceType, no part of this type: Area:1767440
PredefinedType: USERDEFINED

# IfcSpaceType, no part of this type: Area:1767443
PredefinedType: USERDEFINED

# IfcSpaceType, no part of this type: Area:1767446
PredefinedType: USERDEFINED

# IfcSpaceType, no part of this type: Area:1767449
PredefinedType: USERDEFINED

# IfcSpaceType, no part of this type: Area:1767452
PredefinedType: USERDEFINED

# IfcSpaceType, no part of this type: Area:1767455
PredefinedType: USERDEFINED

# IfcSpaceType, no part of this type: Area:1767458
PredefinedType: USERDEFINED

# IfcSpaceType, no part of this type: Area:1767461
PredefinedType: USERDEFINED

# IfcSpaceType, no part of this type: Area:1767464
PredefinedType: USERDEFINED

# IfcSpaceType, no part of this type: Area:1767467
PredefinedType: USERDEFINED

# IfcSpaceType, no part of this type: Area:1767470
PredefinedType: USERDEFINED

# IfcSpaceType, no part of this type: Area:1767473
PredefinedType: USERDEFINED

# IfcSpaceType, no part of this type: Area:1767543
PredefinedType: USERDEFINED
